VERSION 5.8 ;
BUSBITCHARS "[]" ;
DIVIDERCHAR "/" ;
UNITS
    DATABASE MICRONS 1000 ;
END UNITS

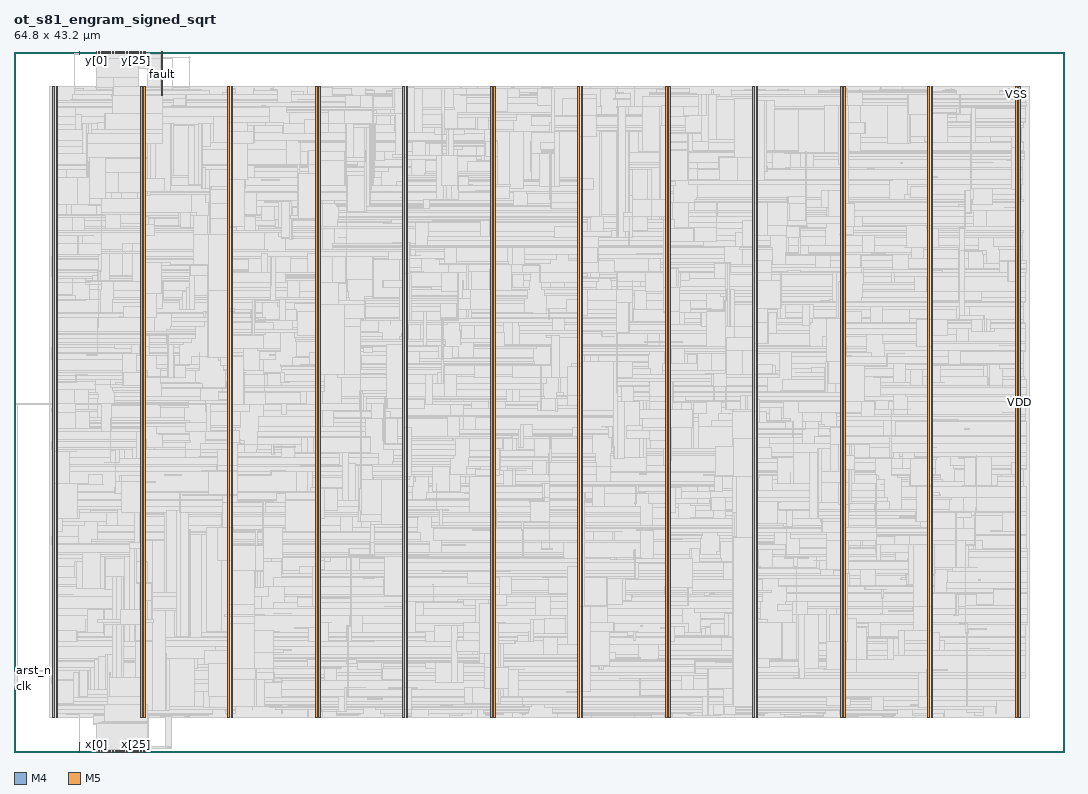
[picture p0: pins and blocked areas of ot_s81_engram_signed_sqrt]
MACRO ot_s81_engram_signed_sqrt
  FOREIGN ot_s81_engram_signed_sqrt 0 0 ;
  CLASS BLOCK ;
  SIZE 64.8 BY 43.2 ;
  PIN arst_n
    DIRECTION INPUT ;
    USE SIGNAL ;
    PORT
      LAYER M4 ;
        RECT  0 4.992 0.084 5.016 ;
    END
  END arst_n
  PIN clk
    DIRECTION INPUT ;
    USE SIGNAL ;
    PORT
      LAYER M4 ;
        RECT  0 4.032 0.084 4.056 ;
    END
  END clk
  PIN fault
    DIRECTION OUTPUT ;
    USE SIGNAL ;
    PORT
      LAYER M5 ;
        RECT  9.12 43.116 9.144 43.2 ;
    END
    PORT
      LAYER M5 ;
        RECT  9.12 40.499 9.144 43.152 ;
    END
  END fault
  PIN v
    DIRECTION INPUT ;
    USE SIGNAL ;
    PORT
      LAYER M5 ;
        RECT  4.032 0 4.056 0.084 ;
    END
    PORT
      LAYER M5 ;
        RECT  4.032 0.016 4.056 0.611 ;
    END
  END v
  PIN vo
    DIRECTION OUTPUT ;
    USE SIGNAL ;
    PORT
      LAYER M5 ;
        RECT  4.032 43.116 4.056 43.2 ;
    END
    PORT
      LAYER M5 ;
        RECT  4.032 43.045 4.056 43.152 ;
    END
  END vo
  PIN x[0]
    DIRECTION INPUT ;
    USE SIGNAL ;
    PORT
      LAYER M5 ;
        RECT  5.088 0 5.112 0.084 ;
    END
  END x[0]
  PIN x[10]
    DIRECTION INPUT ;
    USE SIGNAL ;
    PORT
      LAYER M5 ;
        RECT  6.048 0 6.072 0.084 ;
    END
  END x[10]
  PIN x[11]
    DIRECTION INPUT ;
    USE SIGNAL ;
    PORT
      LAYER M5 ;
        RECT  6.144 0 6.168 0.084 ;
    END
  END x[11]
  PIN x[12]
    DIRECTION INPUT ;
    USE SIGNAL ;
    PORT
      LAYER M5 ;
        RECT  6.24 0 6.264 0.084 ;
    END
  END x[12]
  PIN x[13]
    DIRECTION INPUT ;
    USE SIGNAL ;
    PORT
      LAYER M5 ;
        RECT  6.336 0 6.36 0.084 ;
    END
  END x[13]
  PIN x[14]
    DIRECTION INPUT ;
    USE SIGNAL ;
    PORT
      LAYER M5 ;
        RECT  6.432 0 6.456 0.084 ;
    END
  END x[14]
  PIN x[15]
    DIRECTION INPUT ;
    USE SIGNAL ;
    PORT
      LAYER M5 ;
        RECT  6.528 0 6.552 0.084 ;
    END
  END x[15]
  PIN x[16]
    DIRECTION INPUT ;
    USE SIGNAL ;
    PORT
      LAYER M5 ;
        RECT  6.624 0 6.648 0.084 ;
    END
  END x[16]
  PIN x[17]
    DIRECTION INPUT ;
    USE SIGNAL ;
    PORT
      LAYER M5 ;
        RECT  6.72 0 6.744 0.084 ;
    END
  END x[17]
  PIN x[18]
    DIRECTION INPUT ;
    USE SIGNAL ;
    PORT
      LAYER M5 ;
        RECT  6.816 0 6.84 0.084 ;
    END
  END x[18]
  PIN x[19]
    DIRECTION INPUT ;
    USE SIGNAL ;
    PORT
      LAYER M5 ;
        RECT  6.912 0 6.936 0.084 ;
    END
  END x[19]
  PIN x[1]
    DIRECTION INPUT ;
    USE SIGNAL ;
    PORT
      LAYER M5 ;
        RECT  5.184 0 5.208 0.084 ;
    END
  END x[1]
  PIN x[20]
    DIRECTION INPUT ;
    USE SIGNAL ;
    PORT
      LAYER M5 ;
        RECT  7.008 0 7.032 0.084 ;
    END
  END x[20]
  PIN x[21]
    DIRECTION INPUT ;
    USE SIGNAL ;
    PORT
      LAYER M5 ;
        RECT  7.104 0 7.128 0.084 ;
    END
  END x[21]
  PIN x[22]
    DIRECTION INPUT ;
    USE SIGNAL ;
    PORT
      LAYER M5 ;
        RECT  7.2 0 7.224 0.084 ;
    END
  END x[22]
  PIN x[23]
    DIRECTION INPUT ;
    USE SIGNAL ;
    PORT
      LAYER M5 ;
        RECT  7.296 0 7.32 0.084 ;
    END
  END x[23]
  PIN x[24]
    DIRECTION INPUT ;
    USE SIGNAL ;
    PORT
      LAYER M5 ;
        RECT  7.392 0 7.416 0.084 ;
    END
  END x[24]
  PIN x[25]
    DIRECTION INPUT ;
    USE SIGNAL ;
    PORT
      LAYER M5 ;
        RECT  7.488 0 7.512 0.084 ;
    END
  END x[25]
  PIN x[26]
    DIRECTION INPUT ;
    USE SIGNAL ;
    PORT
      LAYER M5 ;
        RECT  7.584 0 7.608 0.084 ;
    END
  END x[26]
  PIN x[27]
    DIRECTION INPUT ;
    USE SIGNAL ;
    PORT
      LAYER M5 ;
        RECT  7.68 0 7.704 0.084 ;
    END
  END x[27]
  PIN x[28]
    DIRECTION INPUT ;
    USE SIGNAL ;
    PORT
      LAYER M5 ;
        RECT  7.776 0 7.8 0.084 ;
    END
  END x[28]
  PIN x[29]
    DIRECTION INPUT ;
    USE SIGNAL ;
    PORT
      LAYER M5 ;
        RECT  7.872 0 7.896 0.084 ;
    END
  END x[29]
  PIN x[2]
    DIRECTION INPUT ;
    USE SIGNAL ;
    PORT
      LAYER M5 ;
        RECT  5.28 0 5.304 0.084 ;
    END
  END x[2]
  PIN x[30]
    DIRECTION INPUT ;
    USE SIGNAL ;
    PORT
      LAYER M5 ;
        RECT  7.968 0 7.992 0.084 ;
    END
  END x[30]
  PIN x[31]
    DIRECTION INPUT ;
    USE SIGNAL ;
    PORT
      LAYER M5 ;
        RECT  8.064 0 8.088 0.084 ;
    END
  END x[31]
  PIN x[3]
    DIRECTION INPUT ;
    USE SIGNAL ;
    PORT
      LAYER M5 ;
        RECT  5.376 0 5.4 0.084 ;
    END
  END x[3]
  PIN x[4]
    DIRECTION INPUT ;
    USE SIGNAL ;
    PORT
      LAYER M5 ;
        RECT  5.472 0 5.496 0.084 ;
    END
  END x[4]
  PIN x[5]
    DIRECTION INPUT ;
    USE SIGNAL ;
    PORT
      LAYER M5 ;
        RECT  5.568 0 5.592 0.084 ;
    END
  END x[5]
  PIN x[6]
    DIRECTION INPUT ;
    USE SIGNAL ;
    PORT
      LAYER M5 ;
        RECT  5.664 0 5.688 0.084 ;
    END
  END x[6]
  PIN x[7]
    DIRECTION INPUT ;
    USE SIGNAL ;
    PORT
      LAYER M5 ;
        RECT  5.76 0 5.784 0.084 ;
    END
  END x[7]
  PIN x[8]
    DIRECTION INPUT ;
    USE SIGNAL ;
    PORT
      LAYER M5 ;
        RECT  5.856 0 5.88 0.084 ;
    END
  END x[8]
  PIN x[9]
    DIRECTION INPUT ;
    USE SIGNAL ;
    PORT
      LAYER M5 ;
        RECT  5.952 0 5.976 0.084 ;
    END
  END x[9]
  PIN y[0]
    DIRECTION OUTPUT ;
    USE SIGNAL ;
    PORT
      LAYER M5 ;
        RECT  5.088 43.116 5.112 43.2 ;
    END
  END y[0]
  PIN y[10]
    DIRECTION OUTPUT ;
    USE SIGNAL ;
    PORT
      LAYER M5 ;
        RECT  6.048 43.116 6.072 43.2 ;
    END
  END y[10]
  PIN y[11]
    DIRECTION OUTPUT ;
    USE SIGNAL ;
    PORT
      LAYER M5 ;
        RECT  6.144 43.116 6.168 43.2 ;
    END
  END y[11]
  PIN y[12]
    DIRECTION OUTPUT ;
    USE SIGNAL ;
    PORT
      LAYER M5 ;
        RECT  6.24 43.116 6.264 43.2 ;
    END
  END y[12]
  PIN y[13]
    DIRECTION OUTPUT ;
    USE SIGNAL ;
    PORT
      LAYER M5 ;
        RECT  6.336 43.116 6.36 43.2 ;
    END
  END y[13]
  PIN y[14]
    DIRECTION OUTPUT ;
    USE SIGNAL ;
    PORT
      LAYER M5 ;
        RECT  6.432 43.116 6.456 43.2 ;
    END
  END y[14]
  PIN y[15]
    DIRECTION OUTPUT ;
    USE SIGNAL ;
    PORT
      LAYER M5 ;
        RECT  6.528 43.116 6.552 43.2 ;
    END
  END y[15]
  PIN y[16]
    DIRECTION OUTPUT ;
    USE SIGNAL ;
    PORT
      LAYER M5 ;
        RECT  6.624 43.116 6.648 43.2 ;
    END
  END y[16]
  PIN y[17]
    DIRECTION OUTPUT ;
    USE SIGNAL ;
    PORT
      LAYER M5 ;
        RECT  6.72 43.116 6.744 43.2 ;
    END
  END y[17]
  PIN y[18]
    DIRECTION OUTPUT ;
    USE SIGNAL ;
    PORT
      LAYER M5 ;
        RECT  6.816 43.116 6.84 43.2 ;
    END
  END y[18]
  PIN y[19]
    DIRECTION OUTPUT ;
    USE SIGNAL ;
    PORT
      LAYER M5 ;
        RECT  6.912 43.116 6.936 43.2 ;
    END
  END y[19]
  PIN y[1]
    DIRECTION OUTPUT ;
    USE SIGNAL ;
    PORT
      LAYER M5 ;
        RECT  5.184 43.116 5.208 43.2 ;
    END
  END y[1]
  PIN y[20]
    DIRECTION OUTPUT ;
    USE SIGNAL ;
    PORT
      LAYER M5 ;
        RECT  7.008 43.116 7.032 43.2 ;
    END
  END y[20]
  PIN y[21]
    DIRECTION OUTPUT ;
    USE SIGNAL ;
    PORT
      LAYER M5 ;
        RECT  7.104 43.116 7.128 43.2 ;
    END
  END y[21]
  PIN y[22]
    DIRECTION OUTPUT ;
    USE SIGNAL ;
    PORT
      LAYER M5 ;
        RECT  7.2 43.116 7.224 43.2 ;
    END
  END y[22]
  PIN y[23]
    DIRECTION OUTPUT ;
    USE SIGNAL ;
    PORT
      LAYER M5 ;
        RECT  7.296 43.116 7.32 43.2 ;
    END
  END y[23]
  PIN y[24]
    DIRECTION OUTPUT ;
    USE SIGNAL ;
    PORT
      LAYER M5 ;
        RECT  7.392 43.116 7.416 43.2 ;
    END
  END y[24]
  PIN y[25]
    DIRECTION OUTPUT ;
    USE SIGNAL ;
    PORT
      LAYER M5 ;
        RECT  7.488 43.116 7.512 43.2 ;
    END
  END y[25]
  PIN y[26]
    DIRECTION OUTPUT ;
    USE SIGNAL ;
    PORT
      LAYER M5 ;
        RECT  7.584 43.116 7.608 43.2 ;
    END
  END y[26]
  PIN y[27]
    DIRECTION OUTPUT ;
    USE SIGNAL ;
    PORT
      LAYER M5 ;
        RECT  7.68 43.116 7.704 43.2 ;
    END
  END y[27]
  PIN y[28]
    DIRECTION OUTPUT ;
    USE SIGNAL ;
    PORT
      LAYER M5 ;
        RECT  7.776 43.116 7.8 43.2 ;
    END
  END y[28]
  PIN y[29]
    DIRECTION OUTPUT ;
    USE SIGNAL ;
    PORT
      LAYER M5 ;
        RECT  7.872 43.116 7.896 43.2 ;
    END
  END y[29]
  PIN y[2]
    DIRECTION OUTPUT ;
    USE SIGNAL ;
    PORT
      LAYER M5 ;
        RECT  5.28 43.116 5.304 43.2 ;
    END
  END y[2]
  PIN y[30]
    DIRECTION OUTPUT ;
    USE SIGNAL ;
    PORT
      LAYER M5 ;
        RECT  7.968 43.116 7.992 43.2 ;
    END
  END y[30]
  PIN y[31]
    DIRECTION OUTPUT ;
    USE SIGNAL ;
    PORT
      LAYER M5 ;
        RECT  8.064 43.116 8.088 43.2 ;
    END
  END y[31]
  PIN y[3]
    DIRECTION OUTPUT ;
    USE SIGNAL ;
    PORT
      LAYER M5 ;
        RECT  5.376 43.116 5.4 43.2 ;
    END
  END y[3]
  PIN y[4]
    DIRECTION OUTPUT ;
    USE SIGNAL ;
    PORT
      LAYER M5 ;
        RECT  5.472 43.116 5.496 43.2 ;
    END
  END y[4]
  PIN y[5]
    DIRECTION OUTPUT ;
    USE SIGNAL ;
    PORT
      LAYER M5 ;
        RECT  5.568 43.116 5.592 43.2 ;
    END
  END y[5]
  PIN y[6]
    DIRECTION OUTPUT ;
    USE SIGNAL ;
    PORT
      LAYER M5 ;
        RECT  5.664 43.116 5.688 43.2 ;
    END
  END y[6]
  PIN y[7]
    DIRECTION OUTPUT ;
    USE SIGNAL ;
    PORT
      LAYER M5 ;
        RECT  5.76 43.116 5.784 43.2 ;
    END
  END y[7]
  PIN y[8]
    DIRECTION OUTPUT ;
    USE SIGNAL ;
    PORT
      LAYER M5 ;
        RECT  5.856 43.116 5.88 43.2 ;
    END
  END y[8]
  PIN y[9]
    DIRECTION OUTPUT ;
    USE SIGNAL ;
    PORT
      LAYER M5 ;
        RECT  5.952 43.116 5.976 43.2 ;
    END
  END y[9]
  PIN VDD
    DIRECTION INOUT ;
    USE POWER ;
    PORT
      LAYER M5 ;
        RECT  61.992 2.151 62.112 41.049 ;
        RECT  56.592 2.151 56.712 41.049 ;
        RECT  51.192 2.151 51.312 41.049 ;
        RECT  45.792 2.151 45.912 41.049 ;
        RECT  40.392 2.151 40.512 41.049 ;
        RECT  34.992 2.151 35.112 41.049 ;
        RECT  29.592 2.151 29.712 41.049 ;
        RECT  24.192 2.151 24.312 41.049 ;
        RECT  18.792 2.151 18.912 41.049 ;
        RECT  13.392 2.151 13.512 41.049 ;
        RECT  7.992 2.151 8.112 41.049 ;
        RECT  2.592 2.151 2.712 41.049 ;
    END
  END VDD
  PIN VSS
    DIRECTION INOUT ;
    USE GROUND ;
    PORT
      LAYER M5 ;
        RECT  61.8 2.137 61.92 41.063 ;
        RECT  56.4 2.137 56.52 41.063 ;
        RECT  51 2.137 51.12 41.063 ;
        RECT  45.6 2.137 45.72 41.063 ;
        RECT  40.2 2.137 40.32 41.063 ;
        RECT  34.8 2.137 34.92 41.063 ;
        RECT  29.4 2.137 29.52 41.063 ;
        RECT  24 2.137 24.12 41.063 ;
        RECT  18.6 2.137 18.72 41.063 ;
        RECT  13.2 2.137 13.32 41.063 ;
        RECT  7.8 2.137 7.92 41.063 ;
        RECT  2.4 2.137 2.52 41.063 ;
    END
  END VSS
  # OT_OBS_CLOSED layer=M5 d_um=1.536 added=132
  OBS
    LAYER RVTN ;
     RECT  2.16 2.16 62.64 2.295 ;
     RECT  2.16 2.565 62.64 2.835 ;
     RECT  2.16 3.105 62.64 3.375 ;
     RECT  2.16 3.645 62.64 3.915 ;
     RECT  2.16 4.185 62.64 4.455 ;
     RECT  2.16 4.725 62.64 4.995 ;
     RECT  2.16 5.265 62.64 5.535 ;
     RECT  2.16 5.805 62.64 6.075 ;
     RECT  2.16 6.345 62.64 6.615 ;
     RECT  2.16 6.885 62.64 7.155 ;
     RECT  2.16 7.425 62.64 7.695 ;
     RECT  2.16 7.965 62.64 8.235 ;
     RECT  2.16 8.505 62.64 8.775 ;
     RECT  2.16 9.045 62.64 9.315 ;
     RECT  2.16 9.585 62.64 9.855 ;
     RECT  2.16 10.125 62.64 10.395 ;
     RECT  2.16 10.665 62.64 10.935 ;
     RECT  2.16 11.205 62.64 11.475 ;
     RECT  2.16 11.745 62.64 12.015 ;
     RECT  2.16 12.285 62.64 12.555 ;
     RECT  2.16 12.825 62.64 13.095 ;
     RECT  2.16 13.365 62.64 13.635 ;
     RECT  2.16 13.905 62.64 14.175 ;
     RECT  2.16 14.445 62.64 14.715 ;
     RECT  2.16 14.985 62.64 15.255 ;
     RECT  2.16 15.525 62.64 15.795 ;
     RECT  2.16 16.065 62.64 16.335 ;
     RECT  2.16 16.605 62.64 16.875 ;
     RECT  2.16 17.145 62.64 17.415 ;
     RECT  2.16 17.685 62.64 17.955 ;
     RECT  2.16 18.225 62.64 18.495 ;
     RECT  2.16 18.765 62.64 19.035 ;
     RECT  2.16 19.305 62.64 19.575 ;
     RECT  2.16 19.845 62.64 20.115 ;
     RECT  2.16 20.385 62.64 20.655 ;
     RECT  2.16 20.925 62.64 21.195 ;
     RECT  2.16 21.465 62.64 21.735 ;
     RECT  2.16 22.005 62.64 22.275 ;
     RECT  2.16 22.545 62.64 22.815 ;
     RECT  2.16 23.085 62.64 23.355 ;
     RECT  2.16 23.625 62.64 23.895 ;
     RECT  2.16 24.165 62.64 24.435 ;
     RECT  2.16 24.705 62.64 24.975 ;
     RECT  2.16 25.245 62.64 25.515 ;
     RECT  2.16 25.785 62.64 26.055 ;
     RECT  2.16 26.325 62.64 26.595 ;
     RECT  2.16 26.865 62.64 27.135 ;
     RECT  2.16 27.405 62.64 27.675 ;
     RECT  2.16 27.945 62.64 28.215 ;
     RECT  2.16 28.485 62.64 28.755 ;
     RECT  2.16 29.025 62.64 29.295 ;
     RECT  2.16 29.565 62.64 29.835 ;
     RECT  2.16 30.105 62.64 30.375 ;
     RECT  2.16 30.645 62.64 30.915 ;
     RECT  2.16 31.185 62.64 31.455 ;
     RECT  2.16 31.725 62.64 31.995 ;
     RECT  2.16 32.265 62.64 32.535 ;
     RECT  2.16 32.805 62.64 33.075 ;
     RECT  2.16 33.345 62.64 33.615 ;
     RECT  2.16 33.885 62.64 34.155 ;
     RECT  2.16 34.425 62.64 34.695 ;
     RECT  2.16 34.965 62.64 35.235 ;
     RECT  2.16 35.505 62.64 35.775 ;
     RECT  2.16 36.045 62.64 36.315 ;
     RECT  2.16 36.585 62.64 36.855 ;
     RECT  2.16 37.125 62.64 37.395 ;
     RECT  2.16 37.665 62.64 37.935 ;
     RECT  2.16 38.205 62.64 38.475 ;
     RECT  2.16 38.745 62.64 39.015 ;
     RECT  2.16 39.285 62.64 39.555 ;
     RECT  2.16 39.825 62.64 40.095 ;
     RECT  2.16 40.365 62.64 40.635 ;
     RECT  2.16 40.905 62.64 41.04 ;
    LAYER RVTP ;
     RECT  2.16 2.295 62.64 2.565 ;
     RECT  2.16 2.835 62.64 3.105 ;
     RECT  2.16 3.375 62.64 3.645 ;
     RECT  2.16 3.915 62.64 4.185 ;
     RECT  2.16 4.455 62.64 4.725 ;
     RECT  2.16 4.995 62.64 5.265 ;
     RECT  2.16 5.535 62.64 5.805 ;
     RECT  2.16 6.075 62.64 6.345 ;
     RECT  2.16 6.615 62.64 6.885 ;
     RECT  2.16 7.155 62.64 7.425 ;
     RECT  2.16 7.695 62.64 7.965 ;
     RECT  2.16 8.235 62.64 8.505 ;
     RECT  2.16 8.775 62.64 9.045 ;
     RECT  2.16 9.315 62.64 9.585 ;
     RECT  2.16 9.855 62.64 10.125 ;
     RECT  2.16 10.395 62.64 10.665 ;
     RECT  2.16 10.935 62.64 11.205 ;
     RECT  2.16 11.475 62.64 11.745 ;
     RECT  2.16 12.015 62.64 12.285 ;
     RECT  2.16 12.555 62.64 12.825 ;
     RECT  2.16 13.095 62.64 13.365 ;
     RECT  2.16 13.635 62.64 13.905 ;
     RECT  2.16 14.175 62.64 14.445 ;
     RECT  2.16 14.715 62.64 14.985 ;
     RECT  2.16 15.255 62.64 15.525 ;
     RECT  2.16 15.795 62.64 16.065 ;
     RECT  2.16 16.335 62.64 16.605 ;
     RECT  2.16 16.875 62.64 17.145 ;
     RECT  2.16 17.415 62.64 17.685 ;
     RECT  2.16 17.955 62.64 18.225 ;
     RECT  2.16 18.495 62.64 18.765 ;
     RECT  2.16 19.035 62.64 19.305 ;
     RECT  2.16 19.575 62.64 19.845 ;
     RECT  2.16 20.115 62.64 20.385 ;
     RECT  2.16 20.655 62.64 20.925 ;
     RECT  2.16 21.195 62.64 21.465 ;
     RECT  2.16 21.735 62.64 22.005 ;
     RECT  2.16 22.275 62.64 22.545 ;
     RECT  2.16 22.815 62.64 23.085 ;
     RECT  2.16 23.355 62.64 23.625 ;
     RECT  2.16 23.895 62.64 24.165 ;
     RECT  2.16 24.435 62.64 24.705 ;
     RECT  2.16 24.975 62.64 25.245 ;
     RECT  2.16 25.515 62.64 25.785 ;
     RECT  2.16 26.055 62.64 26.325 ;
     RECT  2.16 26.595 62.64 26.865 ;
     RECT  2.16 27.135 62.64 27.405 ;
     RECT  2.16 27.675 62.64 27.945 ;
     RECT  2.16 28.215 62.64 28.485 ;
     RECT  2.16 28.755 62.64 29.025 ;
     RECT  2.16 29.295 62.64 29.565 ;
     RECT  2.16 29.835 62.64 30.105 ;
     RECT  2.16 30.375 62.64 30.645 ;
     RECT  2.16 30.915 62.64 31.185 ;
     RECT  2.16 31.455 62.64 31.725 ;
     RECT  2.16 31.995 62.64 32.265 ;
     RECT  2.16 32.535 62.64 32.805 ;
     RECT  2.16 33.075 62.64 33.345 ;
     RECT  2.16 33.615 62.64 33.885 ;
     RECT  2.16 34.155 62.64 34.425 ;
     RECT  2.16 34.695 62.64 34.965 ;
     RECT  2.16 35.235 62.64 35.505 ;
     RECT  2.16 35.775 62.64 36.045 ;
     RECT  2.16 36.315 62.64 36.585 ;
     RECT  2.16 36.855 62.64 37.125 ;
     RECT  2.16 37.395 62.64 37.665 ;
     RECT  2.16 37.935 62.64 38.205 ;
     RECT  2.16 38.475 62.64 38.745 ;
     RECT  2.16 39.015 62.64 39.285 ;
     RECT  2.16 39.555 62.64 39.825 ;
     RECT  2.16 40.095 62.64 40.365 ;
     RECT  2.16 40.635 62.64 40.905 ;
    LAYER M1 ;
     RECT  2.16 2.151 62.64 41.049 ;
    LAYER M2 ;
     RECT  2.16 2.151 18.139 41.049 ;
     RECT  18.139 2.106 19.067 41.049 ;
     RECT  19.067 2.151 28.579 41.049 ;
     RECT  28.579 2.151 30.767 41.094 ;
     RECT  30.767 2.151 35.599 41.049 ;
     RECT  35.599 2.106 38.291 41.049 ;
     RECT  38.291 2.151 62.64 41.049 ;
    LAYER M3 ;
     RECT  5.148 0.091 5.778 0.139 ;
     RECT  6.516 0.091 6.93 0.139 ;
     RECT  5.148 0.139 6.93 0.235 ;
     RECT  9.72 0.187 9.738 0.283 ;
     RECT  9.432 0.283 9.738 0.331 ;
     RECT  5.148 0.235 7.506 1.723 ;
     RECT  8.28 0.091 8.298 1.723 ;
     RECT  18.144 2.101 18.162 2.143 ;
     RECT  19.044 2.101 19.062 2.143 ;
     RECT  35.604 2.101 35.622 2.143 ;
     RECT  9.324 0.331 9.738 2.191 ;
     RECT  24.015 2.143 24.105 2.191 ;
     RECT  40.215 2.143 40.305 2.191 ;
     RECT  51.015 2.143 51.105 2.191 ;
     RECT  47.556 2.191 48.15 2.203 ;
     RECT  34.815 2.143 35.622 2.227 ;
     RECT  38.268 2.101 38.286 2.227 ;
     RECT  53.568 2.191 54.306 2.227 ;
     RECT  55.62 2.191 55.638 2.227 ;
     RECT  56.415 2.143 56.505 2.227 ;
     RECT  34.776 2.227 36.018 2.251 ;
     RECT  37.62 2.227 38.394 2.251 ;
     RECT  39.312 2.191 39.33 2.251 ;
     RECT  42.768 2.227 42.786 2.251 ;
     RECT  43.56 2.227 43.578 2.251 ;
     RECT  52.848 2.227 54.306 2.251 ;
     RECT  2.415 2.143 2.505 2.263 ;
     RECT  4.932 1.723 8.298 2.263 ;
     RECT  9.036 2.191 9.738 2.263 ;
     RECT  10.512 2.191 10.854 2.263 ;
     RECT  21.24 2.227 21.258 2.263 ;
     RECT  22.86 2.191 22.878 2.263 ;
     RECT  24.015 2.191 24.534 2.263 ;
     RECT  26.856 2.191 26.874 2.263 ;
     RECT  27.684 2.227 27.702 2.263 ;
     RECT  29.415 2.143 29.505 2.263 ;
     RECT  34.776 2.251 36.666 2.263 ;
     RECT  37.62 2.251 39.33 2.263 ;
     RECT  41.76 2.251 41.778 2.263 ;
     RECT  45.615 2.143 45.705 2.263 ;
     RECT  51.015 2.191 52.11 2.263 ;
     RECT  52.848 2.251 54.414 2.263 ;
     RECT  55.62 2.227 56.505 2.263 ;
     RECT  59.292 2.227 59.31 2.263 ;
     RECT  4.032 0.571 4.05 2.299 ;
     RECT  34.776 2.263 39.33 2.299 ;
     RECT  40.14 2.191 40.626 2.299 ;
     RECT  41.652 2.263 41.778 2.299 ;
     RECT  44.46 2.227 44.478 2.299 ;
     RECT  47.556 2.203 48.546 2.299 ;
     RECT  3.528 2.299 4.05 2.335 ;
     RECT  4.932 2.263 12.006 2.335 ;
     RECT  13.215 2.143 13.305 2.335 ;
     RECT  19.872 2.263 21.258 2.335 ;
     RECT  29.088 2.263 29.505 2.335 ;
     RECT  31.356 2.263 31.374 2.335 ;
     RECT  41.544 2.299 41.778 2.335 ;
     RECT  44.46 2.299 44.514 2.335 ;
     RECT  45.615 2.263 46.314 2.335 ;
     RECT  51.012 2.263 54.414 2.335 ;
     RECT  2.376 2.263 2.505 2.371 ;
     RECT  3.24 2.335 4.05 2.371 ;
     RECT  4.932 2.335 12.222 2.371 ;
     RECT  13.14 2.335 13.305 2.371 ;
     RECT  19.872 2.335 21.366 2.371 ;
     RECT  22.86 2.263 24.534 2.371 ;
     RECT  25.56 2.263 25.578 2.371 ;
     RECT  26.856 2.263 27.702 2.371 ;
     RECT  29.088 2.335 30.186 2.371 ;
     RECT  31.356 2.335 31.59 2.371 ;
     RECT  33.552 2.191 33.57 2.371 ;
     RECT  34.776 2.299 40.626 2.371 ;
     RECT  41.472 2.335 41.778 2.371 ;
     RECT  42.768 2.251 43.578 2.371 ;
     RECT  44.46 2.335 46.314 2.371 ;
     RECT  49.932 2.203 49.95 2.371 ;
     RECT  50.94 2.335 54.414 2.371 ;
     RECT  55.44 2.263 56.505 2.371 ;
     RECT  57.384 2.191 57.402 2.371 ;
     RECT  61.815 2.143 61.905 2.413 ;
     RECT  28.98 2.371 30.186 2.461 ;
     RECT  31.176 2.371 31.734 2.461 ;
     RECT  33.228 2.371 41.958 2.461 ;
     RECT  42.732 2.371 43.578 2.461 ;
     RECT  44.46 2.371 46.494 2.461 ;
     RECT  47.304 2.299 48.546 2.461 ;
     RECT  49.536 2.371 50.094 2.461 ;
     RECT  59.292 2.263 59.814 2.461 ;
     RECT  44.46 2.461 50.094 2.533 ;
     RECT  50.94 2.371 54.522 2.533 ;
     RECT  44.46 2.533 54.522 2.561 ;
     RECT  13.068 2.371 13.662 2.569 ;
     RECT  28.98 2.461 31.734 2.569 ;
     RECT  16.524 2.371 16.542 2.605 ;
     RECT  18.144 2.143 19.062 2.605 ;
     RECT  19.872 2.371 21.546 2.605 ;
     RECT  22.644 2.371 24.534 2.605 ;
     RECT  58.788 2.461 59.814 2.605 ;
     RECT  2.376 2.371 12.222 2.641 ;
     RECT  12.996 2.569 13.662 2.641 ;
     RECT  16.488 2.605 16.542 2.641 ;
     RECT  18.144 2.605 21.546 2.641 ;
     RECT  22.644 2.605 24.606 2.641 ;
     RECT  25.56 2.371 28.206 2.641 ;
     RECT  28.98 2.569 31.842 2.641 ;
     RECT  33.228 2.461 43.578 2.641 ;
     RECT  44.46 2.561 52.902 2.641 ;
     RECT  53.676 2.561 54.522 2.641 ;
     RECT  55.44 2.371 57.402 2.641 ;
     RECT  58.464 2.605 59.814 2.641 ;
     RECT  16.164 2.641 21.546 2.731 ;
     RECT  22.32 2.641 31.842 2.731 ;
     RECT  33.228 2.641 52.902 2.731 ;
     RECT  15.912 2.731 31.842 2.767 ;
     RECT  53.676 2.641 59.814 2.779 ;
     RECT  60.588 2.371 60.606 2.779 ;
     RECT  14.724 2.641 14.742 2.803 ;
     RECT  15.768 2.767 31.842 2.803 ;
     RECT  2.376 2.641 13.662 2.875 ;
     RECT  2.376 2.875 13.77 2.911 ;
     RECT  14.724 2.803 31.95 2.911 ;
     RECT  32.76 2.731 52.902 2.911 ;
     RECT  2.376 2.911 13.914 3.145 ;
     RECT  14.724 2.911 52.902 3.145 ;
     RECT  53.676 2.779 60.606 3.181 ;
     RECT  61.815 2.413 62.097 3.181 ;
     RECT  2.376 3.145 52.902 3.371 ;
     RECT  2.376 3.371 15.426 3.389 ;
     RECT  16.524 3.371 52.902 3.451 ;
     RECT  53.676 3.181 62.097 3.451 ;
     RECT  2.376 3.389 15.39 3.569 ;
     RECT  16.524 3.451 62.097 3.839 ;
     RECT  12.852 3.569 15.39 3.875 ;
     RECT  2.376 3.569 12.078 4.225 ;
     RECT  14.508 3.875 15.39 4.315 ;
     RECT  12.852 3.875 13.734 4.397 ;
     RECT  16.524 3.839 41.166 4.415 ;
     RECT  2.304 4.225 12.078 4.495 ;
     RECT  12.852 4.397 13.497 4.495 ;
     RECT  14.508 4.315 15.786 4.531 ;
     RECT  16.524 4.415 19.134 4.531 ;
     RECT  41.904 3.839 62.097 4.531 ;
     RECT  14.508 4.531 19.134 4.603 ;
     RECT  19.908 4.415 41.166 4.729 ;
     RECT  41.904 4.531 62.406 4.729 ;
     RECT  14.472 4.603 19.134 4.765 ;
     RECT  19.908 4.729 62.406 4.919 ;
     RECT  2.304 4.495 13.497 5.021 ;
     RECT  14.436 4.765 19.134 5.179 ;
     RECT  2.415 5.021 13.497 5.233 ;
     RECT  14.436 5.179 19.17 5.269 ;
     RECT  19.908 4.919 51.297 5.269 ;
     RECT  14.436 5.269 51.297 5.305 ;
     RECT  2.415 5.233 13.59 5.611 ;
     RECT  14.328 5.305 51.297 5.611 ;
     RECT  2.415 5.611 51.297 5.639 ;
     RECT  39.528 5.639 51.297 5.729 ;
     RECT  39.708 5.729 51.297 5.741 ;
     RECT  2.415 5.639 38.682 5.765 ;
     RECT  13.176 5.765 38.682 5.837 ;
     RECT  39.78 5.741 51.297 5.971 ;
     RECT  52.02 4.919 62.406 5.971 ;
     RECT  13.176 5.837 38.538 6.035 ;
     RECT  39.78 5.971 62.406 6.269 ;
     RECT  2.415 5.765 12.438 6.511 ;
     RECT  13.176 6.035 28.314 6.511 ;
     RECT  33.516 6.035 38.538 6.655 ;
     RECT  39.78 6.269 43.686 6.655 ;
     RECT  44.424 6.269 62.406 6.691 ;
     RECT  2.415 6.511 28.314 6.889 ;
     RECT  29.088 6.035 32.67 6.889 ;
     RECT  44.424 6.691 62.442 7.079 ;
     RECT  2.415 6.889 32.67 7.087 ;
     RECT  33.516 6.655 43.686 7.087 ;
     RECT  44.424 7.079 62.406 7.087 ;
     RECT  2.415 7.087 62.406 7.115 ;
     RECT  2.415 7.115 52.758 7.373 ;
     RECT  2.415 7.373 41.634 7.385 ;
     RECT  42.372 7.373 52.758 7.727 ;
     RECT  53.496 7.115 62.406 7.897 ;
     RECT  47.268 7.727 52.758 7.901 ;
     RECT  21.528 7.385 41.634 7.961 ;
     RECT  47.916 7.901 52.758 7.961 ;
     RECT  48.024 7.961 52.758 7.969 ;
     RECT  53.496 7.897 62.55 7.969 ;
     RECT  42.372 7.727 46.53 8.159 ;
     RECT  42.372 8.159 46.098 8.231 ;
     RECT  2.415 7.385 20.718 8.401 ;
     RECT  21.528 7.961 41.274 8.401 ;
     RECT  2.415 8.401 41.274 8.429 ;
     RECT  48.024 7.969 62.55 8.477 ;
     RECT  42.372 8.231 46.062 8.581 ;
     RECT  48.024 8.477 48.042 8.707 ;
     RECT  48.96 8.477 62.55 8.843 ;
     RECT  33.084 8.429 41.274 8.851 ;
     RECT  42.012 8.581 46.062 8.851 ;
     RECT  2.415 8.429 32.202 8.879 ;
     RECT  48.96 8.843 55.674 8.969 ;
     RECT  47.124 8.707 48.042 9.113 ;
     RECT  16.02 8.879 32.202 9.239 ;
     RECT  47.592 9.113 48.042 9.275 ;
     RECT  33.084 8.851 46.062 9.283 ;
     RECT  47.664 9.275 48.042 9.283 ;
     RECT  48.96 8.969 55.602 9.283 ;
     RECT  2.415 8.879 15.246 9.625 ;
     RECT  16.704 9.239 32.202 9.625 ;
     RECT  33.084 9.283 46.206 9.625 ;
     RECT  16.704 9.625 46.206 9.725 ;
     RECT  47.664 9.283 55.602 9.787 ;
     RECT  56.415 8.843 62.55 9.787 ;
     RECT  47.664 9.787 62.55 9.821 ;
     RECT  30.708 9.725 46.206 9.823 ;
     RECT  30.708 9.823 46.746 9.959 ;
     RECT  57.528 9.821 62.55 10.085 ;
     RECT  2.415 9.625 15.678 10.201 ;
     RECT  16.704 9.725 29.97 10.201 ;
     RECT  47.664 9.821 56.79 10.201 ;
     RECT  2.415 10.201 29.97 10.205 ;
     RECT  47.16 10.201 56.79 10.301 ;
     RECT  2.415 10.205 15.246 10.355 ;
     RECT  57.564 10.085 62.55 10.463 ;
     RECT  30.708 9.959 46.206 10.625 ;
     RECT  44.532 10.625 46.206 10.705 ;
     RECT  47.16 10.301 52.254 10.705 ;
     RECT  15.984 10.205 29.97 10.769 ;
     RECT  16.524 10.769 29.97 10.831 ;
     RECT  30.708 10.625 43.794 10.831 ;
     RECT  44.532 10.705 52.254 10.895 ;
     RECT  53.136 10.301 56.79 10.903 ;
     RECT  53.136 10.903 56.826 11.011 ;
     RECT  16.524 10.831 43.794 11.021 ;
     RECT  44.532 10.895 49.77 11.021 ;
     RECT  57.6 10.463 62.55 11.129 ;
     RECT  16.56 11.021 43.794 11.201 ;
     RECT  50.58 10.895 52.254 11.245 ;
     RECT  53.136 11.011 56.862 11.245 ;
     RECT  57.6 11.129 57.906 11.245 ;
     RECT  44.676 11.021 49.77 11.309 ;
     RECT  44.676 11.309 49.518 11.399 ;
     RECT  44.676 11.399 46.062 11.435 ;
     RECT  21.348 11.201 43.794 11.669 ;
     RECT  50.58 11.245 57.906 11.785 ;
     RECT  50.292 11.785 57.906 11.813 ;
     RECT  44.676 11.435 45.918 11.821 ;
     RECT  21.348 11.669 43.65 11.939 ;
     RECT  55.152 11.813 57.906 11.939 ;
     RECT  2.415 10.355 15.066 11.941 ;
     RECT  2.415 11.941 15.606 11.947 ;
     RECT  21.348 11.939 33.966 11.975 ;
     RECT  16.56 11.201 20.502 11.995 ;
     RECT  21.348 11.975 33.894 11.995 ;
     RECT  34.815 11.939 38.754 12.011 ;
     RECT  44.568 11.821 45.918 12.019 ;
     RECT  55.224 11.939 57.906 12.019 ;
     RECT  58.716 11.129 62.55 12.019 ;
     RECT  16.56 11.995 33.894 12.091 ;
     RECT  46.836 11.399 49.518 12.091 ;
     RECT  50.292 11.813 54.414 12.091 ;
     RECT  39.492 11.939 43.578 12.209 ;
     RECT  46.836 12.091 54.414 12.209 ;
     RECT  2.415 11.947 15.75 12.217 ;
     RECT  16.524 12.091 33.894 12.217 ;
     RECT  2.415 12.217 33.894 12.317 ;
     RECT  55.224 12.019 62.55 12.353 ;
     RECT  43.344 12.209 43.578 12.389 ;
     RECT  44.532 12.019 45.918 12.523 ;
     RECT  46.836 12.209 47.682 12.523 ;
     RECT  55.26 12.353 62.55 12.551 ;
     RECT  48.492 12.209 54.414 12.557 ;
     RECT  48.492 12.557 54.342 12.623 ;
     RECT  44.532 12.523 47.682 12.797 ;
     RECT  2.415 12.317 25.65 12.829 ;
     RECT  44.532 12.797 46.962 12.865 ;
     RECT  2.34 12.829 25.65 12.893 ;
     RECT  26.388 12.317 33.894 12.901 ;
     RECT  34.815 12.011 38.682 12.901 ;
     RECT  44.424 12.865 46.962 12.901 ;
     RECT  39.492 12.209 42.354 12.991 ;
     RECT  43.56 12.389 43.578 12.991 ;
     RECT  44.352 12.901 46.962 12.991 ;
     RECT  4.752 12.893 25.65 13.019 ;
     RECT  26.388 12.901 38.682 13.063 ;
     RECT  4.752 13.019 25.11 13.091 ;
     RECT  39.456 12.991 42.354 13.171 ;
     RECT  43.56 12.991 46.962 13.171 ;
     RECT  48.492 12.623 52.254 13.171 ;
     RECT  53.028 12.623 54.342 13.297 ;
     RECT  2.34 12.893 3.978 13.325 ;
     RECT  53.028 13.297 54.414 13.333 ;
     RECT  55.26 12.551 62.478 13.333 ;
     RECT  39.456 13.171 42.426 13.369 ;
     RECT  43.524 13.171 46.962 13.369 ;
     RECT  53.028 13.333 62.478 13.397 ;
     RECT  39.456 13.369 42.462 13.405 ;
     RECT  47.916 13.171 52.254 13.441 ;
     RECT  53.028 13.397 57.834 13.441 ;
     RECT  39.456 13.405 42.498 13.531 ;
     RECT  43.416 13.369 46.962 13.531 ;
     RECT  5.148 13.091 25.11 13.559 ;
     RECT  39.456 13.531 46.962 13.567 ;
     RECT  47.916 13.441 57.834 13.567 ;
     RECT  5.148 13.559 24.93 13.631 ;
     RECT  25.884 13.063 38.682 13.801 ;
     RECT  39.456 13.567 57.834 13.801 ;
     RECT  20.916 13.631 24.93 13.829 ;
     RECT  25.884 13.801 57.834 13.829 ;
     RECT  25.884 13.829 57.762 13.837 ;
     RECT  25.776 13.837 57.762 13.973 ;
     RECT  2.415 13.325 3.978 13.981 ;
     RECT  5.148 13.631 20.178 14.009 ;
     RECT  25.776 13.973 38.682 14.135 ;
     RECT  2.415 13.981 4.338 14.251 ;
     RECT  5.148 14.009 5.706 14.251 ;
     RECT  39.42 13.973 57.762 14.405 ;
     RECT  39.42 14.405 43.146 14.441 ;
     RECT  22.248 13.829 24.93 14.449 ;
     RECT  41.76 14.441 43.146 14.477 ;
     RECT  6.444 14.009 20.178 14.521 ;
     RECT  20.916 13.829 21.474 14.521 ;
     RECT  22.248 14.449 24.966 14.521 ;
     RECT  25.776 14.135 38.646 14.521 ;
     RECT  43.92 14.405 57.762 14.611 ;
     RECT  58.608 13.397 62.478 14.611 ;
     RECT  6.444 14.521 21.474 14.635 ;
     RECT  22.248 14.521 38.646 14.635 ;
     RECT  2.415 14.251 5.706 14.755 ;
     RECT  6.444 14.635 38.646 14.755 ;
     RECT  43.92 14.611 62.478 14.819 ;
     RECT  42.048 14.477 43.146 14.909 ;
     RECT  43.92 14.819 57.762 14.981 ;
     RECT  39.42 14.441 41.022 15.061 ;
     RECT  2.415 14.755 38.646 15.179 ;
     RECT  42.048 14.909 43.074 15.223 ;
     RECT  41.76 15.223 43.074 15.323 ;
     RECT  39.384 15.061 41.022 15.331 ;
     RECT  41.76 15.323 42.174 15.331 ;
     RECT  43.92 14.981 54.054 15.449 ;
     RECT  2.415 15.179 35.694 15.529 ;
     RECT  2.376 15.529 35.694 15.557 ;
     RECT  54.792 14.981 57.762 15.601 ;
     RECT  25.416 15.557 35.694 15.629 ;
     RECT  42.912 15.323 43.074 15.691 ;
     RECT  43.92 15.449 53.91 15.691 ;
     RECT  42.912 15.691 53.91 15.719 ;
     RECT  54.792 15.601 57.87 15.727 ;
     RECT  58.608 14.819 62.478 15.727 ;
     RECT  36.468 15.179 38.358 15.961 ;
     RECT  39.132 15.331 42.174 15.961 ;
     RECT  2.376 15.557 24.606 15.989 ;
     RECT  25.452 15.629 35.694 15.989 ;
     RECT  2.376 15.989 21.438 16.061 ;
     RECT  42.912 15.719 53.694 16.133 ;
     RECT  18.288 16.061 21.438 16.295 ;
     RECT  22.212 15.989 24.606 16.363 ;
     RECT  54.792 15.727 62.478 16.367 ;
     RECT  36.468 15.961 42.174 16.375 ;
     RECT  42.912 16.133 45.954 16.375 ;
     RECT  25.56 15.989 35.694 16.411 ;
     RECT  36.468 16.375 45.954 16.411 ;
     RECT  25.56 16.411 45.954 16.439 ;
     RECT  30.924 16.439 44.298 16.529 ;
     RECT  25.56 16.439 30.186 16.601 ;
     RECT  30.96 16.529 44.298 16.673 ;
     RECT  22.212 16.363 24.642 16.681 ;
     RECT  54.792 16.367 62.298 16.709 ;
     RECT  54.792 16.709 57.294 16.799 ;
     RECT  46.836 16.133 53.694 16.835 ;
     RECT  18.396 16.295 21.438 16.915 ;
     RECT  22.212 16.681 24.786 16.915 ;
     RECT  54.792 16.799 57.15 16.915 ;
     RECT  45.036 16.439 45.954 16.951 ;
     RECT  18.396 16.915 24.786 17.041 ;
     RECT  25.56 16.601 26.982 17.041 ;
     RECT  54.54 16.915 57.15 17.041 ;
     RECT  18.396 17.041 26.982 17.069 ;
     RECT  46.836 16.835 53.334 17.069 ;
     RECT  45.036 16.951 46.026 17.077 ;
     RECT  46.836 17.069 53.19 17.077 ;
     RECT  30.96 16.673 35.946 17.105 ;
     RECT  54.144 17.041 57.15 17.117 ;
     RECT  45.036 17.077 53.19 17.128 ;
     RECT  27.864 16.601 30.186 17.141 ;
     RECT  36.792 16.673 44.298 17.221 ;
     RECT  45.036 17.128 53.154 17.221 ;
     RECT  2.376 16.061 17.442 17.311 ;
     RECT  18.396 17.069 26.91 17.311 ;
     RECT  36.792 17.221 53.154 17.339 ;
     RECT  44.1 17.339 53.154 17.375 ;
     RECT  58.032 16.709 62.298 17.455 ;
     RECT  27.936 17.141 30.186 17.491 ;
     RECT  30.96 17.105 32.022 17.491 ;
     RECT  58.032 17.455 62.514 17.491 ;
     RECT  54.144 17.117 56.898 17.519 ;
     RECT  2.376 17.311 26.91 17.609 ;
     RECT  27.936 17.491 32.022 17.645 ;
     RECT  57.96 17.491 62.514 17.689 ;
     RECT  2.415 17.609 26.91 17.753 ;
     RECT  32.832 17.105 35.946 17.879 ;
     RECT  44.46 17.375 53.154 17.879 ;
     RECT  23.364 17.753 26.91 17.915 ;
     RECT  28.044 17.645 32.022 17.995 ;
     RECT  32.832 17.879 35.91 17.995 ;
     RECT  55.584 17.519 56.898 18.031 ;
     RECT  23.4 17.915 26.91 18.121 ;
     RECT  44.64 17.879 53.154 18.121 ;
     RECT  54.144 17.519 54.81 18.121 ;
     RECT  2.415 17.753 22.482 18.149 ;
     RECT  28.044 17.995 35.91 18.149 ;
     RECT  55.584 18.031 56.934 18.157 ;
     RECT  2.415 18.149 16.506 18.185 ;
     RECT  11.412 18.185 16.506 18.221 ;
     RECT  28.08 18.149 35.91 18.221 ;
     RECT  44.64 18.121 54.81 18.241 ;
     RECT  55.584 18.157 57.042 18.265 ;
     RECT  57.816 17.689 62.514 18.265 ;
     RECT  23.4 18.121 27.126 18.301 ;
     RECT  36.792 17.339 43.362 18.301 ;
     RECT  17.316 18.149 22.482 18.419 ;
     RECT  32.976 18.221 35.91 18.419 ;
     RECT  36.792 18.301 43.47 18.419 ;
     RECT  11.484 18.221 16.506 18.455 ;
     RECT  46.62 18.241 54.81 18.463 ;
     RECT  55.584 18.265 62.514 18.463 ;
     RECT  17.316 18.419 21.978 18.491 ;
     RECT  36.9 18.419 43.47 18.535 ;
     RECT  36.9 18.535 43.578 18.571 ;
     RECT  28.08 18.221 32.13 18.599 ;
     RECT  2.415 18.185 10.602 18.661 ;
     RECT  23.4 18.301 27.27 18.661 ;
     RECT  14.976 18.455 16.506 18.689 ;
     RECT  30.996 18.599 32.13 18.689 ;
     RECT  2.34 18.661 10.602 18.797 ;
     RECT  36.9 18.571 43.722 18.811 ;
     RECT  44.64 18.241 45.897 18.811 ;
     RECT  22.788 18.661 27.27 18.959 ;
     RECT  15.048 18.689 16.506 19.003 ;
     RECT  17.316 18.491 17.73 19.003 ;
     RECT  46.62 18.463 62.514 19.031 ;
     RECT  11.484 18.455 14.238 19.067 ;
     RECT  9.144 18.797 10.602 19.111 ;
     RECT  2.34 18.797 8.19 19.139 ;
     RECT  22.788 18.959 22.806 19.201 ;
     RECT  9.144 19.111 10.89 19.229 ;
     RECT  11.844 19.067 14.238 19.229 ;
     RECT  11.844 19.229 13.986 19.265 ;
     RECT  2.376 19.139 8.19 19.301 ;
     RECT  23.688 18.959 27.27 19.339 ;
     RECT  28.08 18.599 30.222 19.339 ;
     RECT  31.032 18.689 32.13 19.345 ;
     RECT  33.084 18.419 35.694 19.345 ;
     RECT  15.048 19.003 17.73 19.381 ;
     RECT  18.468 18.491 21.978 19.381 ;
     RECT  36.9 18.811 45.897 19.381 ;
     RECT  46.62 19.031 48.654 19.381 ;
     RECT  36.9 19.381 48.654 19.387 ;
     RECT  23.688 19.339 30.222 19.471 ;
     RECT  31.032 19.345 35.694 19.471 ;
     RECT  15.048 19.381 21.978 19.499 ;
     RECT  23.688 19.471 35.694 19.499 ;
     RECT  49.392 19.031 62.514 19.499 ;
     RECT  49.644 19.499 62.514 19.517 ;
     RECT  9.144 19.229 10.818 19.579 ;
     RECT  36.684 19.387 48.654 19.579 ;
     RECT  27.504 19.499 35.694 19.615 ;
     RECT  36.504 19.579 48.654 19.615 ;
     RECT  8.928 19.579 10.818 19.651 ;
     RECT  27.504 19.615 48.654 19.661 ;
     RECT  2.376 19.301 8.097 19.769 ;
     RECT  15.048 19.499 21.69 19.805 ;
     RECT  11.844 19.265 13.662 19.849 ;
     RECT  27.504 19.661 42.246 19.901 ;
     RECT  22.716 19.201 22.806 19.915 ;
     RECT  43.02 19.661 48.654 19.921 ;
     RECT  2.415 19.769 8.097 19.949 ;
     RECT  43.02 19.921 48.87 19.949 ;
     RECT  4.644 19.949 8.097 20.039 ;
     RECT  11.808 19.849 13.662 20.047 ;
     RECT  4.68 20.039 8.097 20.083 ;
     RECT  8.82 19.651 10.818 20.083 ;
     RECT  15.084 19.805 21.69 20.111 ;
     RECT  49.644 19.517 53.658 20.111 ;
     RECT  11.808 20.047 13.986 20.147 ;
     RECT  49.644 20.111 50.022 20.219 ;
     RECT  4.68 20.083 10.818 20.299 ;
     RECT  4.68 20.299 10.962 20.345 ;
     RECT  19.692 20.111 21.69 20.345 ;
     RECT  54.396 19.517 62.514 20.381 ;
     RECT  48.672 19.949 48.87 20.425 ;
     RECT  49.644 20.219 49.842 20.425 ;
     RECT  4.68 20.345 10.818 20.453 ;
     RECT  50.76 20.111 53.658 20.461 ;
     RECT  54.396 20.381 62.442 20.461 ;
     RECT  43.02 19.949 47.898 20.489 ;
     RECT  22.716 19.915 22.914 20.551 ;
     RECT  23.688 19.499 26.766 20.551 ;
     RECT  47.376 20.489 47.898 20.579 ;
     RECT  19.728 20.345 21.69 20.581 ;
     RECT  22.716 20.551 26.766 20.581 ;
     RECT  4.68 20.453 10.53 20.615 ;
     RECT  4.68 20.615 8.097 20.651 ;
     RECT  19.728 20.581 26.766 20.651 ;
     RECT  28.476 19.901 42.246 20.651 ;
     RECT  15.084 20.111 18.897 20.723 ;
     RECT  50.76 20.461 62.442 20.723 ;
     RECT  24.015 20.651 26.766 20.731 ;
     RECT  27.504 19.901 27.738 20.731 ;
     RECT  28.476 20.651 40.497 20.731 ;
     RECT  24.015 20.731 40.497 20.759 ;
     RECT  53.1 20.723 62.442 20.849 ;
     RECT  43.488 20.489 46.602 20.885 ;
     RECT  41.22 20.651 42.246 20.893 ;
     RECT  50.76 20.723 52.326 20.893 ;
     RECT  48.672 20.425 49.842 20.929 ;
     RECT  48.384 20.929 49.842 20.965 ;
     RECT  50.724 20.893 52.326 20.965 ;
     RECT  19.728 20.651 23.238 20.993 ;
     RECT  2.415 19.949 3.798 21.001 ;
     RECT  4.68 20.651 5.166 21.001 ;
     RECT  11.916 20.147 13.986 21.001 ;
     RECT  15.408 20.723 18.897 21.067 ;
     RECT  19.728 20.993 22.842 21.067 ;
     RECT  2.34 21.001 5.166 21.119 ;
     RECT  53.1 20.849 54.306 21.149 ;
     RECT  2.34 21.119 3.762 21.191 ;
     RECT  27.756 20.759 40.497 21.191 ;
     RECT  9.036 20.615 10.53 21.271 ;
     RECT  43.668 20.885 46.602 21.271 ;
     RECT  47.376 20.579 47.466 21.271 ;
     RECT  6.012 20.651 8.097 21.389 ;
     RECT  27.756 21.191 32.742 21.389 ;
     RECT  9.036 21.271 10.746 21.397 ;
     RECT  15.408 21.067 22.842 21.425 ;
     RECT  33.48 21.191 40.497 21.425 ;
     RECT  6.228 21.389 8.097 21.541 ;
     RECT  8.928 21.397 10.746 21.541 ;
     RECT  38.232 21.425 40.497 21.541 ;
     RECT  41.22 20.893 42.75 21.541 ;
     RECT  43.668 21.271 47.466 21.541 ;
     RECT  27.756 21.389 30.438 21.569 ;
     RECT  43.668 21.541 47.502 21.631 ;
     RECT  48.384 20.965 52.326 21.631 ;
     RECT  55.152 20.849 62.442 21.631 ;
     RECT  43.668 21.631 52.326 21.643 ;
     RECT  53.1 21.149 54.27 21.643 ;
     RECT  6.228 21.541 10.746 21.667 ;
     RECT  11.808 21.001 14.526 21.667 ;
     RECT  38.232 21.541 42.75 21.667 ;
     RECT  43.668 21.643 54.27 21.667 ;
     RECT  6.228 21.667 14.526 21.695 ;
     RECT  12.6 21.695 14.526 21.775 ;
     RECT  24.015 20.759 26.946 21.775 ;
     RECT  27.756 21.569 30.402 21.775 ;
     RECT  4.608 21.119 5.166 21.811 ;
     RECT  20.196 21.425 22.842 21.811 ;
     RECT  24.015 21.775 30.402 21.811 ;
     RECT  6.228 21.695 11.502 21.929 ;
     RECT  31.176 21.389 32.742 21.929 ;
     RECT  55.116 21.631 62.514 21.937 ;
     RECT  6.228 21.929 8.262 21.965 ;
     RECT  9.072 21.929 11.502 21.965 ;
     RECT  20.196 21.811 30.402 21.965 ;
     RECT  33.48 21.425 37.494 21.965 ;
     RECT  38.232 21.667 54.27 21.965 ;
     RECT  33.48 21.965 36.198 22.001 ;
     RECT  4.608 21.811 5.238 22.037 ;
     RECT  53.46 21.965 54.27 22.081 ;
     RECT  55.008 21.937 62.514 22.081 ;
     RECT  12.6 21.775 14.742 22.165 ;
     RECT  15.48 21.425 17.694 22.165 ;
     RECT  6.228 21.965 8.097 22.171 ;
     RECT  4.608 22.037 5.13 22.199 ;
     RECT  33.48 22.001 33.894 22.199 ;
     RECT  38.232 21.965 52.11 22.199 ;
     RECT  12.6 22.165 17.694 22.219 ;
     RECT  18.468 21.425 18.897 22.219 ;
     RECT  12.6 22.219 18.897 22.235 ;
     RECT  12.852 22.235 18.897 22.243 ;
     RECT  38.232 22.199 51.93 22.271 ;
     RECT  47.304 22.271 51.93 22.307 ;
     RECT  6.12 22.171 8.097 22.315 ;
     RECT  2.415 21.191 3.762 22.351 ;
     RECT  4.608 22.199 5.022 22.351 ;
     RECT  27.324 21.965 30.402 22.351 ;
     RECT  31.176 21.929 32.706 22.351 ;
     RECT  9.108 21.965 11.502 22.441 ;
     RECT  53.46 22.081 62.514 22.469 ;
     RECT  6.084 22.315 8.097 22.477 ;
     RECT  9.108 22.441 11.898 22.493 ;
     RECT  12.852 22.243 19.17 22.505 ;
     RECT  36.972 21.965 37.494 22.585 ;
     RECT  38.232 22.271 46.53 22.585 ;
     RECT  36.972 22.585 46.53 22.589 ;
     RECT  13.068 22.505 19.17 22.613 ;
     RECT  53.46 22.469 60.21 22.613 ;
     RECT  9.108 22.493 11.646 22.711 ;
     RECT  27.324 22.351 32.706 22.711 ;
     RECT  9.036 22.711 11.646 22.739 ;
     RECT  9.036 22.739 11.502 22.775 ;
     RECT  53.46 22.613 55.35 22.811 ;
     RECT  16.488 22.613 19.17 22.847 ;
     RECT  2.415 22.351 5.022 22.891 ;
     RECT  34.632 22.001 36.198 22.891 ;
     RECT  36.972 22.589 43.038 22.891 ;
     RECT  2.376 22.891 5.022 22.981 ;
     RECT  5.94 22.477 8.097 22.981 ;
     RECT  47.448 22.307 51.93 23.009 ;
     RECT  60.984 22.469 62.514 23.009 ;
     RECT  34.632 22.891 43.038 23.045 ;
     RECT  53.46 22.811 54.27 23.089 ;
     RECT  20.196 21.965 26.55 23.125 ;
     RECT  33.624 22.199 33.714 23.125 ;
     RECT  34.632 23.045 36.954 23.125 ;
     RECT  43.848 22.589 46.53 23.125 ;
     RECT  27.324 22.711 32.886 23.153 ;
     RECT  47.988 23.009 51.93 23.161 ;
     RECT  53.064 23.089 54.27 23.161 ;
     RECT  56.088 22.613 60.21 23.165 ;
     RECT  60.984 23.009 62.37 23.189 ;
     RECT  2.376 22.981 8.097 23.251 ;
     RECT  13.068 22.613 15.642 23.279 ;
     RECT  37.872 23.045 43.038 23.279 ;
     RECT  13.068 23.279 15.534 23.287 ;
     RECT  16.524 22.847 19.17 23.287 ;
     RECT  19.944 23.125 26.55 23.287 ;
     RECT  13.032 23.287 15.534 23.315 ;
     RECT  40.032 23.279 43.038 23.323 ;
     RECT  43.848 23.125 47.25 23.323 ;
     RECT  28.404 23.153 32.886 23.371 ;
     RECT  33.624 23.125 36.954 23.371 ;
     RECT  2.376 23.251 8.262 23.423 ;
     RECT  9.036 22.775 11.178 23.521 ;
     RECT  2.376 23.423 6.714 23.549 ;
     RECT  7.56 23.423 8.262 23.549 ;
     RECT  13.032 23.315 15.39 23.549 ;
     RECT  40.032 23.323 47.25 23.549 ;
     RECT  13.032 23.549 14.238 23.557 ;
     RECT  12.924 23.557 14.238 23.585 ;
     RECT  16.524 23.287 26.55 23.585 ;
     RECT  55.044 22.811 55.35 23.593 ;
     RECT  56.088 23.165 59.814 23.593 ;
     RECT  28.404 23.371 36.954 23.621 ;
     RECT  9.036 23.521 11.466 23.665 ;
     RECT  47.988 23.161 54.27 23.665 ;
     RECT  60.984 23.189 62.298 23.665 ;
     RECT  37.872 23.279 39.258 23.693 ;
     RECT  21.42 23.585 26.55 23.701 ;
     RECT  27.324 23.153 27.594 23.701 ;
     RECT  28.404 23.621 35.226 23.729 ;
     RECT  16.524 23.585 20.214 23.791 ;
     RECT  36.072 23.621 36.954 23.791 ;
     RECT  37.872 23.693 39.15 23.791 ;
     RECT  12.924 23.585 14.13 23.851 ;
     RECT  16.452 23.791 20.214 23.855 ;
     RECT  28.404 23.729 35.19 23.885 ;
     RECT  55.044 23.593 59.814 23.885 ;
     RECT  8.82 23.665 11.466 23.891 ;
     RECT  28.404 23.885 32.274 23.891 ;
     RECT  21.42 23.701 27.594 23.899 ;
     RECT  28.404 23.891 32.13 23.899 ;
     RECT  16.452 23.855 16.47 23.927 ;
     RECT  21.42 23.899 32.13 23.963 ;
     RECT  40.032 23.549 42.21 23.963 ;
     RECT  47.988 23.665 54.306 23.971 ;
     RECT  55.044 23.885 57.654 23.971 ;
     RECT  58.428 23.885 59.814 23.971 ;
     RECT  60.84 23.665 62.298 23.971 ;
     RECT  40.14 23.963 42.21 23.981 ;
     RECT  25.02 23.963 32.13 24.089 ;
     RECT  12.744 23.851 14.13 24.169 ;
     RECT  2.376 23.549 6.678 24.205 ;
     RECT  15.156 23.549 15.39 24.205 ;
     RECT  25.02 24.089 32.058 24.269 ;
     RECT  17.208 23.855 20.214 24.359 ;
     RECT  27.036 24.269 32.058 24.359 ;
     RECT  47.988 23.971 57.654 24.395 ;
     RECT  10.98 23.891 11.466 24.413 ;
     RECT  17.352 24.359 20.214 24.431 ;
     RECT  7.56 23.549 8.097 24.475 ;
     RECT  8.82 23.891 10.206 24.475 ;
     RECT  12.6 24.169 14.13 24.475 ;
     RECT  21.42 23.963 24.297 24.475 ;
     RECT  33.084 23.885 35.19 24.475 ;
     RECT  36.072 23.791 39.15 24.475 ;
     RECT  33.084 24.475 39.15 24.511 ;
     RECT  2.34 24.205 6.678 24.571 ;
     RECT  7.56 24.475 10.206 24.571 ;
     RECT  41.4 23.981 42.21 24.601 ;
     RECT  43.02 23.549 47.25 24.601 ;
     RECT  11.448 24.413 11.466 24.629 ;
     RECT  47.988 24.395 52.938 24.629 ;
     RECT  12.6 24.475 14.166 24.665 ;
     RECT  2.34 24.571 10.206 24.673 ;
     RECT  15.156 24.205 16.11 24.709 ;
     RECT  40.14 23.981 40.554 24.709 ;
     RECT  58.428 23.971 62.298 24.709 ;
     RECT  21.204 24.475 24.297 24.745 ;
     RECT  25.02 24.269 26.226 24.745 ;
     RECT  33.084 24.511 39.222 24.745 ;
     RECT  40.032 24.709 40.554 24.745 ;
     RECT  41.4 24.601 47.25 24.745 ;
     RECT  47.988 24.629 52.614 24.745 ;
     RECT  15.156 24.709 16.47 24.781 ;
     RECT  53.712 24.395 57.654 24.781 ;
     RECT  58.428 24.709 62.442 24.781 ;
     RECT  12.816 24.665 14.166 24.871 ;
     RECT  15.048 24.781 16.47 24.871 ;
     RECT  28.368 24.359 32.058 24.871 ;
     RECT  33.084 24.745 40.554 24.871 ;
     RECT  41.4 24.745 52.614 24.871 ;
     RECT  12.816 24.871 16.47 24.899 ;
     RECT  2.34 24.673 10.242 24.971 ;
     RECT  33.084 24.871 52.614 25.007 ;
     RECT  21.204 24.745 26.226 25.015 ;
     RECT  27.036 24.359 27.45 25.037 ;
     RECT  28.368 24.871 32.238 25.051 ;
     RECT  33.084 25.007 49.122 25.051 ;
     RECT  28.368 25.051 49.122 25.079 ;
     RECT  39.852 25.079 49.122 25.085 ;
     RECT  21.132 25.015 26.226 25.099 ;
     RECT  2.415 24.971 10.242 25.141 ;
     RECT  28.368 25.079 39.078 25.169 ;
     RECT  53.712 24.781 62.442 25.213 ;
     RECT  27.576 25.177 27.594 25.249 ;
     RECT  28.368 25.169 30.222 25.249 ;
     RECT  2.415 25.141 10.458 25.285 ;
     RECT  53.604 25.213 62.442 25.313 ;
     RECT  17.424 24.431 20.214 25.321 ;
     RECT  21.132 25.099 26.658 25.321 ;
     RECT  17.388 25.321 26.658 25.439 ;
     RECT  17.388 25.439 26.37 25.447 ;
     RECT  17.352 25.447 26.37 25.475 ;
     RECT  27.576 25.249 30.222 25.511 ;
     RECT  2.415 25.285 10.926 25.519 ;
     RECT  17.352 25.475 19.926 25.555 ;
     RECT  20.808 25.475 22.734 25.619 ;
     RECT  23.76 25.475 24.354 25.619 ;
     RECT  49.896 25.007 52.614 25.619 ;
     RECT  12.816 24.899 15.426 25.717 ;
     RECT  12.564 25.717 15.426 25.753 ;
     RECT  50.184 25.619 52.614 25.753 ;
     RECT  53.604 25.313 58.194 25.753 ;
     RECT  2.415 25.519 11.178 25.789 ;
     RECT  2.376 25.789 11.178 25.825 ;
     RECT  31.176 25.169 39.078 25.825 ;
     RECT  39.852 25.085 49.086 25.825 ;
     RECT  23.94 25.619 24.354 25.853 ;
     RECT  12.564 25.753 15.498 25.861 ;
     RECT  16.452 24.899 16.47 25.861 ;
     RECT  17.316 25.555 19.926 25.861 ;
     RECT  21.312 25.619 22.734 25.889 ;
     RECT  2.376 25.825 11.214 25.979 ;
     RECT  21.312 25.889 22.482 25.979 ;
     RECT  27.576 25.511 27.594 25.987 ;
     RECT  31.176 25.825 49.086 26.015 ;
     RECT  9.432 25.979 11.214 26.051 ;
     RECT  12.564 25.861 19.926 26.051 ;
     RECT  50.184 25.753 58.194 26.131 ;
     RECT  58.932 25.313 62.442 26.131 ;
     RECT  17.172 26.051 19.926 26.203 ;
     RECT  9.684 26.051 11.214 26.257 ;
     RECT  9.684 26.257 11.754 26.285 ;
     RECT  27.468 25.987 27.594 26.329 ;
     RECT  28.404 25.511 30.222 26.329 ;
     RECT  31.176 26.015 33.21 26.329 ;
     RECT  24.015 25.853 24.354 26.365 ;
     RECT  25.092 25.475 26.37 26.365 ;
     RECT  24.015 26.365 26.37 26.401 ;
     RECT  33.948 26.015 49.086 26.401 ;
     RECT  50.184 26.131 62.442 26.429 ;
     RECT  24.015 26.401 26.73 26.491 ;
     RECT  27.468 26.329 30.222 26.491 ;
     RECT  33.948 26.401 49.158 26.491 ;
     RECT  12.564 26.051 16.002 26.519 ;
     RECT  53.64 26.429 62.442 26.519 ;
     RECT  24.015 26.491 30.222 26.527 ;
     RECT  31.14 26.329 33.21 26.527 ;
     RECT  9.72 26.285 11.754 26.563 ;
     RECT  12.564 26.519 15.498 26.563 ;
     RECT  21.348 25.979 22.482 26.635 ;
     RECT  23.22 26.401 23.238 26.635 ;
     RECT  53.64 26.519 62.298 26.699 ;
     RECT  17.172 26.203 20.034 26.731 ;
     RECT  21.348 26.635 23.238 26.761 ;
     RECT  24.015 26.527 33.21 26.761 ;
     RECT  33.948 26.491 49.302 26.761 ;
     RECT  50.184 26.429 52.866 26.761 ;
     RECT  9.72 26.563 15.498 26.789 ;
     RECT  17.172 26.731 20.43 26.789 ;
     RECT  21.348 26.761 52.866 26.789 ;
     RECT  2.376 25.979 8.658 26.797 ;
     RECT  17.172 26.789 20.25 26.933 ;
     RECT  27.288 26.789 40.986 27.059 ;
     RECT  2.376 26.797 8.802 27.067 ;
     RECT  9.72 26.789 15.318 27.067 ;
     RECT  27.288 27.059 31.986 27.095 ;
     RECT  2.376 27.067 15.318 27.131 ;
     RECT  16.488 26.941 16.578 27.307 ;
     RECT  53.64 26.699 58.158 27.307 ;
     RECT  32.868 27.059 40.842 27.329 ;
     RECT  41.76 26.789 52.866 27.329 ;
     RECT  41.76 27.329 43.038 27.365 ;
     RECT  16.416 27.307 16.578 27.481 ;
     RECT  21.348 26.789 26.334 27.481 ;
     RECT  43.776 27.329 52.866 27.481 ;
     RECT  53.604 27.307 58.158 27.481 ;
     RECT  58.968 26.699 62.298 27.481 ;
     RECT  17.316 26.933 20.25 27.679 ;
     RECT  21.24 27.481 26.334 27.679 ;
     RECT  27.288 27.095 31.518 27.679 ;
     RECT  6.084 27.131 15.318 27.715 ;
     RECT  16.236 27.481 16.578 27.715 ;
     RECT  6.084 27.715 16.578 27.751 ;
     RECT  17.316 27.679 20.466 27.751 ;
     RECT  43.776 27.481 62.298 27.751 ;
     RECT  43.776 27.751 62.442 27.779 ;
     RECT  39.06 27.329 40.842 27.841 ;
     RECT  41.76 27.365 42.75 27.841 ;
     RECT  21.24 27.679 31.518 27.875 ;
     RECT  6.084 27.751 20.466 27.905 ;
     RECT  2.376 27.131 5.31 27.917 ;
     RECT  21.6 27.875 31.518 27.985 ;
     RECT  6.156 27.905 20.466 28.021 ;
     RECT  6.156 28.021 20.718 28.049 ;
     RECT  52.308 27.779 62.442 28.049 ;
     RECT  17.64 28.049 20.718 28.061 ;
     RECT  43.776 27.779 51.297 28.111 ;
     RECT  21.6 27.985 31.698 28.139 ;
     RECT  32.868 27.329 38.322 28.147 ;
     RECT  2.376 27.917 3.798 28.175 ;
     RECT  22.14 28.139 31.698 28.175 ;
     RECT  2.376 28.175 3.618 28.211 ;
     RECT  39.06 27.841 42.75 28.291 ;
     RECT  43.596 28.111 51.297 28.291 ;
     RECT  32.724 28.147 38.322 28.319 ;
     RECT  17.64 28.061 20.646 28.409 ;
     RECT  52.344 28.049 62.442 28.445 ;
     RECT  36.9 28.319 38.322 28.453 ;
     RECT  39.06 28.291 51.297 28.453 ;
     RECT  6.156 28.049 16.902 28.493 ;
     RECT  22.14 28.175 28.17 28.553 ;
     RECT  52.344 28.445 55.602 28.553 ;
     RECT  4.68 27.917 5.31 28.561 ;
     RECT  28.944 28.175 31.698 28.561 ;
     RECT  32.724 28.319 35.946 28.561 ;
     RECT  12.708 28.493 16.902 28.679 ;
     RECT  22.14 28.553 25.794 28.679 ;
     RECT  28.944 28.561 31.806 28.679 ;
     RECT  32.58 28.561 35.946 28.679 ;
     RECT  36.9 28.453 51.297 28.715 ;
     RECT  52.38 28.553 55.602 28.823 ;
     RECT  4.68 28.561 5.418 28.831 ;
     RECT  26.604 28.553 28.17 28.921 ;
     RECT  28.944 28.679 30.69 28.921 ;
     RECT  13.215 28.679 16.902 28.949 ;
     RECT  22.14 28.679 23.058 28.949 ;
     RECT  32.58 28.679 33.138 28.949 ;
     RECT  32.58 28.949 32.994 28.985 ;
     RECT  52.416 28.823 55.602 28.985 ;
     RECT  32.976 28.985 32.994 29.021 ;
     RECT  4.428 28.831 5.418 29.029 ;
     RECT  6.156 28.493 11.97 29.029 ;
     RECT  33.948 28.679 35.946 29.065 ;
     RECT  4.428 29.029 11.97 29.101 ;
     RECT  16.776 28.949 16.902 29.101 ;
     RECT  17.64 28.409 20.574 29.101 ;
     RECT  31.464 28.679 31.806 29.101 ;
     RECT  36.9 28.715 38.646 29.101 ;
     RECT  2.415 28.211 3.618 29.191 ;
     RECT  4.392 29.101 11.97 29.191 ;
     RECT  16.776 29.101 20.574 29.191 ;
     RECT  33.948 29.065 36.054 29.191 ;
     RECT  36.792 29.101 38.646 29.191 ;
     RECT  33.948 29.191 38.646 29.255 ;
     RECT  16.776 29.191 20.826 29.263 ;
     RECT  26.604 28.921 30.69 29.291 ;
     RECT  34.02 29.255 38.646 29.291 ;
     RECT  2.415 29.191 11.97 29.335 ;
     RECT  16.776 29.263 21.006 29.335 ;
     RECT  52.452 28.985 55.602 29.335 ;
     RECT  56.34 28.445 62.442 29.335 ;
     RECT  34.02 29.291 35.37 29.363 ;
     RECT  16.776 29.335 21.042 29.371 ;
     RECT  24.015 28.679 25.794 29.371 ;
     RECT  16.776 29.371 21.222 29.419 ;
     RECT  26.784 29.291 30.69 29.461 ;
     RECT  31.464 29.101 31.878 29.461 ;
     RECT  36.144 29.291 38.646 29.461 ;
     RECT  39.42 28.715 51.297 29.461 ;
     RECT  16.776 29.419 21.546 29.489 ;
     RECT  24.015 29.371 25.83 29.489 ;
     RECT  34.056 29.363 35.37 29.525 ;
     RECT  34.56 29.525 35.37 29.561 ;
     RECT  26.784 29.461 31.878 29.597 ;
     RECT  22.284 28.949 23.058 29.605 ;
     RECT  52.452 29.335 62.442 29.605 ;
     RECT  2.34 29.335 11.97 29.611 ;
     RECT  13.215 28.949 16.002 29.611 ;
     RECT  24.015 29.489 25.254 29.633 ;
     RECT  36.144 29.461 51.354 29.669 ;
     RECT  2.34 29.611 16.002 29.731 ;
     RECT  52.452 29.605 62.514 29.795 ;
     RECT  2.34 29.731 16.038 29.803 ;
     RECT  16.776 29.489 21.474 29.803 ;
     RECT  55.224 29.795 62.514 29.867 ;
     RECT  22.284 29.605 23.094 29.875 ;
     RECT  31.356 29.597 31.878 29.875 ;
     RECT  52.452 29.795 54.198 29.875 ;
     RECT  39.888 29.669 51.354 29.903 ;
     RECT  24.015 29.633 25.146 29.911 ;
     RECT  31.356 29.875 32.13 29.911 ;
     RECT  31.356 29.911 32.382 29.995 ;
     RECT  39.888 29.903 49.482 30.065 ;
     RECT  26.784 29.597 30.51 30.073 ;
     RECT  31.356 29.995 32.454 30.077 ;
     RECT  39.888 30.065 46.818 30.101 ;
     RECT  59.832 29.867 62.514 30.137 ;
     RECT  31.5 30.077 32.454 30.145 ;
     RECT  26.244 30.073 30.51 30.173 ;
     RECT  39.888 30.101 44.226 30.179 ;
     RECT  39.888 30.179 44.19 30.209 ;
     RECT  27.324 30.173 30.51 30.299 ;
     RECT  50.4 29.903 51.354 30.307 ;
     RECT  52.236 29.875 54.198 30.307 ;
     RECT  60.804 30.137 62.514 30.335 ;
     RECT  34.776 29.561 35.37 30.343 ;
     RECT  2.34 29.803 21.474 30.379 ;
     RECT  22.212 29.875 23.094 30.379 ;
     RECT  26.244 30.173 26.586 30.379 ;
     RECT  31.5 30.145 33.102 30.415 ;
     RECT  2.34 30.379 23.094 30.451 ;
     RECT  23.976 29.911 25.146 30.451 ;
     RECT  26.028 30.379 26.586 30.451 ;
     RECT  34.2 30.343 35.37 30.451 ;
     RECT  36.144 29.669 39.15 30.451 ;
     RECT  39.888 30.209 43.83 30.451 ;
     RECT  55.224 29.867 58.914 30.479 ;
     RECT  2.34 30.451 23.13 30.605 ;
     RECT  47.628 30.065 49.482 30.667 ;
     RECT  50.4 30.307 54.198 30.667 ;
     RECT  31.5 30.415 33.462 30.721 ;
     RECT  34.2 30.451 43.83 30.721 ;
     RECT  47.628 30.667 54.198 30.721 ;
     RECT  55.224 30.479 55.386 30.721 ;
     RECT  59.832 30.137 60.03 30.721 ;
     RECT  47.628 30.721 55.386 30.797 ;
     RECT  47.808 30.797 55.386 30.839 ;
     RECT  2.415 30.605 23.13 30.883 ;
     RECT  23.976 30.451 26.586 30.883 ;
     RECT  2.415 30.883 26.586 30.911 ;
     RECT  59.76 30.721 60.03 30.941 ;
     RECT  44.964 30.101 46.818 30.991 ;
     RECT  56.124 30.479 58.914 30.991 ;
     RECT  60.804 30.335 62.226 30.991 ;
     RECT  2.415 30.911 15.642 31.019 ;
     RECT  16.74 30.911 26.586 31.019 ;
     RECT  44.748 30.991 46.818 31.109 ;
     RECT  19.656 31.019 26.586 31.117 ;
     RECT  27.324 30.299 30.438 31.117 ;
     RECT  19.656 31.117 30.438 31.153 ;
     RECT  31.5 30.721 43.83 31.153 ;
     RECT  19.656 31.153 43.83 31.225 ;
     RECT  44.748 31.109 46.674 31.225 ;
     RECT  60.768 30.991 62.226 31.225 ;
     RECT  19.656 31.225 46.674 31.253 ;
     RECT  53.1 30.839 55.386 31.261 ;
     RECT  56.124 30.991 59.526 31.261 ;
     RECT  47.808 30.839 52.362 31.289 ;
     RECT  19.656 31.253 24.786 31.379 ;
     RECT  25.524 31.253 46.674 31.565 ;
     RECT  16.74 31.019 18.897 31.693 ;
     RECT  53.1 31.261 59.526 31.729 ;
     RECT  60.444 31.225 62.226 31.729 ;
     RECT  16.524 31.693 18.897 31.801 ;
     RECT  47.808 31.289 50.058 31.801 ;
     RECT  25.524 31.565 42.318 31.829 ;
     RECT  50.976 31.289 52.362 31.891 ;
     RECT  53.1 31.729 62.226 31.891 ;
     RECT  43.164 31.565 46.674 31.901 ;
     RECT  2.415 31.019 15.462 32.035 ;
     RECT  16.308 31.801 18.897 32.035 ;
     RECT  50.976 31.891 62.226 32.035 ;
     RECT  25.56 31.829 42.318 32.099 ;
     RECT  2.415 32.035 18.897 32.189 ;
     RECT  47.628 31.801 50.058 32.189 ;
     RECT  50.976 32.035 62.298 32.189 ;
     RECT  47.664 32.189 50.058 32.297 ;
     RECT  4.32 32.189 18.897 32.305 ;
     RECT  19.764 31.379 24.786 32.305 ;
     RECT  36.396 32.099 42.318 32.305 ;
     RECT  43.164 31.901 46.602 32.305 ;
     RECT  47.7 32.297 50.058 32.341 ;
     RECT  4.32 32.305 24.786 32.459 ;
     RECT  50.976 32.189 62.097 32.459 ;
     RECT  47.7 32.341 50.166 32.611 ;
     RECT  50.976 32.459 59.238 32.611 ;
     RECT  19.944 32.459 24.786 32.701 ;
     RECT  25.56 32.099 35.37 32.701 ;
     RECT  36.396 32.305 46.602 32.701 ;
     RECT  19.944 32.701 35.37 32.765 ;
     RECT  4.32 32.459 18.897 32.801 ;
     RECT  19.98 32.765 35.37 32.837 ;
     RECT  2.415 32.189 3.582 32.971 ;
     RECT  4.32 32.801 15.246 32.971 ;
     RECT  20.052 32.837 35.37 32.971 ;
     RECT  36.396 32.701 46.71 33.043 ;
     RECT  47.7 32.611 59.238 33.053 ;
     RECT  20.052 32.971 35.658 33.067 ;
     RECT  36.396 33.043 46.746 33.067 ;
     RECT  2.415 32.971 15.246 33.101 ;
     RECT  47.7 33.053 50.166 33.151 ;
     RECT  11.988 33.101 15.246 33.179 ;
     RECT  2.415 33.101 11.25 33.269 ;
     RECT  20.052 33.067 46.746 33.277 ;
     RECT  47.664 33.151 50.166 33.277 ;
     RECT  20.052 33.277 50.166 33.413 ;
     RECT  50.976 33.053 59.238 33.421 ;
     RECT  60.012 32.459 62.097 33.421 ;
     RECT  11.988 33.179 14.202 33.575 ;
     RECT  20.052 33.413 41.13 33.655 ;
     RECT  14.94 33.179 15.246 33.691 ;
     RECT  16.092 32.801 18.897 33.691 ;
     RECT  19.908 33.655 41.13 33.719 ;
     RECT  19.908 33.719 30.798 33.817 ;
     RECT  19.836 33.817 30.798 33.835 ;
     RECT  31.68 33.719 41.13 33.845 ;
     RECT  42.012 33.413 50.166 33.889 ;
     RECT  50.976 33.421 62.097 33.889 ;
     RECT  11.988 33.575 13.878 33.925 ;
     RECT  42.012 33.889 62.097 33.961 ;
     RECT  14.94 33.691 18.897 34.051 ;
     RECT  19.764 33.835 30.798 34.051 ;
     RECT  42.012 33.961 62.298 34.079 ;
     RECT  42.012 34.079 54.018 34.115 ;
     RECT  54.936 34.079 62.298 34.115 ;
     RECT  42.12 34.115 54.018 34.223 ;
     RECT  54.936 34.115 62.19 34.385 ;
     RECT  2.415 33.269 10.926 34.429 ;
     RECT  11.844 33.925 13.878 34.429 ;
     RECT  31.68 33.845 40.698 34.465 ;
     RECT  2.415 34.429 13.878 34.501 ;
     RECT  14.94 34.051 30.798 34.501 ;
     RECT  2.415 34.501 30.798 34.591 ;
     RECT  31.608 34.465 40.698 34.591 ;
     RECT  2.415 34.591 40.698 34.961 ;
     RECT  23.58 34.961 40.698 34.969 ;
     RECT  42.156 34.223 54.018 35.041 ;
     RECT  55.116 34.385 62.19 35.041 ;
     RECT  23.58 34.969 40.842 35.195 ;
     RECT  23.976 35.195 40.842 35.269 ;
     RECT  41.652 35.041 54.018 35.269 ;
     RECT  23.976 35.269 54.018 35.275 ;
     RECT  23.976 35.275 54.198 35.309 ;
     RECT  42.192 35.309 54.198 35.311 ;
     RECT  55.116 35.041 62.262 35.311 ;
     RECT  23.976 35.309 41.31 35.429 ;
     RECT  2.415 34.961 22.662 35.465 ;
     RECT  23.976 35.429 29.697 35.573 ;
     RECT  25.308 35.573 29.697 35.699 ;
     RECT  14.832 35.465 22.662 35.815 ;
     RECT  25.416 35.699 29.697 35.843 ;
     RECT  42.192 35.311 62.262 35.969 ;
     RECT  42.192 35.969 46.818 36.029 ;
     RECT  30.636 35.429 41.31 36.049 ;
     RECT  47.592 35.969 62.262 36.077 ;
     RECT  14.832 35.815 23.13 36.085 ;
     RECT  23.976 35.573 24.534 36.085 ;
     RECT  14.832 36.085 24.534 36.149 ;
     RECT  2.415 35.465 14.022 36.211 ;
     RECT  14.832 36.149 21.222 36.211 ;
     RECT  2.415 36.211 21.222 36.275 ;
     RECT  30.636 36.049 41.454 36.275 ;
     RECT  32.58 36.275 41.454 36.355 ;
     RECT  42.192 36.029 46.782 36.355 ;
     RECT  27.972 35.843 29.697 36.419 ;
     RECT  30.636 36.275 31.518 36.419 ;
     RECT  28.548 36.419 29.697 36.481 ;
     RECT  25.416 35.843 27.126 36.509 ;
     RECT  28.548 36.481 29.79 36.553 ;
     RECT  30.636 36.419 31.482 36.553 ;
     RECT  49.32 36.077 62.262 36.553 ;
     RECT  21.996 36.149 24.534 36.661 ;
     RECT  25.416 36.509 25.65 36.661 ;
     RECT  21.996 36.661 25.65 36.701 ;
     RECT  26.388 36.509 27.126 36.779 ;
     RECT  49.32 36.553 62.37 36.779 ;
     RECT  26.46 36.779 27.126 36.823 ;
     RECT  47.916 36.077 48.546 36.931 ;
     RECT  49.32 36.779 62.334 36.931 ;
     RECT  32.58 36.355 46.782 37.021 ;
     RECT  47.52 36.931 62.334 37.021 ;
     RECT  32.58 37.021 62.334 37.049 ;
     RECT  17.676 36.275 21.222 37.051 ;
     RECT  21.996 36.701 24.606 37.051 ;
     RECT  32.58 37.049 62.298 37.121 ;
     RECT  2.415 36.275 16.794 37.165 ;
     RECT  32.58 37.121 41.886 37.165 ;
     RECT  26.46 36.823 27.342 37.201 ;
     RECT  26.46 37.201 27.702 37.363 ;
     RECT  28.548 36.553 31.482 37.363 ;
     RECT  26.46 37.363 31.482 37.435 ;
     RECT  25.38 36.701 25.65 37.561 ;
     RECT  26.46 37.435 31.77 37.561 ;
     RECT  25.38 37.561 31.77 37.589 ;
     RECT  32.508 37.165 41.886 37.589 ;
     RECT  42.84 37.121 62.298 37.589 ;
     RECT  33.192 37.589 41.886 37.625 ;
     RECT  17.676 37.051 24.606 37.633 ;
     RECT  56.16 37.589 62.298 37.661 ;
     RECT  17.568 37.633 24.606 37.669 ;
     RECT  25.38 37.589 30.834 37.669 ;
     RECT  2.415 37.165 16.83 37.741 ;
     RECT  17.568 37.669 30.834 37.741 ;
     RECT  31.644 37.589 31.77 37.859 ;
     RECT  33.372 37.625 41.886 37.867 ;
     RECT  42.84 37.589 55.17 38.129 ;
     RECT  31.86 38.137 31.878 38.189 ;
     RECT  33.372 37.867 42.066 38.209 ;
     RECT  42.84 38.129 44.046 38.209 ;
     RECT  33.372 38.209 44.046 38.237 ;
     RECT  33.372 38.237 41.418 38.371 ;
     RECT  2.415 37.741 30.834 38.399 ;
     RECT  20.16 38.399 30.834 38.435 ;
     RECT  20.16 38.435 28.494 38.471 ;
     RECT  44.964 38.129 55.17 38.539 ;
     RECT  33.336 38.371 41.418 38.551 ;
     RECT  56.16 37.661 62.19 38.551 ;
     RECT  42.444 38.237 44.046 38.621 ;
     RECT  33.12 38.551 41.418 38.641 ;
     RECT  44.964 38.539 55.35 38.641 ;
     RECT  56.16 38.551 62.298 38.641 ;
     RECT  2.415 38.399 19.422 38.705 ;
     RECT  20.16 38.471 26.478 38.741 ;
     RECT  20.16 38.741 22.374 38.752 ;
     RECT  42.948 38.621 44.046 38.765 ;
     RECT  20.196 38.752 22.374 38.813 ;
     RECT  44.964 38.641 62.298 38.821 ;
     RECT  43.452 38.765 44.046 38.911 ;
     RECT  44.964 38.821 62.406 38.939 ;
     RECT  29.268 38.435 30.834 38.947 ;
     RECT  59.076 38.939 62.406 39.091 ;
     RECT  43.452 38.911 44.19 39.163 ;
     RECT  44.964 38.939 58.158 39.163 ;
     RECT  27.36 38.471 28.494 39.181 ;
     RECT  29.268 38.947 31.014 39.181 ;
     RECT  2.415 38.705 15.786 39.217 ;
     RECT  31.932 38.641 41.418 39.217 ;
     RECT  31.932 39.217 41.634 39.293 ;
     RECT  34.2 39.293 41.634 39.353 ;
     RECT  23.22 38.741 26.478 39.355 ;
     RECT  27.36 39.181 31.014 39.361 ;
     RECT  31.932 39.293 33.426 39.361 ;
     RECT  17.028 38.705 19.422 39.451 ;
     RECT  27.36 39.361 33.426 39.479 ;
     RECT  43.452 39.163 58.158 39.487 ;
     RECT  37.224 39.353 41.634 39.523 ;
     RECT  42.552 39.361 42.606 39.523 ;
     RECT  16.812 39.451 19.422 39.595 ;
     RECT  20.412 38.813 22.374 39.595 ;
     RECT  16.812 39.595 22.374 39.631 ;
     RECT  23.22 39.355 26.55 39.631 ;
     RECT  37.224 39.523 42.606 39.659 ;
     RECT  38.772 39.659 42.606 39.721 ;
     RECT  43.416 39.487 58.158 39.721 ;
     RECT  38.772 39.721 58.158 39.739 ;
     RECT  59.076 39.091 62.442 39.739 ;
     RECT  16.812 39.631 27.162 39.749 ;
     RECT  2.376 39.217 15.786 39.773 ;
     RECT  16.812 39.749 27.09 39.773 ;
     RECT  38.772 39.739 62.442 39.857 ;
     RECT  2.415 39.773 15.786 39.865 ;
     RECT  16.812 39.773 26.55 39.865 ;
     RECT  52.272 39.857 62.442 39.865 ;
     RECT  34.2 39.353 36.27 39.893 ;
     RECT  52.272 39.865 62.514 39.917 ;
     RECT  27.936 39.479 33.426 40.027 ;
     RECT  34.2 39.893 36.198 40.027 ;
     RECT  2.415 39.865 26.55 40.091 ;
     RECT  52.344 39.917 62.514 40.091 ;
     RECT  17.1 40.091 26.55 40.163 ;
     RECT  2.415 40.091 16.254 40.199 ;
     RECT  3.456 40.199 16.254 40.289 ;
     RECT  52.344 40.091 62.442 40.289 ;
     RECT  37.224 39.659 38.034 40.297 ;
     RECT  52.344 40.289 62.298 40.325 ;
     RECT  37.008 40.297 38.034 40.361 ;
     RECT  27.936 40.027 36.198 40.405 ;
     RECT  38.772 39.857 51.462 40.433 ;
     RECT  21.672 40.163 26.55 40.531 ;
     RECT  27.9 40.405 36.198 40.531 ;
     RECT  21.672 40.531 26.802 40.555 ;
     RECT  27.576 40.531 36.198 40.555 ;
     RECT  3.6 40.289 16.254 40.559 ;
     RECT  17.1 40.163 20.898 40.559 ;
     RECT  21.672 40.555 36.198 40.559 ;
     RECT  39.204 40.433 43.542 40.559 ;
     RECT  44.28 40.433 51.462 40.559 ;
     RECT  52.344 40.325 62.097 40.559 ;
     RECT  21.672 40.559 30.87 40.589 ;
     RECT  3.744 40.559 13.662 40.595 ;
     RECT  14.4 40.559 16.254 40.595 ;
     RECT  17.1 40.559 20.826 40.595 ;
     RECT  39.204 40.559 42.282 40.595 ;
     RECT  43.02 40.559 43.362 40.595 ;
     RECT  52.344 40.559 58.41 40.595 ;
     RECT  59.436 40.559 59.454 40.595 ;
     RECT  60.192 40.559 62.097 40.595 ;
     RECT  21.672 40.589 27.666 40.631 ;
     RECT  37.116 40.361 38.034 40.631 ;
     RECT  39.204 40.595 42.138 40.631 ;
     RECT  31.788 40.559 35.874 40.637 ;
     RECT  12.852 40.595 13.662 40.703 ;
     RECT  37.116 40.631 37.638 40.703 ;
     RECT  39.204 40.631 41.67 40.703 ;
     RECT  49.644 40.559 51.462 40.711 ;
     RECT  52.344 40.595 58.158 40.711 ;
     RECT  31.788 40.637 33.282 40.733 ;
     RECT  34.092 40.637 35.874 40.733 ;
     RECT  17.1 40.595 17.838 40.739 ;
     RECT  22.968 40.631 27.666 40.739 ;
     RECT  2.415 40.199 2.697 40.787 ;
     RECT  34.524 40.733 35.874 40.787 ;
     RECT  49.644 40.711 58.158 40.787 ;
     RECT  60.84 40.595 62.097 40.787 ;
     RECT  3.744 40.595 12.078 40.829 ;
     RECT  14.796 40.595 16.254 40.829 ;
     RECT  17.1 40.739 17.118 40.829 ;
     RECT  21.672 40.631 22.23 40.829 ;
     RECT  23.004 40.739 27.666 40.829 ;
     RECT  31.788 40.733 33.21 40.829 ;
     RECT  35.64 40.787 35.874 40.829 ;
     RECT  44.28 40.559 48.798 40.829 ;
     RECT  49.644 40.787 56.505 40.829 ;
     RECT  57.312 40.787 58.158 40.829 ;
     RECT  60.84 40.787 61.905 40.829 ;
     RECT  35.64 40.829 35.658 40.835 ;
     RECT  5.112 40.829 11.574 40.865 ;
     RECT  13.104 40.703 13.662 40.865 ;
     RECT  15.84 40.829 16.254 40.865 ;
     RECT  21.672 40.829 22.122 40.865 ;
     RECT  28.512 40.589 30.87 40.865 ;
     RECT  34.524 40.787 34.905 40.865 ;
     RECT  43.02 40.595 43.182 40.865 ;
     RECT  44.28 40.829 44.298 40.865 ;
     RECT  45.108 40.829 46.35 40.865 ;
     RECT  47.088 40.829 47.826 40.865 ;
     RECT  48.78 40.829 48.798 40.865 ;
     RECT  49.644 40.829 49.662 40.865 ;
     RECT  50.436 40.829 51.462 40.865 ;
     RECT  52.2 40.829 52.218 40.865 ;
     RECT  53.424 40.829 56.505 40.865 ;
     RECT  57.456 40.829 58.05 40.865 ;
     RECT  32.112 40.829 33.21 40.874 ;
     RECT  29.415 40.865 30.87 40.877 ;
     RECT  9.756 40.865 11.43 40.901 ;
     RECT  30.528 40.877 30.87 40.901 ;
     RECT  34.596 40.865 34.905 40.901 ;
     RECT  56.232 40.865 56.505 40.901 ;
     RECT  23.4 40.829 27.666 40.925 ;
     RECT  28.512 40.865 28.674 40.925 ;
     RECT  32.148 40.874 33.21 40.925 ;
     RECT  39.672 40.703 41.67 40.925 ;
     RECT  3.744 40.829 4.266 40.937 ;
     RECT  14.796 40.829 14.814 40.937 ;
     RECT  15.84 40.865 16.002 40.937 ;
     RECT  18.615 40.595 20.826 40.937 ;
     RECT  21.672 40.865 21.69 40.937 ;
     RECT  24.015 40.925 27.666 40.937 ;
     RECT  39.78 40.925 41.67 40.937 ;
     RECT  13.215 40.865 13.662 40.973 ;
     RECT  20.808 40.937 20.826 40.973 ;
     RECT  24.015 40.937 25.434 40.973 ;
     RECT  26.784 40.937 27.594 40.973 ;
     RECT  28.512 40.925 28.602 40.973 ;
     RECT  37.116 40.703 37.242 40.973 ;
     RECT  40.104 40.937 41.526 40.973 ;
     RECT  51.015 40.865 51.462 40.973 ;
     RECT  57.852 40.865 57.87 40.973 ;
     RECT  61.2 40.829 61.905 40.973 ;
     RECT  9.756 40.901 10.854 41.009 ;
     RECT  15.984 40.937 16.002 41.009 ;
     RECT  27.576 40.973 27.594 41.009 ;
     RECT  30.672 40.901 30.87 41.009 ;
     RECT  32.58 40.925 33.21 41.009 ;
     RECT  37.224 40.973 37.242 41.009 ;
     RECT  40.104 40.973 40.482 41.009 ;
     RECT  53.496 40.865 53.514 41.009 ;
     RECT  54.828 40.865 54.846 41.009 ;
     RECT  5.112 40.865 9.018 41.021 ;
     RECT  18.615 40.937 19.674 41.021 ;
     RECT  24.015 40.973 24.714 41.021 ;
     RECT  2.415 40.787 2.505 41.057 ;
     RECT  5.184 41.021 9.018 41.057 ;
     RECT  13.215 40.973 13.305 41.057 ;
     RECT  18.615 41.021 18.705 41.057 ;
     RECT  24.015 41.021 24.105 41.057 ;
     RECT  29.415 40.877 29.505 41.057 ;
     RECT  34.815 40.901 34.905 41.057 ;
     RECT  40.215 41.009 40.305 41.057 ;
     RECT  45.615 40.865 45.705 41.057 ;
     RECT  51.015 40.973 51.105 41.057 ;
     RECT  56.415 40.901 56.505 41.057 ;
     RECT  61.815 40.973 61.905 41.057 ;
     RECT  28.584 40.973 28.602 41.099 ;
     RECT  30.744 41.009 30.762 41.099 ;
     RECT  5.184 41.057 7.398 42.221 ;
     RECT  5.256 42.221 7.398 42.269 ;
     RECT  9.756 41.009 9.774 42.845 ;
     RECT  10.836 41.009 10.854 42.893 ;
     RECT  8.208 41.057 9.018 42.941 ;
     RECT  5.292 42.269 7.398 43.037 ;
     RECT  8.316 42.941 9.018 43.037 ;
     RECT  3.744 40.937 3.762 43.085 ;
     RECT  5.292 43.037 5.922 43.085 ;
     RECT  6.876 43.037 7.146 43.085 ;
     RECT  8.316 43.037 8.334 43.085 ;
    LAYER M4 ;
     RECT  0.06 4.032 0.227 5.016 ;
     RECT  2.365 3.024 2.408 3.048 ;
     RECT  0.227 4.992 2.408 5.016 ;
     RECT  0.181 21.456 2.408 21.48 ;
     RECT  2.365 27.888 2.408 27.912 ;
     RECT  2.365 39.744 2.408 39.768 ;
     RECT  2.408 2.148 2.512 41.052 ;
     RECT  2.512 2.418 2.704 40.782 ;
     RECT  2.704 13.632 3.017 14.424 ;
     RECT  2.704 33.168 3.233 35.928 ;
     RECT  2.704 15.696 3.443 18.552 ;
     RECT  3.443 18.192 3.449 18.552 ;
     RECT  3.233 33.168 3.521 34.248 ;
     RECT  2.704 3.024 3.665 4.44 ;
     RECT  3.665 3.36 3.697 4.44 ;
     RECT  2.704 9.696 3.701 9.72 ;
     RECT  2.704 10.8 3.733 11.448 ;
     RECT  3.443 15.696 3.737 16.584 ;
     RECT  2.704 38.4 3.769 38.424 ;
     RECT  2.704 39.744 3.769 39.768 ;
     RECT  2.704 20.928 3.773 21.48 ;
     RECT  2.704 22.8 3.805 22.824 ;
     RECT  3.769 38.4 3.809 39.768 ;
     RECT  2.704 7.392 3.829 7.464 ;
     RECT  3.017 14.4 3.836 14.424 ;
     RECT  3.449 18.528 3.845 18.552 ;
     RECT  3.805 22.8 3.845 23.304 ;
     RECT  3.733 10.752 3.877 11.736 ;
     RECT  2.704 31.344 3.905 31.896 ;
     RECT  3.829 6.816 3.917 7.464 ;
     RECT  3.836 14.4 3.923 15.384 ;
     RECT  3.697 3.36 3.989 4.92 ;
     RECT  3.905 30.72 3.989 31.896 ;
     RECT  3.989 3.408 4.057 4.92 ;
     RECT  3.923 14.4 4.061 14.952 ;
     RECT  3.733 43.056 4.067 43.08 ;
     RECT  4.021 0.576 4.105 0.6 ;
     RECT  3.809 38.4 4.169 39.336 ;
     RECT  2.704 36.912 4.201 37.368 ;
     RECT  4.169 38.4 4.201 38.808 ;
     RECT  3.989 31.344 4.205 31.896 ;
     RECT  3.877 10.08 4.237 11.784 ;
     RECT  2.704 27.888 4.385 27.912 ;
     RECT  3.917 7.392 4.417 7.464 ;
     RECT  3.233 35.424 4.489 35.928 ;
     RECT  4.201 36.912 4.489 38.808 ;
     RECT  4.057 3.408 4.529 5.016 ;
     RECT  4.417 7.392 4.561 8.184 ;
     RECT  3.845 23.28 4.565 23.304 ;
     RECT  3.737 16.512 4.597 16.584 ;
     RECT  4.489 35.424 4.597 38.808 ;
     RECT  4.529 3.84 4.601 5.016 ;
     RECT  4.601 3.888 4.705 5.016 ;
     RECT  4.061 14.784 4.709 14.952 ;
     RECT  2.704 28.944 4.709 28.968 ;
     RECT  4.597 34.992 4.787 38.808 ;
     RECT  4.205 31.872 4.925 31.896 ;
     RECT  4.705 3.888 4.993 5.208 ;
     RECT  3.521 33.168 5.101 33.816 ;
     RECT  4.787 34.992 5.101 35.784 ;
     RECT  5.125 26.208 5.132 26.232 ;
     RECT  4.787 36.912 5.137 38.808 ;
     RECT  5.057 40.992 5.141 41.016 ;
     RECT  4.489 24.48 5.171 24.504 ;
     RECT  4.849 29.088 5.173 29.4 ;
     RECT  5.132 26.208 5.212 26.76 ;
     RECT  5.132 42.192 5.218 42.216 ;
     RECT  5.212 26.736 5.219 26.76 ;
     RECT  5.218 42.192 5.237 42.264 ;
     RECT  4.921 1.728 5.245 1.752 ;
     RECT  4.993 3.888 5.245 5.736 ;
     RECT  4.237 10.08 5.357 12.312 ;
     RECT  5.173 29.088 5.365 29.688 ;
     RECT  5.317 30.96 5.365 30.984 ;
     RECT  5.101 33.168 5.411 35.784 ;
     RECT  2.704 19.776 5.425 19.8 ;
     RECT  3.773 21.456 5.425 21.48 ;
     RECT  4.597 16.512 5.465 17.112 ;
     RECT  5.465 16.512 5.501 16.536 ;
     RECT  4.561 7.392 5.509 8.808 ;
     RECT  5.509 7.296 5.569 8.808 ;
     RECT  5.137 36.912 5.597 38.856 ;
     RECT  5.357 10.08 5.605 12.072 ;
     RECT  5.245 3.888 5.641 5.88 ;
     RECT  5.411 33.168 5.641 33.192 ;
     RECT  5.605 10.032 5.645 12.072 ;
     RECT  5.597 36.912 5.681 39.384 ;
     RECT  5.525 2.88 5.749 2.904 ;
     RECT  5.641 3.888 5.749 6.024 ;
     RECT  5.237 42.192 5.821 43.08 ;
     RECT  5.365 29.088 5.897 30.984 ;
     RECT  5.137 0.096 5.9 0.12 ;
     RECT  5.245 1.728 5.905 1.848 ;
     RECT  5.605 17.856 5.941 17.88 ;
     RECT  5.9 0.096 5.987 0.552 ;
     RECT  5.425 19.776 5.987 21.48 ;
     RECT  5.411 34.176 6.037 35.784 ;
     RECT  5.681 36.912 6.037 39.336 ;
     RECT  5.749 2.88 6.073 6.024 ;
     RECT  5.569 7.104 6.073 8.808 ;
     RECT  5.645 10.032 6.073 10.824 ;
     RECT  5.821 41.616 6.133 43.08 ;
     RECT  6.181 25.104 6.217 25.128 ;
     RECT  4.993 22.656 6.253 22.68 ;
     RECT  6.133 41.568 6.275 43.08 ;
     RECT  6.217 15.936 6.301 16.296 ;
     RECT  6.073 2.88 6.325 10.824 ;
     RECT  6.001 40.464 6.325 40.488 ;
     RECT  4.709 14.928 6.361 14.952 ;
     RECT  5.941 17.856 6.509 18.648 ;
     RECT  6.301 16.272 6.541 16.296 ;
     RECT  5.641 32.304 6.581 33.192 ;
     RECT  6.325 2.544 6.653 10.824 ;
     RECT  6.541 16.272 6.659 17.064 ;
     RECT  6.325 40.464 6.659 41.016 ;
     RECT  6.037 34.176 6.661 39.336 ;
     RECT  6.253 22.656 6.685 22.824 ;
     RECT  5.897 29.376 6.685 30.984 ;
     RECT  6.685 22.656 6.755 23.4 ;
     RECT  6.505 26.832 6.757 26.856 ;
     RECT  6.653 3.936 6.761 10.824 ;
     RECT  6.755 22.752 6.769 23.4 ;
     RECT  6.761 6.816 6.793 10.824 ;
     RECT  5.645 11.952 6.793 12.072 ;
     RECT  6.509 18.144 6.793 18.648 ;
     RECT  6.653 2.544 6.901 2.904 ;
     RECT  6.793 6.816 7.1 12.072 ;
     RECT  7.1 6.816 7.141 12.6 ;
     RECT  5.987 0.096 7.189 0.216 ;
     RECT  6.217 24.912 7.261 25.128 ;
     RECT  6.685 29.376 7.297 31.368 ;
     RECT  6.793 18.144 7.333 18.696 ;
     RECT  7.189 0.096 7.381 0.264 ;
     RECT  7.141 6.816 7.441 12.888 ;
     RECT  6.361 13.968 7.441 14.952 ;
     RECT  7.333 18.144 7.549 18.792 ;
     RECT  5.987 19.776 7.549 19.8 ;
     RECT  6.661 34.176 7.621 39.576 ;
     RECT  6.659 40.896 7.621 41.016 ;
     RECT  7.381 0.096 7.669 0.312 ;
     RECT  6.901 1.728 7.669 2.904 ;
     RECT  6.761 3.936 7.669 5.496 ;
     RECT  7.441 6.816 7.729 14.952 ;
     RECT  7.261 24.576 7.729 25.128 ;
     RECT  7.669 1.728 7.808 5.496 ;
     RECT  7.729 6.576 7.808 14.952 ;
     RECT  6.659 16.656 7.808 17.064 ;
     RECT  7.549 18.144 7.808 19.8 ;
     RECT  5.987 21.456 7.808 21.48 ;
     RECT  6.769 22.752 7.808 22.776 ;
     RECT  7.729 24.48 7.808 25.128 ;
     RECT  6.757 26.832 7.808 27.48 ;
     RECT  7.297 29.04 7.808 31.368 ;
     RECT  6.581 32.592 7.808 33.192 ;
     RECT  7.621 34.176 7.808 41.016 ;
     RECT  7.669 0.096 7.811 0.456 ;
     RECT  7.808 1.728 7.907 41.052 ;
     RECT  7.907 2.148 7.912 41.052 ;
     RECT  7.912 2.418 8.104 40.782 ;
     RECT  8.104 18.672 8.201 19.272 ;
     RECT  8.104 34.368 8.243 40.488 ;
     RECT  8.104 31.872 8.273 33.048 ;
     RECT  7.811 0.096 8.309 0.36 ;
     RECT  6.275 42.192 8.309 43.08 ;
     RECT  8.104 24.48 8.345 25.704 ;
     RECT  8.309 42.816 8.345 43.08 ;
     RECT  8.345 25.056 8.387 25.704 ;
     RECT  8.243 34.368 8.417 39.576 ;
     RECT  8.104 2.544 8.524 13.08 ;
     RECT  8.201 18.672 8.669 18.792 ;
     RECT  8.273 31.872 8.675 32.904 ;
     RECT  8.104 16.656 8.705 16.68 ;
     RECT  8.417 34.608 8.705 39.576 ;
     RECT  8.104 26.832 8.813 29.064 ;
     RECT  8.345 42.816 9.029 43.032 ;
     RECT  8.813 27.36 9.173 29.064 ;
     RECT  9.173 27.888 9.209 29.064 ;
     RECT  8.524 9.84 9.313 13.08 ;
     RECT  8.104 14.736 9.313 14.76 ;
     RECT  8.309 0.192 9.353 0.36 ;
     RECT  8.524 2.544 9.353 8.76 ;
     RECT  9.313 9.84 9.421 14.76 ;
     RECT  8.387 25.68 9.421 25.704 ;
     RECT  9.353 2.544 9.425 6.072 ;
     RECT  8.104 23.136 9.457 23.16 ;
     RECT  9.421 25.152 9.457 25.704 ;
     RECT  9.353 0.192 9.461 0.312 ;
     RECT  9.457 23.136 9.533 25.704 ;
     RECT  9.425 2.544 9.569 5.784 ;
     RECT  9.209 29.04 9.605 29.064 ;
     RECT  8.705 34.608 9.641 38.76 ;
     RECT  8.104 30.048 9.677 30.216 ;
     RECT  9.461 0.192 9.749 0.216 ;
     RECT  9.641 34.944 9.749 38.76 ;
     RECT  9.029 42.816 9.785 42.888 ;
     RECT  9.745 39.888 9.817 39.912 ;
     RECT  9.749 35.568 9.821 38.76 ;
     RECT  9.533 23.136 9.857 25.176 ;
     RECT  9.353 7.056 9.893 8.76 ;
     RECT  9.857 23.136 9.893 24.456 ;
     RECT  9.893 7.152 10.033 8.76 ;
     RECT  9.421 9.84 10.033 14.904 ;
     RECT  9.677 30.048 10.177 30.072 ;
     RECT  8.675 32.496 10.177 32.904 ;
     RECT  9.209 27.888 10.213 27.912 ;
     RECT  10.177 32.496 10.249 33.288 ;
     RECT  10.033 7.152 10.259 14.904 ;
     RECT  9.745 15.984 10.259 16.008 ;
     RECT  9.277 17.088 10.361 17.112 ;
     RECT  10.213 27.312 10.393 27.912 ;
     RECT  10.249 20.304 10.573 20.328 ;
     RECT  9.893 23.136 10.577 23.88 ;
     RECT  9.817 39.888 10.609 40.344 ;
     RECT  10.393 27.312 10.645 28.44 ;
     RECT  10.609 39.888 10.649 40.584 ;
     RECT  9.821 35.568 10.753 38.664 ;
     RECT  10.259 7.152 10.793 14.808 ;
     RECT  10.577 23.856 10.829 23.88 ;
     RECT  10.645 27.312 10.837 28.68 ;
     RECT  10.177 30 10.837 30.072 ;
     RECT  10.793 7.152 10.861 13.704 ;
     RECT  10.861 7.056 10.865 13.704 ;
     RECT  10.793 14.784 10.865 14.808 ;
     RECT  10.249 32.352 10.865 33.288 ;
     RECT  9.785 42.864 10.865 42.888 ;
     RECT  10.865 32.352 11.077 33.096 ;
     RECT  9.569 2.832 11.117 5.784 ;
     RECT  10.837 27.312 11.117 30.072 ;
     RECT  11.117 28.176 11.123 30.072 ;
     RECT  10.753 35.04 11.149 38.664 ;
     RECT  11.117 5.136 11.333 5.784 ;
     RECT  11.149 35.04 11.365 38.712 ;
     RECT  11.365 35.04 11.581 38.76 ;
     RECT  10.865 7.056 11.585 13.416 ;
     RECT  11.581 34.752 11.621 38.76 ;
     RECT  11.117 2.832 11.725 3.72 ;
     RECT  11.333 5.424 11.761 5.784 ;
     RECT  11.689 26.832 11.801 27.192 ;
     RECT  11.621 34.752 11.837 36.072 ;
     RECT  11.585 7.392 11.869 13.416 ;
     RECT  11.869 7.392 11.873 13.848 ;
     RECT  10.573 19.776 11.905 20.328 ;
     RECT  8.104 21.456 11.905 21.48 ;
     RECT  11.077 31.92 11.941 33.096 ;
     RECT  11.941 31.2 11.948 33.096 ;
     RECT  11.123 28.176 11.987 30.024 ;
     RECT  11.725 2.736 12.035 3.72 ;
     RECT  11.948 31.008 12.035 33.096 ;
     RECT  11.987 29.568 12.053 30.024 ;
     RECT  12.035 32.208 12.085 33.096 ;
     RECT  11.837 34.752 12.085 35.928 ;
     RECT  11.905 19.776 12.125 21.48 ;
     RECT  11.621 37.344 12.125 38.76 ;
     RECT  11.987 28.176 12.161 28.488 ;
     RECT  12.125 37.584 12.337 38.76 ;
     RECT  11.581 17.328 12.517 17.352 ;
     RECT  12.517 17.328 12.589 17.688 ;
     RECT  8.669 18.672 12.589 18.696 ;
     RECT  10.969 24.384 12.733 24.408 ;
     RECT  11.873 7.44 12.833 13.848 ;
     RECT  12.035 31.2 13.057 31.224 ;
     RECT  11.869 22.464 13.093 22.488 ;
     RECT  12.035 2.736 13.208 3.432 ;
     RECT  11.761 5.424 13.208 6.264 ;
     RECT  12.833 7.44 13.208 14.808 ;
     RECT  10.393 15.84 13.208 15.864 ;
     RECT  12.589 17.328 13.208 18.696 ;
     RECT  12.125 19.776 13.208 19.8 ;
     RECT  12.125 21.456 13.208 21.48 ;
     RECT  13.093 22.464 13.208 22.872 ;
     RECT  12.733 23.856 13.208 24.408 ;
     RECT  12.553 25.728 13.208 25.752 ;
     RECT  11.801 27.168 13.208 27.192 ;
     RECT  12.161 28.176 13.208 28.2 ;
     RECT  12.053 29.568 13.208 29.64 ;
     RECT  13.057 30.864 13.208 31.224 ;
     RECT  12.085 32.208 13.208 35.928 ;
     RECT  12.337 37.584 13.208 39.24 ;
     RECT  10.649 40.56 13.208 40.584 ;
     RECT  13.208 2.148 13.312 41.052 ;
     RECT  13.312 2.418 13.504 40.782 ;
     RECT  13.504 13.68 13.529 13.848 ;
     RECT  13.504 27.168 13.619 27.336 ;
     RECT  13.504 40.56 13.673 40.584 ;
     RECT  13.504 32.208 13.709 35.352 ;
     RECT  13.504 16.752 13.811 17.112 ;
     RECT  13.504 18.24 13.811 19.8 ;
     RECT  13.504 30.864 13.817 30.888 ;
     RECT  13.811 18.96 13.907 19.8 ;
     RECT  13.907 18.96 13.948 19.128 ;
     RECT  13.504 7.968 14.051 9.096 ;
     RECT  14.051 8.448 14.092 9.096 ;
     RECT  13.504 21.456 14.141 24.408 ;
     RECT  14.141 21.456 14.213 23.448 ;
     RECT  13.709 32.208 14.243 33.528 ;
     RECT  13.709 34.608 14.243 35.352 ;
     RECT  14.243 34.752 14.285 35.352 ;
     RECT  14.092 8.448 14.321 9.048 ;
     RECT  14.213 23.424 14.321 23.448 ;
     RECT  14.285 35.328 14.473 35.352 ;
     RECT  13.504 29.568 14.497 29.64 ;
     RECT  13.619 27.312 14.605 27.336 ;
     RECT  13.504 25.728 14.677 25.752 ;
     RECT  14.605 26.736 14.677 27.336 ;
     RECT  14.677 25.728 14.713 27.336 ;
     RECT  13.504 37.584 14.819 38.808 ;
     RECT  14.713 25.728 14.861 27.912 ;
     RECT  13.504 2.832 14.867 5.88 ;
     RECT  14.243 32.208 14.897 33.048 ;
     RECT  13.504 10.128 14.917 11.784 ;
     RECT  13.529 13.68 14.917 13.704 ;
     RECT  14.861 26.64 14.933 27.912 ;
     RECT  14.867 2.832 14.963 5.16 ;
     RECT  14.917 10.128 15.004 13.704 ;
     RECT  14.897 32.208 15.077 32.472 ;
     RECT  14.933 26.64 15.113 26.76 ;
     RECT  15.004 10.128 15.221 12.552 ;
     RECT  14.497 29.568 15.289 30.456 ;
     RECT  13.504 15.408 15.349 15.432 ;
     RECT  15.221 10.176 15.395 12.552 ;
     RECT  15.395 10.176 15.401 10.2 ;
     RECT  14.963 2.832 15.437 4.536 ;
     RECT  14.321 8.448 15.437 8.472 ;
     RECT  14.213 21.456 15.491 22.2 ;
     RECT  15.004 13.68 15.509 13.704 ;
     RECT  15.253 39.888 15.509 39.912 ;
     RECT  15.349 14.784 15.545 15.432 ;
     RECT  15.289 29.568 15.617 30.744 ;
     RECT  15.325 6.144 15.649 6.168 ;
     RECT  13.811 17.088 15.829 17.112 ;
     RECT  14.933 27.888 15.829 27.912 ;
     RECT  15.617 29.568 15.829 30.552 ;
     RECT  13.948 18.96 15.865 18.984 ;
     RECT  15.395 11.76 15.869 12.552 ;
     RECT  15.829 17.088 15.869 17.4 ;
     RECT  15.649 6.144 15.973 6.744 ;
     RECT  15.437 4.32 15.98 4.536 ;
     RECT  15.865 18.384 16.013 18.984 ;
     RECT  15.973 6.144 16.019 7.464 ;
     RECT  15.545 15.408 16.045 15.432 ;
     RECT  16.013 18.384 16.049 18.84 ;
     RECT  15.98 4.32 16.067 4.92 ;
     RECT  15.077 32.448 16.117 32.472 ;
     RECT  15.793 24.48 16.121 24.504 ;
     RECT  16.117 32.448 16.153 32.856 ;
     RECT  15.829 27.888 16.157 30.552 ;
     RECT  16.045 15.408 16.189 15.528 ;
     RECT  16.153 32.4 16.297 32.856 ;
     RECT  15.433 33.936 16.297 33.96 ;
     RECT  15.253 35.28 16.373 35.304 ;
     RECT  15.113 26.64 16.405 26.664 ;
     RECT  16.157 27.888 16.405 27.912 ;
     RECT  16.019 7.44 16.409 7.464 ;
     RECT  15.445 23.376 16.477 23.4 ;
     RECT  15.869 11.76 16.513 12.36 ;
     RECT  15.491 21.456 16.513 21.48 ;
     RECT  16.297 32.4 16.513 33.96 ;
     RECT  15.437 2.832 16.517 2.856 ;
     RECT  16.067 4.32 16.553 4.344 ;
     RECT  14.819 38.256 16.556 38.808 ;
     RECT  16.513 10.992 16.595 12.36 ;
     RECT  16.019 6.144 16.625 6.312 ;
     RECT  16.477 22.8 16.697 23.4 ;
     RECT  15.869 17.376 16.733 17.4 ;
     RECT  15.649 13.824 16.765 13.848 ;
     RECT  16.189 15.408 16.765 15.96 ;
     RECT  16.765 13.632 16.769 15.96 ;
     RECT  16.405 26.64 16.769 27.912 ;
     RECT  16.513 20.832 16.805 21.48 ;
     RECT  16.513 31.728 16.981 33.96 ;
     RECT  16.697 22.8 17.021 22.824 ;
     RECT  16.157 29.568 17.057 30.552 ;
     RECT  16.625 6.288 17.129 6.312 ;
     RECT  16.009 8.544 17.129 8.568 ;
     RECT  16.981 31.632 17.129 33.96 ;
     RECT  17.129 31.632 17.165 33.624 ;
     RECT  17.165 31.728 17.201 33.624 ;
     RECT  17.201 31.728 17.273 31.752 ;
     RECT  16.049 18.816 17.345 18.84 ;
     RECT  16.769 26.64 17.453 27.336 ;
     RECT  17.305 36.24 17.509 36.264 ;
     RECT  17.453 26.64 17.521 27.192 ;
     RECT  17.509 34.752 17.596 36.264 ;
     RECT  16.595 10.992 17.629 11.016 ;
     RECT  16.556 38.16 17.953 38.808 ;
     RECT  16.805 21.456 18.025 21.48 ;
     RECT  18.061 5.664 18.097 5.688 ;
     RECT  17.057 29.568 18.133 30.456 ;
     RECT  17.596 36.24 18.14 36.264 ;
     RECT  17.305 7.632 18.169 7.656 ;
     RECT  17.701 23.904 18.241 23.928 ;
     RECT  17.521 8.976 18.421 9.528 ;
     RECT  17.629 10.992 18.421 11.448 ;
     RECT  16.945 2.88 18.608 2.904 ;
     RECT  18.097 5.28 18.608 5.688 ;
     RECT  18.169 6.816 18.608 7.656 ;
     RECT  18.421 8.976 18.608 11.448 ;
     RECT  16.769 13.632 18.608 15.528 ;
     RECT  17.701 17.664 18.608 17.688 ;
     RECT  18.025 21.456 18.608 22.248 ;
     RECT  18.241 23.904 18.608 24.648 ;
     RECT  17.521 25.728 18.608 27.192 ;
     RECT  18.133 29.568 18.608 30.792 ;
     RECT  17.201 32.832 18.608 33.624 ;
     RECT  18.14 36.24 18.608 37.08 ;
     RECT  17.953 38.16 18.608 39.048 ;
     RECT  17.485 40.272 18.608 40.296 ;
     RECT  18.608 2.148 18.712 41.052 ;
     RECT  18.712 2.418 18.904 41.016 ;
     RECT  18.904 2.496 18.965 2.904 ;
     RECT  18.904 14.4 19.145 16.248 ;
     RECT  18.904 11.28 19.187 12.024 ;
     RECT  18.904 6.816 19.397 7.992 ;
     RECT  18.904 38.256 19.433 38.808 ;
     RECT  19.187 11.76 19.505 12.024 ;
     RECT  19.397 7.968 19.613 7.992 ;
     RECT  18.904 25.056 19.685 30.6 ;
     RECT  18.904 40.464 19.685 41.016 ;
     RECT  19.145 14.928 19.973 16.248 ;
     RECT  18.904 23.28 19.973 23.304 ;
     RECT  18.965 2.496 20.005 2.52 ;
     RECT  18.904 17.664 20.113 17.688 ;
     RECT  19.685 25.056 20.117 25.08 ;
     RECT  18.904 5.184 20.189 5.208 ;
     RECT  19.973 15.504 20.257 16.248 ;
     RECT  20.113 17.664 20.257 18.504 ;
     RECT  20.005 2.496 20.401 3.432 ;
     RECT  18.904 34.944 20.401 36.504 ;
     RECT  19.685 26.208 20.435 30.6 ;
     RECT  19.685 40.464 20.437 40.488 ;
     RECT  20.401 34.944 20.473 37.08 ;
     RECT  19.433 38.256 20.473 38.76 ;
     RECT  20.435 26.208 20.476 26.76 ;
     RECT  20.435 27.84 20.531 30.6 ;
     RECT  19.397 6.816 20.543 6.84 ;
     RECT  18.904 33.84 20.545 33.864 ;
     RECT  20.473 34.944 20.545 38.76 ;
     RECT  20.401 2.496 20.549 4.008 ;
     RECT  20.005 31.728 20.549 31.752 ;
     RECT  20.545 33.84 20.549 38.76 ;
     RECT  20.549 33.84 20.581 35.592 ;
     RECT  20.257 15.504 20.621 18.504 ;
     RECT  20.549 3.408 20.627 4.008 ;
     RECT  19.505 12 20.653 12.024 ;
     RECT  20.653 12 20.693 12.552 ;
     RECT  20.531 27.84 20.729 28.056 ;
     RECT  20.543 6.816 20.819 7.8 ;
     RECT  18.904 9.504 20.819 9.528 ;
     RECT  20.549 36.672 20.945 38.76 ;
     RECT  20.621 15.504 21.089 17.832 ;
     RECT  20.509 5.472 21.161 5.688 ;
     RECT  21.161 5.472 21.193 5.496 ;
     RECT  21.193 14.208 21.26 14.232 ;
     RECT  21.089 15.504 21.26 17.688 ;
     RECT  18.904 21.072 21.349 21.48 ;
     RECT  20.476 26.208 21.395 26.664 ;
     RECT  20.437 39.84 21.409 40.488 ;
     RECT  21.26 14.208 21.443 17.688 ;
     RECT  21.349 21.072 21.539 22.296 ;
     RECT  21.265 24.912 21.553 24.936 ;
     RECT  21.395 26.64 21.553 26.664 ;
     RECT  20.729 27.84 21.553 27.864 ;
     RECT  20.581 33.36 21.637 35.592 ;
     RECT  20.945 36.672 21.637 38.568 ;
     RECT  20.627 3.984 21.665 4.008 ;
     RECT  21.553 26.64 21.665 27.864 ;
     RECT  21.665 27.84 21.683 27.864 ;
     RECT  21.539 21.072 21.737 21.96 ;
     RECT  21.637 33.36 21.773 38.568 ;
     RECT  20.693 12.144 21.932 12.552 ;
     RECT  21.773 33.648 21.949 38.568 ;
     RECT  21.949 33.648 21.989 38.712 ;
     RECT  21.932 12.144 22.019 12.936 ;
     RECT  21.989 34.704 22.061 38.712 ;
     RECT  21.737 21.072 22.093 21.48 ;
     RECT  21.553 24.624 22.097 24.936 ;
     RECT  22.061 34.944 22.124 38.712 ;
     RECT  21.409 39.744 22.124 40.488 ;
     RECT  20.531 29.184 22.129 30.6 ;
     RECT  21.443 16.224 22.133 17.688 ;
     RECT  22.129 28.032 22.205 30.6 ;
     RECT  22.124 34.944 22.205 40.488 ;
     RECT  22.205 35.52 22.211 40.488 ;
     RECT  21.443 14.208 22.213 14.664 ;
     RECT  20.819 6.816 22.241 6.84 ;
     RECT  21.553 10.704 22.241 10.728 ;
     RECT  22.019 12.144 22.259 12.168 ;
     RECT  22.211 35.52 22.277 38.712 ;
     RECT  22.277 36.48 22.313 38.712 ;
     RECT  22.213 14.064 22.691 14.664 ;
     RECT  21.193 5.088 22.693 5.496 ;
     RECT  21.805 3.264 22.745 3.288 ;
     RECT  22.093 20.592 22.777 21.48 ;
     RECT  22.693 4.512 22.78 5.496 ;
     RECT  21.733 9.696 22.813 9.72 ;
     RECT  22.133 16.224 22.813 16.824 ;
     RECT  22.313 36.48 22.853 37.08 ;
     RECT  22.813 9.696 22.883 10.632 ;
     RECT  22.777 19.008 22.885 21.48 ;
     RECT  21.989 33.648 22.889 33.672 ;
     RECT  22.883 10.176 22.897 10.632 ;
     RECT  22.885 19.008 22.925 21.864 ;
     RECT  22.777 32.64 22.957 32.664 ;
     RECT  22.691 14.64 22.961 14.664 ;
     RECT  22.925 21.216 22.981 21.864 ;
     RECT  20.365 23.328 23.027 23.352 ;
     RECT  22.981 21.216 23.029 22.2 ;
     RECT  22.957 32.592 23.281 32.664 ;
     RECT  22.211 39.744 23.389 40.44 ;
     RECT  22.313 38.256 23.497 38.712 ;
     RECT  23.389 39.744 23.497 40.92 ;
     RECT  21.665 26.64 23.785 26.76 ;
     RECT  22.205 28.032 23.785 30.408 ;
     RECT  23.101 3.936 24.008 3.96 ;
     RECT  22.78 5.472 24.008 5.496 ;
     RECT  22.885 8.976 24.008 9 ;
     RECT  22.897 10.176 24.008 10.2 ;
     RECT  22.417 12 24.008 12.024 ;
     RECT  23.857 13.92 24.008 13.944 ;
     RECT  23.785 14.928 24.008 14.952 ;
     RECT  22.813 15.936 24.008 16.824 ;
     RECT  22.925 19.008 24.008 19.032 ;
     RECT  23.029 21.216 24.008 23.16 ;
     RECT  22.981 25.104 24.008 25.128 ;
     RECT  23.785 26.64 24.008 30.408 ;
     RECT  23.389 31.392 24.008 31.416 ;
     RECT  23.281 32.592 24.008 32.856 ;
     RECT  23.857 34.224 24.008 34.248 ;
     RECT  22.853 36.576 24.008 37.08 ;
     RECT  23.497 38.256 24.008 40.92 ;
     RECT  24.008 2.148 24.112 41.052 ;
     RECT  24.112 2.418 24.304 41.016 ;
     RECT  24.304 26.64 24.419 31.416 ;
     RECT  24.419 30.624 24.473 31.416 ;
     RECT  24.304 19.2 24.517 19.992 ;
     RECT  24.419 26.64 24.545 29.592 ;
     RECT  24.304 2.64 24.617 2.664 ;
     RECT  24.304 16.368 24.653 17.112 ;
     RECT  24.304 38.256 24.725 41.016 ;
     RECT  24.473 30.624 24.761 31.032 ;
     RECT  24.304 7.392 24.803 9.288 ;
     RECT  24.304 3.936 24.905 3.96 ;
     RECT  24.761 30.624 25.085 30.648 ;
     RECT  24.725 38.256 25.193 40.968 ;
     RECT  24.803 8.448 25.265 9.288 ;
     RECT  24.304 25.056 25.297 25.08 ;
     RECT  24.545 26.64 25.297 27.192 ;
     RECT  24.304 33.552 25.297 33.576 ;
     RECT  24.304 21.216 25.337 21.768 ;
     RECT  24.803 7.392 25.369 7.416 ;
     RECT  25.337 21.456 25.369 21.768 ;
     RECT  24.304 22.752 25.369 23.304 ;
     RECT  24.304 5.472 25.405 5.496 ;
     RECT  25.297 25.056 25.481 27.192 ;
     RECT  24.304 12.096 25.589 12.12 ;
     RECT  25.297 33.552 25.661 34.104 ;
     RECT  24.653 16.992 25.801 17.112 ;
     RECT  25.369 21.456 25.805 23.304 ;
     RECT  25.801 16.08 25.837 17.112 ;
     RECT  25.82 10.32 25.907 10.344 ;
     RECT  25.369 6.816 25.981 7.416 ;
     RECT  25.193 38.256 25.981 38.568 ;
     RECT  25.405 5.136 26.017 5.496 ;
     RECT  25.661 34.08 26.053 34.104 ;
     RECT  26.053 34.08 26.089 35.016 ;
     RECT  24.304 36.576 26.089 36.84 ;
     RECT  25.805 22.752 26.125 23.304 ;
     RECT  24.304 14.928 26.269 14.952 ;
     RECT  25.481 26.64 26.345 27.192 ;
     RECT  24.545 28.752 26.377 29.592 ;
     RECT  26.125 22.752 26.389 23.4 ;
     RECT  25.481 25.056 26.389 25.08 ;
     RECT  25.981 38.112 26.389 38.568 ;
     RECT  25.193 39.744 26.389 40.968 ;
     RECT  26.269 13.968 26.417 14.952 ;
     RECT  26.389 22.752 26.476 25.08 ;
     RECT  26.476 25.008 26.485 25.08 ;
     RECT  26.089 34.08 26.485 36.84 ;
     RECT  26.476 22.752 26.561 23.88 ;
     RECT  26.389 38.112 26.561 40.968 ;
     RECT  26.485 25.008 26.569 25.128 ;
     RECT  26.485 34.08 26.665 36.936 ;
     RECT  26.561 38.112 26.665 38.424 ;
     RECT  26.665 34.08 26.705 38.424 ;
     RECT  26.417 14.928 26.813 14.952 ;
     RECT  26.705 36.576 26.813 38.424 ;
     RECT  25.837 16.08 26.849 17.64 ;
     RECT  26.705 34.08 26.993 35.544 ;
     RECT  26.017 4.272 27.025 5.496 ;
     RECT  25.981 6.816 27.025 7.8 ;
     RECT  24.517 19.2 27.061 19.224 ;
     RECT  26.341 2.832 27.065 2.856 ;
     RECT  26.569 25.008 27.065 25.032 ;
     RECT  27.061 19.2 27.101 19.368 ;
     RECT  26.561 39.744 27.101 40.968 ;
     RECT  26.813 36.768 27.137 38.424 ;
     RECT  26.345 26.64 27.313 26.76 ;
     RECT  27.025 4.272 27.347 7.8 ;
     RECT  25.265 9.264 27.349 9.288 ;
     RECT  27.313 26.64 27.385 27.336 ;
     RECT  26.377 28.416 27.385 29.592 ;
     RECT  27.347 6.816 27.389 7.8 ;
     RECT  26.993 34.08 27.425 35.496 ;
     RECT  27.425 34.752 27.433 35.496 ;
     RECT  27.385 26.64 27.443 29.592 ;
     RECT  27.101 19.344 27.533 19.368 ;
     RECT  26.849 16.08 27.569 17.112 ;
     RECT  27.389 7.392 27.733 7.8 ;
     RECT  27.349 9.264 27.745 9.384 ;
     RECT  27.347 4.272 27.749 5.496 ;
     RECT  27.733 7.392 27.779 7.992 ;
     RECT  27.137 38.112 27.785 38.424 ;
     RECT  26.413 12.768 27.857 12.792 ;
     RECT  27.443 26.736 27.925 29.592 ;
     RECT  27.101 40.56 27.929 40.968 ;
     RECT  26.449 11.136 27.961 11.16 ;
     RECT  27.433 34.992 28.037 35.496 ;
     RECT  27.925 26.736 28.073 30.072 ;
     RECT  27.637 14.784 28.115 14.808 ;
     RECT  25.805 21.456 28.249 21.624 ;
     RECT  28.073 26.736 28.253 29.64 ;
     RECT  28.037 34.992 28.289 35.016 ;
     RECT  27.781 3.024 28.325 4.008 ;
     RECT  26.561 23.28 28.429 23.88 ;
     RECT  27.569 16.992 28.453 17.112 ;
     RECT  27.779 7.968 28.465 7.992 ;
     RECT  27.745 9.024 28.465 9.384 ;
     RECT  27.749 5.472 28.741 5.496 ;
     RECT  28.453 16.992 28.789 17.4 ;
     RECT  25.801 32.784 28.789 32.808 ;
     RECT  27.137 36.768 28.825 36.84 ;
     RECT  28.825 36.528 29.041 36.84 ;
     RECT  27.785 38.16 29.041 38.424 ;
     RECT  28.741 5.472 29.149 6.12 ;
     RECT  28.465 7.968 29.257 9.384 ;
     RECT  28.249 21.216 29.269 21.624 ;
     RECT  28.253 27.744 29.365 29.64 ;
     RECT  28.789 31.824 29.365 32.808 ;
     RECT  28.325 3.024 29.408 3.96 ;
     RECT  29.149 5.472 29.408 6.696 ;
     RECT  29.257 7.92 29.408 9.384 ;
     RECT  27.961 10.416 29.408 11.16 ;
     RECT  28.285 13.68 29.408 13.704 ;
     RECT  27.781 15.936 29.408 15.96 ;
     RECT  28.789 16.992 29.408 17.592 ;
     RECT  28.177 19.872 29.408 19.896 ;
     RECT  29.269 21.216 29.408 21.72 ;
     RECT  28.429 23.088 29.408 23.88 ;
     RECT  28.253 26.736 29.408 26.76 ;
     RECT  29.365 27.744 29.408 29.784 ;
     RECT  29.365 31.824 29.408 33.048 ;
     RECT  28.501 34.656 29.408 34.68 ;
     RECT  29.041 36.528 29.408 38.424 ;
     RECT  27.929 40.608 29.408 40.968 ;
     RECT  29.408 2.148 29.512 41.052 ;
     RECT  29.512 2.418 29.704 40.968 ;
     RECT  29.704 13.872 29.801 14.952 ;
     RECT  29.704 3.024 29.909 7.992 ;
     RECT  29.704 17.088 29.987 19.512 ;
     RECT  29.909 3.024 30.017 6.696 ;
     RECT  29.987 17.376 30.028 19.512 ;
     RECT  30.028 18.768 30.133 19.512 ;
     RECT  30.017 3.408 30.197 6.696 ;
     RECT  29.704 25.056 30.275 25.848 ;
     RECT  29.909 7.968 30.305 7.992 ;
     RECT  29.704 21.216 30.305 21.624 ;
     RECT  29.704 9.072 30.377 9.72 ;
     RECT  30.028 17.376 30.449 17.64 ;
     RECT  29.704 39.552 30.449 40.968 ;
     RECT  30.275 25.056 30.485 25.08 ;
     RECT  30.197 3.408 30.515 5.208 ;
     RECT  29.704 34.176 30.563 38.28 ;
     RECT  29.704 11.136 30.629 11.16 ;
     RECT  29.704 28.464 30.701 30.072 ;
     RECT  29.704 23.28 30.769 23.88 ;
     RECT  30.197 6.672 30.913 6.696 ;
     RECT  30.913 6.672 30.953 6.84 ;
     RECT  30.953 6.816 31.057 6.84 ;
     RECT  30.133 19.344 31.129 19.512 ;
     RECT  30.515 3.408 31.133 5.112 ;
     RECT  30.449 40.368 31.205 40.968 ;
     RECT  31.129 18.768 31.273 19.896 ;
     RECT  29.801 14.208 31.345 14.232 ;
     RECT  31.133 3.408 31.381 3.432 ;
     RECT  31.381 2.832 31.385 3.432 ;
     RECT  30.701 29.568 31.385 30.072 ;
     RECT  31.273 18.768 31.421 20.232 ;
     RECT  30.563 34.8 31.421 38.28 ;
     RECT  31.345 13.68 31.429 14.232 ;
     RECT  31.381 11.952 31.465 11.976 ;
     RECT  31.385 2.832 31.493 2.856 ;
     RECT  31.133 5.088 31.529 5.112 ;
     RECT  30.449 17.376 31.601 17.4 ;
     RECT  30.701 28.464 31.601 28.488 ;
     RECT  31.057 6.816 31.777 7.176 ;
     RECT  31.777 6.816 31.861 7.416 ;
     RECT  31.421 35.328 31.907 38.28 ;
     RECT  31.841 15.408 31.925 15.432 ;
     RECT  31.421 19.488 31.997 20.232 ;
     RECT  30.949 26.736 31.997 26.76 ;
     RECT  31.861 6.816 32.033 8.184 ;
     RECT  31.429 14.208 32.033 14.232 ;
     RECT  30.377 9.696 32.105 9.72 ;
     RECT  30.305 21.456 32.317 21.624 ;
     RECT  31.205 40.704 32.317 40.968 ;
     RECT  31.385 29.568 32.437 30.024 ;
     RECT  31.907 35.328 32.461 36.936 ;
     RECT  32.437 28.992 32.483 30.024 ;
     RECT  32.317 21.072 32.485 21.624 ;
     RECT  30.769 23.136 32.485 23.88 ;
     RECT  31.669 13.056 32.533 13.08 ;
     RECT  32.533 12.528 32.573 13.08 ;
     RECT  32.485 21.072 32.573 23.88 ;
     RECT  29.704 33.024 32.573 33.048 ;
     RECT  32.533 16.56 32.641 16.584 ;
     RECT  32.033 7.344 32.713 8.184 ;
     RECT  32.641 15.696 32.812 16.584 ;
     RECT  32.821 25.68 32.893 25.704 ;
     RECT  32.641 10.752 33.001 10.776 ;
     RECT  32.812 15.696 33.013 15.72 ;
     RECT  32.972 17.04 33.013 17.064 ;
     RECT  32.821 18.192 33.013 18.216 ;
     RECT  32.993 26.688 33.013 26.712 ;
     RECT  33.013 14.928 33.059 15.72 ;
     RECT  33.013 17.04 33.059 18.216 ;
     RECT  33.059 17.856 33.061 18.216 ;
     RECT  31.997 19.488 33.061 19.512 ;
     RECT  32.461 34.896 33.061 36.936 ;
     RECT  31.907 38.256 33.073 38.28 ;
     RECT  33.013 26.688 33.077 27.384 ;
     RECT  33.061 34.128 33.109 36.936 ;
     RECT  32.573 23.136 33.145 23.88 ;
     RECT  32.893 25.584 33.145 25.704 ;
     RECT  33.061 17.856 33.148 19.512 ;
     RECT  32.425 3.408 33.149 3.432 ;
     RECT  33.148 17.856 33.149 17.88 ;
     RECT  33.109 33.552 33.149 36.936 ;
     RECT  33.073 38.256 33.181 38.856 ;
     RECT  32.317 39.888 33.181 40.968 ;
     RECT  32.573 12.528 33.257 12.552 ;
     RECT  33.325 31.728 33.361 31.752 ;
     RECT  33.149 34.896 33.361 36.936 ;
     RECT  33.181 38.256 33.361 40.968 ;
     RECT  33.361 34.896 33.365 40.968 ;
     RECT  32.573 21.072 33.433 21.816 ;
     RECT  33.433 21.024 33.545 21.816 ;
     RECT  33.145 23.136 33.653 25.704 ;
     RECT  33.365 34.896 33.653 38.28 ;
     RECT  32.713 7.344 34.045 8.232 ;
     RECT  33.077 27.12 34.117 27.384 ;
     RECT  33.001 9.792 34.153 10.776 ;
     RECT  33.545 21.408 34.165 21.816 ;
     RECT  34.045 7.344 34.189 8.424 ;
     RECT  34.153 9.792 34.189 11.448 ;
     RECT  33.148 19.488 34.453 19.512 ;
     RECT  34.453 19.488 34.729 20.04 ;
     RECT  34.081 3.696 34.765 3.72 ;
     RECT  34.189 6.624 34.765 11.448 ;
     RECT  34.765 3.696 34.808 4.68 ;
     RECT  34.765 6.288 34.808 11.448 ;
     RECT  34.549 13.056 34.808 13.08 ;
     RECT  33.059 14.928 34.808 14.952 ;
     RECT  34.729 19.344 34.808 20.04 ;
     RECT  34.165 21.408 34.808 22.056 ;
     RECT  33.653 23.136 34.808 25.608 ;
     RECT  34.117 27.12 34.808 27.912 ;
     RECT  32.483 28.992 34.808 29.592 ;
     RECT  33.361 31.728 34.808 32.424 ;
     RECT  33.149 33.552 34.808 33.912 ;
     RECT  33.653 35.424 34.808 38.28 ;
     RECT  33.365 39.264 34.808 40.968 ;
     RECT  34.808 2.148 34.912 41.052 ;
     RECT  34.912 2.418 35.104 40.968 ;
     RECT  35.104 14.928 35.165 16.008 ;
     RECT  35.104 8.208 35.201 10.728 ;
     RECT  35.165 15.408 35.245 16.008 ;
     RECT  35.104 26.928 35.381 28.536 ;
     RECT  35.104 3.744 35.489 4.68 ;
     RECT  35.489 3.744 35.603 3.864 ;
     RECT  35.245 15.408 35.705 15.432 ;
     RECT  35.104 13.056 35.741 13.608 ;
     RECT  35.104 29.568 36.076 31.8 ;
     RECT  35.104 5.712 36.097 6.312 ;
     RECT  36.097 5.088 36.133 6.312 ;
     RECT  35.104 33.072 36.137 38.328 ;
     RECT  35.104 39.84 36.209 40.968 ;
     RECT  36.133 5.088 36.245 6.888 ;
     RECT  36.137 33.072 36.245 38.28 ;
     RECT  35.104 25.92 36.277 25.944 ;
     RECT  36.209 39.84 36.281 39.864 ;
     RECT  36.277 25.632 36.317 25.944 ;
     RECT  36.245 5.088 36.389 6.312 ;
     RECT  36.277 20.064 36.493 20.088 ;
     RECT  36.389 5.376 36.569 6.312 ;
     RECT  35.201 8.448 36.601 10.728 ;
     RECT  36.601 7.968 36.641 10.728 ;
     RECT  36.493 20.016 36.673 20.088 ;
     RECT  36.641 7.968 36.709 7.992 ;
     RECT  36.569 5.376 36.755 6.12 ;
     RECT  35.104 11.952 36.817 11.976 ;
     RECT  36.076 31.776 36.853 31.8 ;
     RECT  35.741 13.584 36.925 13.608 ;
     RECT  35.104 17.616 36.929 17.64 ;
     RECT  36.673 19.392 36.956 20.088 ;
     RECT  36.956 18.816 36.997 20.088 ;
     RECT  35.104 21.072 36.997 24.12 ;
     RECT  36.817 11.904 37.033 11.976 ;
     RECT  36.925 13.056 37.037 13.608 ;
     RECT  36.709 7.392 37.043 7.992 ;
     RECT  36.317 25.632 37.073 25.656 ;
     RECT  36.076 29.568 37.073 30.312 ;
     RECT  36.755 5.712 37.109 6.12 ;
     RECT  35.603 3.84 37.145 3.864 ;
     RECT  37.033 11.904 37.181 12.024 ;
     RECT  35.381 27.84 37.189 28.536 ;
     RECT  37.189 27.312 37.213 28.536 ;
     RECT  37.073 29.568 37.213 29.592 ;
     RECT  36.853 31.776 37.213 32.184 ;
     RECT  36.245 33.168 37.213 38.28 ;
     RECT  36.997 18.096 37.235 24.12 ;
     RECT  37.213 27.312 37.235 29.592 ;
     RECT  37.213 31.776 37.249 38.28 ;
     RECT  37.213 39.792 37.249 39.816 ;
     RECT  37.235 18.096 37.261 24.072 ;
     RECT  37.249 31.776 37.285 39.816 ;
     RECT  37.235 27.312 37.397 27.864 ;
     RECT  36.641 9.12 37.577 10.728 ;
     RECT  37.037 13.584 37.577 13.608 ;
     RECT  37.261 18.096 37.685 21.624 ;
     RECT  37.397 27.312 37.753 27.768 ;
     RECT  37.577 9.36 37.757 10.728 ;
     RECT  37.285 31.776 37.757 39.864 ;
     RECT  37.043 7.392 37.861 7.416 ;
     RECT  37.753 26.688 37.861 27.768 ;
     RECT  37.757 31.776 37.916 38.28 ;
     RECT  37.757 39.36 37.937 39.864 ;
     RECT  37.916 31.248 37.973 38.28 ;
     RECT  37.861 25.872 37.996 27.768 ;
     RECT  37.973 31.248 38.003 35.928 ;
     RECT  37.757 9.36 38.081 9.72 ;
     RECT  37.261 23.136 38.153 24.072 ;
     RECT  38.081 9.552 38.189 9.72 ;
     RECT  38.003 31.776 38.189 35.928 ;
     RECT  37.996 26.544 38.195 27.768 ;
     RECT  37.861 7.2 38.221 7.416 ;
     RECT  38.195 26.544 38.225 27.384 ;
     RECT  37.181 11.904 38.252 11.976 ;
     RECT  37.757 10.704 38.293 10.728 ;
     RECT  38.252 11.904 38.293 12.456 ;
     RECT  38.293 10.704 38.339 12.456 ;
     RECT  38.3 15.36 38.341 15.384 ;
     RECT  37.033 16.416 38.341 16.44 ;
     RECT  38.221 6.864 38.369 7.416 ;
     RECT  38.341 15.36 38.387 16.44 ;
     RECT  38.369 7.392 38.513 7.416 ;
     RECT  38.339 10.704 38.513 11.688 ;
     RECT  38.387 15.984 38.549 16.44 ;
     RECT  37.973 37.008 38.549 38.28 ;
     RECT  37.393 4.512 38.581 4.536 ;
     RECT  37.685 18.192 38.581 21.624 ;
     RECT  38.581 3.456 38.665 4.536 ;
     RECT  38.653 7.776 38.765 7.8 ;
     RECT  38.549 37.056 38.797 38.28 ;
     RECT  37.937 39.36 38.797 39.816 ;
     RECT  35.989 2.256 38.873 2.28 ;
     RECT  38.581 18.192 38.873 21.72 ;
     RECT  38.549 15.984 38.945 16.104 ;
     RECT  37.235 29.04 38.977 29.592 ;
     RECT  38.617 17.136 39.013 17.16 ;
     RECT  38.873 18.192 39.013 21.672 ;
     RECT  39.013 17.136 39.053 21.672 ;
     RECT  38.153 24.048 39.089 24.072 ;
     RECT  38.189 32.16 39.125 35.928 ;
     RECT  39.125 32.832 39.373 35.928 ;
     RECT  38.401 13.68 39.445 13.704 ;
     RECT  36.209 40.944 39.661 40.968 ;
     RECT  38.665 3.456 39.769 3.48 ;
     RECT  39.185 22.8 39.841 22.824 ;
     RECT  39.373 32.832 39.841 36.072 ;
     RECT  38.797 37.056 39.841 39.816 ;
     RECT  39.053 18.72 39.877 21.672 ;
     RECT  39.841 22.752 39.877 22.824 ;
     RECT  39.841 32.832 39.941 39.816 ;
     RECT  39.053 17.664 40.069 17.688 ;
     RECT  39.877 18.72 40.069 22.824 ;
     RECT  38.977 28.416 40.069 29.592 ;
     RECT  38.437 30.72 40.069 30.744 ;
     RECT  38.189 9.696 40.165 9.72 ;
     RECT  38.225 26.544 40.201 27.336 ;
     RECT  39.769 3.408 40.208 3.48 ;
     RECT  38.665 4.512 40.208 4.536 ;
     RECT  37.109 5.712 40.208 5.736 ;
     RECT  39.877 7.632 40.208 7.656 ;
     RECT  40.165 9.696 40.208 10.2 ;
     RECT  38.513 11.664 40.208 11.688 ;
     RECT  39.445 13.104 40.208 13.704 ;
     RECT  38.945 16.08 40.208 16.104 ;
     RECT  40.069 17.664 40.208 22.824 ;
     RECT  38.905 25.296 40.208 25.32 ;
     RECT  40.201 26.352 40.208 27.336 ;
     RECT  40.069 28.416 40.208 30.744 ;
     RECT  39.941 32.832 40.208 39.912 ;
     RECT  39.661 40.896 40.208 40.968 ;
     RECT  40.208 2.148 40.312 41.052 ;
     RECT  40.312 2.418 40.504 40.968 ;
     RECT  40.504 18 40.601 20.616 ;
     RECT  40.504 32.016 40.637 33.912 ;
     RECT  40.504 21.6 40.681 22.824 ;
     RECT  40.504 6.816 40.781 7.752 ;
     RECT  40.504 14.784 40.853 16.344 ;
     RECT  40.504 28.272 40.889 29.832 ;
     RECT  40.889 28.656 41.033 29.832 ;
     RECT  40.504 26.352 41.075 27.24 ;
     RECT  41.033 28.656 41.116 29.592 ;
     RECT  40.504 3.408 41.177 3.432 ;
     RECT  40.853 15.648 41.177 16.344 ;
     RECT  40.504 13.104 41.249 13.128 ;
     RECT  40.504 25.296 41.249 25.32 ;
     RECT  40.504 39.216 41.321 39.816 ;
     RECT  40.781 7.2 41.357 7.752 ;
     RECT  41.357 7.2 41.393 7.656 ;
     RECT  41.075 26.352 41.393 27.144 ;
     RECT  40.504 40.944 41.393 40.968 ;
     RECT  40.681 21.6 41.429 21.96 ;
     RECT  40.504 36 41.497 36.552 ;
     RECT  41.497 35.28 41.557 36.552 ;
     RECT  40.504 37.68 41.557 38.184 ;
     RECT  40.504 9.024 41.569 9.048 ;
     RECT  40.504 10.176 41.569 10.2 ;
     RECT  40.504 23.952 41.569 23.976 ;
     RECT  41.557 35.28 41.603 38.184 ;
     RECT  41.569 9.024 41.609 10.2 ;
     RECT  40.637 32.304 41.645 33.912 ;
     RECT  41.116 29.088 41.681 29.592 ;
     RECT  40.504 11.232 41.713 11.688 ;
     RECT  41.713 11.232 41.717 12.552 ;
     RECT  41.717 11.664 41.789 12.552 ;
     RECT  40.601 18.72 41.821 20.616 ;
     RECT  41.429 21.6 41.821 21.624 ;
     RECT  41.609 9.696 41.891 10.2 ;
     RECT  41.603 37.056 41.897 38.184 ;
     RECT  41.821 18.72 41.905 21.624 ;
     RECT  41.645 32.304 41.941 32.328 ;
     RECT  40.504 5.424 42.001 5.688 ;
     RECT  41.941 31.536 42.033 32.328 ;
     RECT  42.001 4.848 42.041 5.688 ;
     RECT  41.569 23.952 42.149 24.504 ;
     RECT  41.321 39.264 42.253 39.816 ;
     RECT  41.905 18.72 42.257 20.424 ;
     RECT  41.789 11.712 42.293 12.552 ;
     RECT  41.393 26.736 42.361 27.144 ;
     RECT  41.897 37.68 42.421 38.184 ;
     RECT  42.253 39.264 42.421 40.584 ;
     RECT  41.393 7.2 42.433 7.368 ;
     RECT  42.361 26.304 42.433 27.144 ;
     RECT  41.749 2.256 42.469 2.28 ;
     RECT  42.033 31.536 42.577 31.56 ;
     RECT  41.891 9.696 42.613 9.864 ;
     RECT  42.433 7.2 42.685 7.608 ;
     RECT  42.685 25.056 42.769 25.08 ;
     RECT  42.433 26.256 42.793 27.144 ;
     RECT  42.469 2.256 42.812 3.432 ;
     RECT  42.041 4.848 42.812 5.16 ;
     RECT  42.812 2.256 42.869 5.16 ;
     RECT  42.421 37.68 42.869 40.584 ;
     RECT  42.869 3.936 42.899 5.16 ;
     RECT  42.613 9.648 42.905 9.864 ;
     RECT  42.685 7.2 42.973 7.704 ;
     RECT  41.177 15.648 42.973 16.104 ;
     RECT  42.973 14.88 43.013 16.104 ;
     RECT  42.899 4.848 43.085 5.16 ;
     RECT  41.905 21.6 43.141 21.624 ;
     RECT  42.685 23.328 43.141 23.352 ;
     RECT  42.869 2.256 43.19 2.904 ;
     RECT  43.085 5.136 43.193 5.16 ;
     RECT  41.681 29.232 43.225 29.592 ;
     RECT  43.141 21.6 43.228 23.352 ;
     RECT  42.905 9.792 43.229 9.864 ;
     RECT  43.013 16.08 43.261 16.104 ;
     RECT  42.541 17.088 43.261 17.112 ;
     RECT  42.793 26.256 43.333 27.24 ;
     RECT  41.645 33.888 43.333 33.912 ;
     RECT  42.869 37.776 43.373 40.584 ;
     RECT  43.333 33.072 43.417 33.912 ;
     RECT  41.603 36 43.484 36.024 ;
     RECT  43.484 36 43.525 36.744 ;
     RECT  43.261 16.08 43.697 17.112 ;
     RECT  42.973 7.2 43.837 7.944 ;
     RECT  43.19 2.304 43.849 2.904 ;
     RECT  43.333 25.824 43.873 27.24 ;
     RECT  43.228 21.6 43.909 21.624 ;
     RECT  43.873 25.824 43.909 27.864 ;
     RECT  43.225 29.232 43.909 30.168 ;
     RECT  43.909 25.824 44.017 30.168 ;
     RECT  43.837 7.2 44.125 8.568 ;
     RECT  44.017 25.2 44.129 30.168 ;
     RECT  44.129 25.2 44.233 28.536 ;
     RECT  44.129 29.568 44.237 30.168 ;
     RECT  43.013 14.88 44.341 14.904 ;
     RECT  42.293 11.712 44.387 11.736 ;
     RECT  44.341 14.784 44.396 14.904 ;
     RECT  44.341 13.248 44.437 13.272 ;
     RECT  44.396 14.784 44.437 15.192 ;
     RECT  44.125 7.104 44.449 8.568 ;
     RECT  44.437 13.248 44.449 15.192 ;
     RECT  44.233 24.72 44.453 28.536 ;
     RECT  44.449 13.056 44.483 15.192 ;
     RECT  43.373 37.776 44.483 40.296 ;
     RECT  43.297 5.52 44.489 5.592 ;
     RECT  43.849 2.304 44.525 2.856 ;
     RECT  42.577 31.2 44.557 31.56 ;
     RECT  43.525 35.28 44.665 36.744 ;
     RECT  44.483 37.776 44.665 37.992 ;
     RECT  43.909 21.12 44.809 21.624 ;
     RECT  42.257 18.72 44.845 20.088 ;
     RECT  44.809 21.12 44.845 22.008 ;
     RECT  44.449 6.96 44.917 8.568 ;
     RECT  44.557 31.2 44.953 32.04 ;
     RECT  44.525 2.832 45.025 2.856 ;
     RECT  43.697 16.272 45.025 17.112 ;
     RECT  44.845 18.72 45.169 22.008 ;
     RECT  45.169 18.192 45.241 22.008 ;
     RECT  45.025 2.832 45.608 3.672 ;
     RECT  44.489 5.52 45.608 5.544 ;
     RECT  44.917 6.96 45.608 8.856 ;
     RECT  43.229 9.84 45.608 9.864 ;
     RECT  44.521 10.992 45.608 11.016 ;
     RECT  44.483 13.056 45.608 14.424 ;
     RECT  45.025 16.032 45.608 17.112 ;
     RECT  45.241 18.144 45.608 22.008 ;
     RECT  43.228 23.328 45.608 23.352 ;
     RECT  44.453 24.72 45.608 27.624 ;
     RECT  44.237 29.568 45.608 29.976 ;
     RECT  44.953 31.2 45.608 32.808 ;
     RECT  43.417 33.888 45.608 33.912 ;
     RECT  44.665 35.28 45.608 37.992 ;
     RECT  44.483 39.312 45.608 39.768 ;
     RECT  45.608 2.148 45.712 41.052 ;
     RECT  45.712 2.418 45.904 40.782 ;
     RECT  45.904 20.352 46.037 21.768 ;
     RECT  45.904 35.28 46.289 40.2 ;
     RECT  46.037 20.352 46.433 21 ;
     RECT  46.289 35.808 46.469 40.2 ;
     RECT  45.904 33.6 46.499 33.912 ;
     RECT  46.469 35.808 46.505 36.12 ;
     RECT  45.904 25.2 46.533 27.144 ;
     RECT  45.904 5.232 46.613 7.128 ;
     RECT  45.904 18.144 46.721 18.792 ;
     RECT  45.904 29.568 46.739 30.312 ;
     RECT  45.904 23.328 46.793 23.928 ;
     RECT  46.469 37.104 46.937 40.2 ;
     RECT  46.793 23.328 47.009 23.88 ;
     RECT  46.533 25.824 47.045 27.144 ;
     RECT  47.005 16.56 47.113 16.584 ;
     RECT  46.721 18.144 47.113 18.168 ;
     RECT  47.045 26.736 47.113 27.144 ;
     RECT  47.009 23.328 47.117 23.352 ;
     RECT  46.613 5.712 47.257 7.128 ;
     RECT  46.739 29.568 47.285 29.64 ;
     RECT  45.904 15.408 47.297 15.432 ;
     RECT  47.113 26.736 47.317 27.384 ;
     RECT  47.257 5.712 47.365 7.896 ;
     RECT  47.285 29.088 47.369 29.64 ;
     RECT  45.904 14.112 47.509 14.424 ;
     RECT  47.545 11.952 47.612 11.976 ;
     RECT  46.433 20.352 47.617 20.376 ;
     RECT  47.317 26.736 47.621 27.624 ;
     RECT  47.509 13.92 47.653 14.424 ;
     RECT  45.904 31.872 47.653 31.896 ;
     RECT  47.653 31.872 47.689 32.472 ;
     RECT  46.499 33.6 47.689 33.624 ;
     RECT  47.612 11.952 47.699 12.792 ;
     RECT  47.369 29.568 47.725 29.64 ;
     RECT  47.689 33.6 47.795 34.248 ;
     RECT  47.689 31.872 47.797 32.568 ;
     RECT  47.795 33.6 47.797 34.104 ;
     RECT  46.505 36 47.945 36.024 ;
     RECT  47.617 19.968 48.037 20.376 ;
     RECT  48.037 19.92 48.049 20.376 ;
     RECT  47.653 13.92 48.053 14.904 ;
     RECT  48.049 19.392 48.083 20.376 ;
     RECT  47.699 11.952 48.085 11.976 ;
     RECT  47.113 16.56 48.085 18.168 ;
     RECT  48.083 19.392 48.085 19.992 ;
     RECT  48.085 16.56 48.133 19.992 ;
     RECT  47.617 30.768 48.229 30.792 ;
     RECT  47.365 5.712 48.277 7.992 ;
     RECT  48.085 11.424 48.323 11.976 ;
     RECT  48.085 4.56 48.409 4.584 ;
     RECT  48.277 5.712 48.409 8.472 ;
     RECT  48.229 30.72 48.409 30.792 ;
     RECT  47.797 31.872 48.409 34.104 ;
     RECT  46.937 37.104 48.409 39.624 ;
     RECT  48.409 30.72 48.515 34.104 ;
     RECT  47.725 29.568 48.557 29.688 ;
     RECT  47.621 27.12 48.661 27.624 ;
     RECT  48.409 4.56 48.773 8.472 ;
     RECT  48.812 35.28 48.899 35.304 ;
     RECT  48.515 32.448 48.989 32.472 ;
     RECT  48.323 11.952 49.025 11.976 ;
     RECT  48.515 30.72 49.025 31.272 ;
     RECT  48.053 14.4 49.093 14.904 ;
     RECT  48.133 16.56 49.093 18.456 ;
     RECT  48.661 26.304 49.097 27.624 ;
     RECT  48.013 25.056 49.133 25.08 ;
     RECT  48.229 23.424 49.201 23.448 ;
     RECT  49.097 26.736 49.313 27.624 ;
     RECT  49.093 14.4 49.561 18.456 ;
     RECT  48.773 5.136 49.637 8.472 ;
     RECT  49.561 14.4 49.673 18.744 ;
     RECT  49.345 11.808 49.741 11.832 ;
     RECT  49.673 14.4 49.777 14.424 ;
     RECT  49.777 14.208 49.813 14.424 ;
     RECT  48.515 33.6 49.849 34.104 ;
     RECT  49.673 15.408 49.859 18.744 ;
     RECT  49.813 13.536 49.925 14.424 ;
     RECT  49.637 5.136 49.957 5.16 ;
     RECT  48.517 2.208 49.961 2.232 ;
     RECT  49.201 23.424 49.993 23.736 ;
     RECT  48.409 37.008 49.993 39.624 ;
     RECT  49.025 30.72 50.029 30.744 ;
     RECT  49.993 22.176 50.101 23.736 ;
     RECT  49.637 6.768 50.137 8.472 ;
     RECT  48.373 3.408 50.173 3.432 ;
     RECT  50.101 22.176 50.209 24.12 ;
     RECT  49.849 33.6 50.245 34.68 ;
     RECT  48.133 19.968 50.348 19.992 ;
     RECT  49.777 27.792 50.353 27.864 ;
     RECT  49.859 15.744 50.389 18.744 ;
     RECT  50.348 19.776 50.389 19.992 ;
     RECT  48.557 29.568 50.497 29.592 ;
     RECT  50.353 27.792 50.533 27.912 ;
     RECT  50.497 28.992 50.533 29.592 ;
     RECT  49.741 11.28 50.641 11.832 ;
     RECT  49.957 5.088 50.677 5.16 ;
     RECT  50.209 22.176 50.713 24.456 ;
     RECT  49.313 26.736 50.725 26.76 ;
     RECT  50.137 6.768 50.749 8.856 ;
     RECT  50.725 26.592 50.749 26.76 ;
     RECT  50.533 27.792 50.749 29.592 ;
     RECT  49.993 37.008 50.857 39.912 ;
     RECT  50.389 15.744 50.869 19.992 ;
     RECT  50.173 2.88 51.008 3.432 ;
     RECT  50.677 5.088 51.008 5.688 ;
     RECT  50.749 6.672 51.008 8.856 ;
     RECT  50.641 11.232 51.008 11.832 ;
     RECT  49.925 13.536 51.008 14.232 ;
     RECT  50.869 15.312 51.008 19.992 ;
     RECT  50.713 22.176 51.008 25.272 ;
     RECT  50.749 26.592 51.008 29.592 ;
     RECT  50.029 30.672 51.008 30.744 ;
     RECT  50.965 31.92 51.008 31.944 ;
     RECT  50.245 33.024 51.008 34.68 ;
     RECT  50.857 36.24 51.008 39.912 ;
     RECT  51.008 2.148 51.112 41.052 ;
     RECT  51.112 2.418 51.304 40.782 ;
     RECT  51.304 10.272 51.365 11.256 ;
     RECT  51.304 5.712 51.401 8.808 ;
     RECT  51.304 24.432 51.401 25.224 ;
     RECT  51.304 36.24 51.473 39.912 ;
     RECT  51.365 10.272 51.539 11.064 ;
     RECT  51.304 14.784 51.553 18.984 ;
     RECT  51.304 2.88 51.653 3.288 ;
     RECT  51.553 15.312 51.689 18.984 ;
     RECT  51.401 24.432 51.689 24.456 ;
     RECT  51.304 31.92 51.833 33.864 ;
     RECT  51.689 16.56 51.875 18.984 ;
     RECT  51.833 32.448 51.875 33.864 ;
     RECT  51.401 5.712 52.013 8.232 ;
     RECT  51.473 37.056 52.229 39.912 ;
     RECT  51.304 12.768 52.268 13.08 ;
     RECT  51.304 29.568 52.3 30.696 ;
     RECT  51.304 26.496 52.301 27.192 ;
     RECT  52.268 12.768 52.355 13.848 ;
     RECT  51.875 32.448 52.373 33.048 ;
     RECT  51.304 23.328 52.453 23.352 ;
     RECT  52.453 23.328 52.499 23.832 ;
     RECT  51.539 10.272 52.513 10.296 ;
     RECT  52.513 10.032 52.553 10.296 ;
     RECT  52.013 5.712 52.625 7.656 ;
     RECT  52.625 5.712 52.661 6.984 ;
     RECT  51.875 18.192 52.769 18.984 ;
     RECT  52.3 30.672 52.769 30.696 ;
     RECT  51.653 3.264 52.805 3.288 ;
     RECT  52.373 32.448 52.913 32.52 ;
     RECT  52.657 36 53.129 36.024 ;
     RECT  51.689 15.312 53.132 15.336 ;
     RECT  51.304 21.648 53.161 21.672 ;
     RECT  52.355 12.768 53.173 13.08 ;
     RECT  53.173 12.336 53.201 13.08 ;
     RECT  51.875 16.56 53.201 17.112 ;
     RECT  53.132 14.88 53.219 15.336 ;
     RECT  53.201 16.56 53.219 16.584 ;
     RECT  53.201 12.336 53.233 12.792 ;
     RECT  53.219 15.312 53.273 15.336 ;
     RECT  53.233 11.808 53.453 12.792 ;
     RECT  52.553 10.032 53.557 10.056 ;
     RECT  52.301 26.496 53.593 26.52 ;
     RECT  53.485 8.496 53.603 8.52 ;
     RECT  53.557 9.504 53.644 10.056 ;
     RECT  53.485 16.512 53.705 16.536 ;
     RECT  52.945 30.72 53.813 30.744 ;
     RECT  52.499 23.808 53.845 23.832 ;
     RECT  53.644 10.032 53.849 10.056 ;
     RECT  53.845 23.808 53.885 24.6 ;
     RECT  52.661 5.712 53.917 5.736 ;
     RECT  52.661 6.816 53.917 6.984 ;
     RECT  52.229 37.92 53.917 39.912 ;
     RECT  53.161 21.12 53.957 21.672 ;
     RECT  52.769 18.192 54.025 18.792 ;
     RECT  52.3 29.568 54.133 29.592 ;
     RECT  54.025 18.192 54.179 19.512 ;
     RECT  54.179 18.192 54.277 18.456 ;
     RECT  53.917 5.712 54.281 6.984 ;
     RECT  54.133 28.992 54.353 29.592 ;
     RECT  52.837 2.256 54.425 2.28 ;
     RECT  53.377 33.936 54.497 33.96 ;
     RECT  54.281 5.952 54.565 6.984 ;
     RECT  54.277 18.096 54.677 18.456 ;
     RECT  54.709 10.656 54.745 10.68 ;
     RECT  54.709 36.336 54.821 36.36 ;
     RECT  54.565 5.952 54.929 7.512 ;
     RECT  53.885 24.576 54.929 24.6 ;
     RECT  54.745 10.656 54.997 10.776 ;
     RECT  54.997 10.656 55.069 10.968 ;
     RECT  54.961 31.104 55.069 31.128 ;
     RECT  52.913 32.448 55.069 32.472 ;
     RECT  53.917 37.536 55.148 39.912 ;
     RECT  55.069 10.368 55.213 10.968 ;
     RECT  53.453 12.336 55.213 12.792 ;
     RECT  55.148 37.536 55.235 40.536 ;
     RECT  54.745 17.088 55.244 17.112 ;
     RECT  53.593 26.496 55.253 27.336 ;
     RECT  53.957 21.12 55.325 21.144 ;
     RECT  55.235 37.536 55.325 39.576 ;
     RECT  54.677 18.096 55.331 18.12 ;
     RECT  55.285 34.224 55.357 34.248 ;
     RECT  53.953 8.688 55.477 8.712 ;
     RECT  55.477 8.688 55.501 8.952 ;
     RECT  55.213 10.368 55.501 12.792 ;
     RECT  54.673 14.496 55.637 14.52 ;
     RECT  55.637 14.208 55.645 14.52 ;
     RECT  55.321 2.88 55.813 2.904 ;
     RECT  55.813 2.784 55.825 3.432 ;
     RECT  54.601 4.896 55.825 4.92 ;
     RECT  55.645 14.208 55.969 14.76 ;
     RECT  55.825 2.784 56.293 4.92 ;
     RECT  56.293 2.784 56.408 5.064 ;
     RECT  54.929 6.864 56.408 7.512 ;
     RECT  55.501 8.688 56.408 12.792 ;
     RECT  55.969 13.872 56.408 14.76 ;
     RECT  55.244 16.416 56.408 17.112 ;
     RECT  55.637 25.056 56.408 25.08 ;
     RECT  55.253 26.496 56.408 26.76 ;
     RECT  54.353 29.568 56.408 29.592 ;
     RECT  55.069 31.104 56.408 32.472 ;
     RECT  55.357 34.224 56.408 34.92 ;
     RECT  55.325 37.968 56.408 39.576 ;
     RECT  56.408 2.148 56.512 41.052 ;
     RECT  56.512 2.418 56.704 40.782 ;
     RECT  56.704 10.944 56.837 12.792 ;
     RECT  56.704 18.768 56.909 18.792 ;
     RECT  56.704 35.472 56.981 35.496 ;
     RECT  56.704 31.104 57.053 32.328 ;
     RECT  56.704 6.24 57.089 7.368 ;
     RECT  56.704 15.84 57.089 16.008 ;
     RECT  57.089 15.84 57.161 15.864 ;
     RECT  56.704 17.088 57.161 17.112 ;
     RECT  56.704 22.8 57.197 23.88 ;
     RECT  56.704 29.568 57.305 29.688 ;
     RECT  57.089 6.24 57.413 6.888 ;
     RECT  57.197 22.8 57.413 22.824 ;
     RECT  56.704 5.04 57.593 5.064 ;
     RECT  56.704 25.728 57.593 26.664 ;
     RECT  56.704 37.584 57.593 39.384 ;
     RECT  56.837 11.376 58.117 12.792 ;
     RECT  56.704 13.776 58.117 14.76 ;
     RECT  57.985 8.448 58.129 8.472 ;
     RECT  56.704 9.792 58.129 9.816 ;
     RECT  58.117 11.376 58.163 14.76 ;
     RECT  57.413 6.24 58.169 6.264 ;
     RECT  58.129 8.448 58.169 9.816 ;
     RECT  57.305 29.568 58.268 29.592 ;
     RECT  57.053 31.104 58.268 31.128 ;
     RECT  56.704 27.84 58.273 28.44 ;
     RECT  58.268 29.568 58.273 31.128 ;
     RECT  56.704 33.648 58.273 33.672 ;
     RECT  58.169 8.448 58.277 9.72 ;
     RECT  56.704 20.496 58.277 20.52 ;
     RECT  57.593 26.64 58.309 26.664 ;
     RECT  57.593 39.36 58.381 39.384 ;
     RECT  56.704 40.56 58.381 40.584 ;
     RECT  58.381 39.36 58.421 40.584 ;
     RECT  58.273 27.84 58.601 31.128 ;
     RECT  58.273 33.648 58.633 33.816 ;
     RECT  58.601 27.84 58.643 30.936 ;
     RECT  57.053 32.304 58.645 32.328 ;
     RECT  58.633 33.648 58.645 34.68 ;
     RECT  58.561 16.416 58.669 16.44 ;
     RECT  58.309 18.144 58.669 18.168 ;
     RECT  58.645 32.304 58.691 34.68 ;
     RECT  58.345 7.92 58.693 7.944 ;
     RECT  58.277 8.976 58.739 9.72 ;
     RECT  56.704 2.784 58.777 2.808 ;
     RECT  58.693 7.344 58.817 7.944 ;
     RECT  58.777 2.784 58.861 2.856 ;
     RECT  58.163 11.376 58.889 13.08 ;
     RECT  58.817 7.344 58.925 7.608 ;
     RECT  58.633 19.92 58.997 19.944 ;
     RECT  57.593 37.584 59.065 37.992 ;
     RECT  58.421 39.36 59.065 39.768 ;
     RECT  58.691 33.264 59.075 34.68 ;
     RECT  58.309 26.64 59.101 26.76 ;
     RECT  58.163 14.496 59.105 14.76 ;
     RECT  59.075 33.792 59.173 34.68 ;
     RECT  58.889 12.528 59.209 13.08 ;
     RECT  59.269 14.784 59.309 14.808 ;
     RECT  59.209 12.528 59.315 13.608 ;
     RECT  59.065 37.584 59.321 39.768 ;
     RECT  59.309 14.784 59.324 14.904 ;
     RECT  58.669 16.416 59.365 18.168 ;
     RECT  57.197 23.856 59.389 23.88 ;
     RECT  59.324 14.784 59.411 15.096 ;
     RECT  58.739 9.072 59.429 9.72 ;
     RECT  58.889 11.376 59.465 11.4 ;
     RECT  59.497 10.608 59.645 10.632 ;
     RECT  58.643 27.84 59.681 28.44 ;
     RECT  59.681 27.84 59.717 27.864 ;
     RECT  59.101 25.968 59.749 26.76 ;
     RECT  59.315 12.528 59.789 13.08 ;
     RECT  58.643 30.912 59.789 30.936 ;
     RECT  59.749 25.968 59.891 26.904 ;
     RECT  58.925 7.584 60.041 7.608 ;
     RECT  59.891 25.968 60.041 26.76 ;
     RECT  60.037 22.608 60.14 22.632 ;
     RECT  59.389 23.856 60.14 23.928 ;
     RECT  58.993 6.384 60.185 6.408 ;
     RECT  60.14 22.608 60.227 23.928 ;
     RECT  60.041 25.968 60.257 26.712 ;
     RECT  59.321 37.584 60.293 37.992 ;
     RECT  59.365 16.416 60.329 18.264 ;
     RECT  59.173 33.792 60.401 34.776 ;
     RECT  59.429 9.072 60.433 9.096 ;
     RECT  58.861 2.784 60.437 2.808 ;
     RECT  59.029 36.384 60.437 36.408 ;
     RECT  60.257 25.968 60.509 26.136 ;
     RECT  60.329 16.416 60.689 17.112 ;
     RECT  60.329 18.24 60.689 18.264 ;
     RECT  58.643 29.568 60.793 29.592 ;
     RECT  60.289 13.584 61.009 13.656 ;
     RECT  59.411 14.784 61.009 14.808 ;
     RECT  60.793 29.568 61.333 30.264 ;
     RECT  60.689 16.992 61.532 17.112 ;
     RECT  60.401 34.752 61.573 34.776 ;
     RECT  61.261 36.48 61.573 36.504 ;
     RECT  60.293 37.968 61.573 37.992 ;
     RECT  60.397 7.968 61.808 7.992 ;
     RECT  60.433 9.072 61.808 10.056 ;
     RECT  59.789 12.528 61.808 12.552 ;
     RECT  61.009 13.584 61.808 14.808 ;
     RECT  61.532 16.992 61.808 17.832 ;
     RECT  61.009 20.928 61.808 20.952 ;
     RECT  60.227 22.608 61.808 22.632 ;
     RECT  60.227 23.904 61.808 23.928 ;
     RECT  60.829 25.056 61.808 25.08 ;
     RECT  60.509 26.112 61.808 26.136 ;
     RECT  61.333 29.04 61.808 30.264 ;
     RECT  61.117 33.6 61.808 33.624 ;
     RECT  61.573 34.752 61.808 37.992 ;
     RECT  59.321 39.744 61.808 39.768 ;
     RECT  61.808 2.148 61.912 41.052 ;
     RECT  61.912 2.418 62.104 40.782 ;
    LAYER M5 ;
     RECT  5.088 0.016 8.088 0.133 ;
     RECT  5.088 0.133 8.232 1.763 ;
     RECT  5.376 1.763 8.232 1.811 ;
     RECT  5.472 1.811 8.232 1.859 ;
     RECT  2.4 2.137 2.52 2.151 ;
     RECT  13.2 2.137 13.32 2.151 ;
     RECT  18.6 2.137 18.72 2.151 ;
     RECT  24 2.137 24.12 2.151 ;
     RECT  29.4 2.137 29.52 2.151 ;
     RECT  34.8 2.137 34.92 2.151 ;
     RECT  40.2 2.137 40.32 2.151 ;
     RECT  45.6 2.137 45.72 2.151 ;
     RECT  51 2.137 51.12 2.151 ;
     RECT  56.4 2.137 56.52 2.151 ;
     RECT  61.8 2.137 61.92 2.151 ;
     RECT  24 2.151 24.312 2.629 ;
     RECT  56.4 2.151 56.712 2.773 ;
     RECT  43.776 2.293 43.8 2.821 ;
     RECT  5.568 1.859 8.232 2.915 ;
     RECT  43.776 2.821 44.376 2.915 ;
     RECT  5.76 2.915 8.112 3.443 ;
     RECT  55.824 2.773 56.712 3.443 ;
     RECT  34.8 2.151 35.112 3.733 ;
     RECT  29.4 2.151 29.712 3.925 ;
     RECT  24 2.629 24.552 3.971 ;
     RECT  38.592 3.925 38.616 4.547 ;
     RECT  5.904 3.443 8.112 4.595 ;
     RECT  5.904 4.595 5.928 4.931 ;
     RECT  16.032 4.309 16.056 4.931 ;
     RECT  51 2.151 51.312 5.077 ;
     RECT  22.704 4.501 22.728 5.123 ;
     RECT  14.928 4.501 14.952 5.125 ;
     RECT  14.832 5.125 14.952 5.171 ;
     RECT  42.864 3.925 42.888 5.171 ;
     RECT  48.432 4.549 48.456 5.171 ;
     RECT  29.04 3.925 30.504 5.219 ;
     RECT  12 3.397 12.024 5.459 ;
     RECT  29.04 5.219 29.712 6.085 ;
     RECT  50.112 5.077 51.312 6.803 ;
     RECT  7.488 4.595 8.112 6.805 ;
     RECT  50.352 6.803 51.312 6.805 ;
     RECT  27.312 6.229 27.336 6.851 ;
     RECT  7.488 6.805 8.52 6.899 ;
     RECT  58.8 2.821 58.824 7.333 ;
     RECT  58.704 7.333 58.824 7.379 ;
     RECT  24 3.971 24.312 7.381 ;
     RECT  36.72 5.365 36.744 7.381 ;
     RECT  5.52 7.285 5.544 7.427 ;
     RECT  36.72 7.381 37.032 7.427 ;
     RECT  3.84 6.805 3.864 7.475 ;
     RECT  15.984 6.133 16.008 7.475 ;
     RECT  56.4 3.443 56.712 7.477 ;
     RECT  20.592 3.397 20.616 7.765 ;
     RECT  20.592 7.765 20.808 7.811 ;
     RECT  13.2 2.151 13.512 7.957 ;
     RECT  14.832 5.171 14.856 7.957 ;
     RECT  27.744 7.381 27.768 8.003 ;
     RECT  37.008 7.427 37.032 8.003 ;
     RECT  47.376 5.797 47.4 8.003 ;
     RECT  7.8 6.899 8.52 8.005 ;
     RECT  5.136 8.005 5.16 8.195 ;
     RECT  7.8 8.005 8.616 8.195 ;
     RECT  31.872 7.381 31.896 8.195 ;
     RECT  13.2 7.957 14.856 8.341 ;
     RECT  13.008 8.341 14.856 8.483 ;
     RECT  50.352 6.805 51.432 8.483 ;
     RECT  6.576 7.861 6.6 8.819 ;
     RECT  34.8 3.733 35.592 8.963 ;
     RECT  55.488 7.477 56.712 8.963 ;
     RECT  13.2 8.483 14.856 9.107 ;
     RECT  28.752 6.085 29.712 9.155 ;
     RECT  24 7.381 24.792 9.299 ;
     RECT  7.8 8.195 8.232 9.349 ;
     RECT  53.568 8.485 53.592 9.539 ;
     RECT  25.872 9.253 25.896 10.355 ;
     RECT  7.8 9.349 8.472 10.405 ;
     RECT  7.584 10.405 8.472 10.451 ;
     RECT  36.576 9.061 36.6 10.739 ;
     RECT  51 8.483 51.432 11.029 ;
     RECT  14.832 9.107 14.856 11.125 ;
     RECT  14.832 11.125 15.384 11.171 ;
     RECT  18.6 2.151 18.912 11.269 ;
     RECT  51 11.029 51.528 11.269 ;
     RECT  48.288 8.437 48.312 11.459 ;
     RECT  7.584 10.451 8.232 11.747 ;
     RECT  18.6 11.269 19.176 11.795 ;
     RECT  13.2 9.107 13.512 11.845 ;
     RECT  41.856 10.165 41.88 11.939 ;
     RECT  22.848 9.685 22.872 12.035 ;
     RECT  20.784 7.811 20.808 12.179 ;
     RECT  38.304 11.653 38.328 12.467 ;
     RECT  7.584 11.747 8.112 12.565 ;
     RECT  14.928 11.171 15.384 12.755 ;
     RECT  58.704 7.379 58.728 12.757 ;
     RECT  58.704 12.757 59.352 12.803 ;
     RECT  7.152 12.565 8.112 12.899 ;
     RECT  22.224 12.133 22.248 12.901 ;
     RECT  50.112 11.269 51.528 13.045 ;
     RECT  53.184 12.325 53.208 13.045 ;
     RECT  44.352 2.915 44.376 13.237 ;
     RECT  44.352 13.237 44.568 13.283 ;
     RECT  50.112 13.045 53.208 13.571 ;
     RECT  31.392 11.941 31.416 13.715 ;
     RECT  58.128 13.045 58.152 13.811 ;
     RECT  12.576 11.845 13.512 13.859 ;
     RECT  16.56 11.941 16.584 13.859 ;
     RECT  51 13.571 53.208 13.859 ;
     RECT  21.984 12.901 22.248 14.053 ;
     RECT  47.664 12.757 47.688 14.101 ;
     RECT  21.984 14.053 22.68 14.197 ;
     RECT  56.4 8.963 56.712 14.197 ;
     RECT  21.408 14.197 22.68 14.675 ;
     RECT  44.448 13.283 44.568 14.773 ;
     RECT  59.28 12.803 59.352 14.819 ;
     RECT  47.136 14.101 47.688 14.915 ;
     RECT  59.328 14.819 59.352 14.915 ;
     RECT  21.408 14.675 21.432 14.917 ;
     RECT  51 13.859 51.528 15.301 ;
     RECT  12.864 13.859 13.512 15.397 ;
     RECT  15.36 12.755 15.384 15.443 ;
     RECT  31.872 14.197 31.896 15.443 ;
     RECT  47.136 14.915 47.16 15.443 ;
     RECT  33.024 12.517 33.048 15.685 ;
     RECT  32.736 15.685 33.048 15.731 ;
     RECT  12.864 15.397 13.8 15.829 ;
     RECT  12 15.829 13.8 15.875 ;
     RECT  6.624 14.773 6.648 15.925 ;
     RECT  10.224 14.773 10.248 16.019 ;
     RECT  34.8 8.963 35.208 16.019 ;
     RECT  38.352 15.349 38.376 16.019 ;
     RECT  21.312 14.917 21.432 16.259 ;
     RECT  55.68 14.197 56.712 16.405 ;
     RECT  55.296 16.405 56.712 16.451 ;
     RECT  3.888 14.389 3.912 16.547 ;
     RECT  2.4 2.151 2.712 16.549 ;
     RECT  26.064 14.917 26.088 16.595 ;
     RECT  32.736 15.731 32.76 16.595 ;
     RECT  53.184 13.859 53.208 16.595 ;
     RECT  50.88 15.301 51.528 16.643 ;
     RECT  6.24 15.925 6.648 16.691 ;
     RECT  24 9.299 24.312 16.789 ;
     RECT  22.656 14.675 22.68 16.835 ;
     RECT  24 16.789 24.408 16.981 ;
     RECT  28.08 14.773 28.104 16.981 ;
     RECT  29.4 9.155 29.712 16.981 ;
     RECT  61.8 2.151 62.112 16.981 ;
     RECT  28.08 16.981 29.712 17.027 ;
     RECT  44.352 14.773 44.568 17.027 ;
     RECT  28.464 17.027 29.712 17.077 ;
     RECT  43.296 16.981 43.32 17.077 ;
     RECT  44.352 17.027 44.376 17.077 ;
     RECT  60.96 16.981 62.112 17.123 ;
     RECT  47.904 16.597 47.928 17.219 ;
     RECT  49.824 15.397 49.848 17.315 ;
     RECT  12 15.875 12.024 17.317 ;
     RECT  13.2 15.875 13.8 17.317 ;
     RECT  12 17.317 13.8 17.363 ;
     RECT  28.464 17.077 29.976 17.411 ;
     RECT  51 16.643 51.528 17.461 ;
     RECT  40.2 2.151 40.512 17.653 ;
     RECT  12.528 17.363 13.8 17.699 ;
     RECT  61.584 17.123 62.112 17.843 ;
     RECT  33.024 17.029 33.048 17.891 ;
     RECT  55.296 16.451 55.32 18.131 ;
     RECT  51 17.461 51.864 18.275 ;
     RECT  59.376 15.061 59.4 18.275 ;
     RECT  2.4 16.549 3.432 18.563 ;
     RECT  6.24 16.691 6.264 18.613 ;
     RECT  5.952 18.613 6.264 18.659 ;
     RECT  40.08 17.653 40.512 18.709 ;
     RECT  29.4 17.411 29.976 18.757 ;
     RECT  37.008 18.085 37.032 18.851 ;
     RECT  43.296 17.077 44.376 18.851 ;
     RECT  51 18.275 51.312 18.949 ;
     RECT  13.2 17.699 13.8 19.093 ;
     RECT  39.264 18.709 40.512 19.237 ;
     RECT  29.4 18.757 30.12 19.333 ;
     RECT  44.352 18.851 44.376 19.333 ;
     RECT  45.6 2.151 45.912 19.333 ;
     RECT  29.4 19.333 30.744 19.379 ;
     RECT  48.096 18.421 48.12 19.427 ;
     RECT  34.8 16.019 35.112 19.477 ;
     RECT  30.72 19.379 30.744 19.523 ;
     RECT  33.072 18.757 33.096 19.523 ;
     RECT  13.2 19.093 13.896 19.811 ;
     RECT  39.216 19.237 40.512 19.861 ;
     RECT  24 16.981 24.504 20.003 ;
     RECT  50.4 18.949 51.312 20.003 ;
     RECT  34.464 19.477 35.112 20.051 ;
     RECT  38.784 19.861 40.512 20.051 ;
     RECT  37.776 19.333 37.8 20.147 ;
     RECT  48.048 19.909 48.072 20.387 ;
     RECT  5.952 18.659 5.976 20.579 ;
     RECT  38.784 20.051 38.808 20.579 ;
     RECT  44.352 19.333 45.912 21.011 ;
     RECT  44.352 21.011 44.376 21.109 ;
     RECT  38.592 20.581 38.616 21.155 ;
     RECT  41.856 20.053 41.88 21.155 ;
     RECT  43.92 21.109 44.376 21.155 ;
     RECT  54.144 18.421 54.168 21.155 ;
     RECT  0.192 4.021 0.216 21.491 ;
     RECT  29.4 19.379 29.712 21.589 ;
     RECT  40.2 20.051 40.512 21.637 ;
     RECT  29.28 21.589 29.712 21.731 ;
     RECT  39.216 21.637 40.512 21.925 ;
     RECT  34.8 20.051 35.112 22.021 ;
     RECT  21.408 16.259 21.432 22.117 ;
     RECT  32.496 21.061 32.52 22.211 ;
     RECT  21.408 22.117 21.528 22.261 ;
     RECT  21.36 22.261 21.528 22.307 ;
     RECT  43.92 21.155 43.944 22.549 ;
     RECT  51 20.003 51.312 22.741 ;
     RECT  39.216 21.925 40.632 22.835 ;
     RECT  60.048 22.597 60.072 23.125 ;
     RECT  21.36 22.307 21.384 23.317 ;
     RECT  45.6 21.011 45.912 23.317 ;
     RECT  43.152 22.549 43.944 23.363 ;
     RECT  6.72 22.645 6.744 23.411 ;
     RECT  15.456 22.165 15.48 23.411 ;
     RECT  34.176 22.021 35.112 23.795 ;
     RECT  52.464 21.637 52.488 23.843 ;
     RECT  60.048 23.125 60.216 23.891 ;
     RECT  60.192 23.891 60.216 23.939 ;
     RECT  34.416 23.795 35.112 23.987 ;
     RECT  50.256 22.741 51.312 24.085 ;
     RECT  44.976 23.317 45.912 24.755 ;
     RECT  26.4 24.229 26.424 24.997 ;
     RECT  7.8 12.899 8.112 25.045 ;
     RECT  29.4 21.731 29.712 25.045 ;
     RECT  56.4 16.451 56.712 25.045 ;
     RECT  22.992 21.829 23.016 25.139 ;
     RECT  26.4 24.997 26.52 25.139 ;
     RECT  45.6 24.755 45.912 25.189 ;
     RECT  43.92 23.363 43.944 25.573 ;
     RECT  7.8 25.045 8.376 25.715 ;
     RECT  29.4 25.045 30.264 25.859 ;
     RECT  37.2 22.165 37.224 25.861 ;
     RECT  5.136 24.469 5.16 26.243 ;
     RECT  20.4 23.317 21.384 26.243 ;
     RECT  43.92 25.573 44.472 26.243 ;
     RECT  45.6 25.189 46.488 26.531 ;
     RECT  26.4 25.139 26.424 26.675 ;
     RECT  55.68 25.045 56.712 26.675 ;
     RECT  50.112 24.085 51.312 26.771 ;
     RECT  59.856 26.677 59.88 26.915 ;
     RECT  40.2 22.835 40.512 27.109 ;
     RECT  42.72 25.045 42.744 27.155 ;
     RECT  13.2 19.811 13.512 27.157 ;
     RECT  40.08 27.109 40.512 27.205 ;
     RECT  27.408 26.629 27.432 27.301 ;
     RECT  13.2 27.157 13.608 27.347 ;
     RECT  33.024 26.677 33.048 27.395 ;
     RECT  20.4 26.243 20.424 27.589 ;
     RECT  20.016 27.589 20.424 27.635 ;
     RECT  37.2 25.861 37.944 27.733 ;
     RECT  21.648 26.725 21.672 27.875 ;
     RECT  43.92 26.243 44.04 27.875 ;
     RECT  27.408 27.301 28.2 27.971 ;
     RECT  7.8 25.715 8.112 28.309 ;
     RECT  58.32 26.629 58.344 28.405 ;
     RECT  11.952 24.373 11.976 28.453 ;
     RECT  27.696 27.971 28.2 28.547 ;
     RECT  37.2 27.733 38.184 28.547 ;
     RECT  43.92 27.875 43.944 28.547 ;
     RECT  40.08 27.205 41.064 28.691 ;
     RECT  20.016 27.635 20.04 28.933 ;
     RECT  20.016 28.933 20.52 28.979 ;
     RECT  50.88 26.771 51.312 29.027 ;
     RECT  61.8 17.843 62.112 29.029 ;
     RECT  38.16 28.547 38.184 29.075 ;
     RECT  22.752 28.645 22.776 29.123 ;
     RECT  27.696 28.547 27.72 29.123 ;
     RECT  47.328 27.349 47.352 29.123 ;
     RECT  24 20.003 24.312 29.509 ;
     RECT  45.6 26.531 45.912 29.605 ;
     RECT  5.184 26.725 5.208 29.653 ;
     RECT  5.184 29.653 5.4 29.699 ;
     RECT  51 29.027 51.312 29.893 ;
     RECT  32.448 28.981 32.472 30.035 ;
     RECT  10.848 29.413 10.872 30.037 ;
     RECT  11.952 28.453 12.024 30.037 ;
     RECT  10.848 30.037 12.024 30.083 ;
     RECT  34.8 23.987 35.112 30.181 ;
     RECT  7.8 28.309 9.096 30.227 ;
     RECT  61.344 29.029 62.112 30.275 ;
     RECT  45.6 29.605 46.728 30.323 ;
     RECT  24 29.509 24.408 30.419 ;
     RECT  15.84 28.789 15.864 30.563 ;
     RECT  51 29.893 52.248 30.707 ;
     RECT  7.8 30.227 8.112 30.757 ;
     RECT  6.864 30.757 8.112 30.899 ;
     RECT  58.32 28.405 58.632 30.947 ;
     RECT  34.8 30.181 36.024 31.139 ;
     RECT  3.936 30.709 3.96 31.379 ;
     RECT  47.664 30.757 47.688 31.765 ;
     RECT  7.8 30.899 8.112 31.861 ;
     RECT  45.6 30.323 45.912 31.861 ;
     RECT  11.088 30.083 12.024 31.955 ;
     RECT  37.968 31.237 37.992 32.149 ;
     RECT  40.08 28.691 40.512 32.293 ;
     RECT  56.4 26.675 56.712 32.293 ;
     RECT  58.32 30.947 58.344 32.293 ;
     RECT  41.952 31.525 41.976 32.339 ;
     RECT  58.32 32.293 58.68 32.339 ;
     RECT  13.2 27.347 13.512 32.341 ;
     RECT  13.2 32.341 13.656 32.437 ;
     RECT  47.664 31.765 48.504 32.437 ;
     RECT  51 30.707 51.312 32.437 ;
     RECT  47.664 32.437 48.888 32.483 ;
     RECT  56.304 32.293 56.712 32.483 ;
     RECT  7.8 31.861 8.664 32.531 ;
     RECT  47.712 32.483 48.888 32.819 ;
     RECT  40.08 32.293 40.776 32.867 ;
     RECT  37.632 32.149 37.992 33.061 ;
     RECT  40.08 32.867 40.512 33.061 ;
     RECT  17.088 32.917 17.544 33.107 ;
     RECT  43.344 31.525 43.368 33.107 ;
     RECT  58.656 32.339 58.68 33.253 ;
     RECT  37.632 33.061 38.184 33.299 ;
     RECT  58.656 33.253 59.064 33.299 ;
     RECT  5.376 29.699 5.4 33.733 ;
     RECT  4.608 33.733 5.4 33.779 ;
     RECT  4.608 33.779 4.632 33.781 ;
     RECT  47.712 32.819 47.88 33.827 ;
     RECT  12.096 32.917 12.12 33.875 ;
     RECT  51 32.437 51.864 33.875 ;
     RECT  45.6 31.861 46.488 33.923 ;
     RECT  47.712 33.827 47.784 33.923 ;
     RECT  39.36 33.061 40.512 34.115 ;
     RECT  59.04 33.299 59.064 34.117 ;
     RECT  29.4 25.859 29.712 34.165 ;
     RECT  47.76 33.923 47.784 34.259 ;
     RECT  37.968 33.299 38.184 34.355 ;
     RECT  5.616 34.165 5.64 34.501 ;
     RECT  37.968 34.355 37.992 34.691 ;
     RECT  34.8 31.139 35.112 34.741 ;
     RECT  61.8 30.275 62.112 34.741 ;
     RECT  59.04 34.117 59.208 34.787 ;
     RECT  12.144 34.741 12.168 34.883 ;
     RECT  29.4 34.165 30.552 34.885 ;
     RECT  27.36 34.741 27.384 34.933 ;
     RECT  29.4 34.885 30.648 35.027 ;
     RECT  33.072 34.117 33.096 35.027 ;
     RECT  13.2 32.437 14.232 35.317 ;
     RECT  9.264 34.597 9.288 35.363 ;
     RECT  34.8 34.741 35.736 35.363 ;
     RECT  3.936 33.781 4.632 35.459 ;
     RECT  17.52 33.107 17.544 35.699 ;
     RECT  5.616 34.501 6.456 35.749 ;
     RECT  7.8 32.531 8.112 35.749 ;
     RECT  18.6 11.795 18.912 36.229 ;
     RECT  4.608 35.459 4.632 36.421 ;
     RECT  5.616 35.749 8.112 36.613 ;
     RECT  4.56 36.421 4.632 36.661 ;
     RECT  5.616 36.613 8.232 36.661 ;
     RECT  24 30.419 24.312 36.661 ;
     RECT  20.496 28.979 20.52 36.707 ;
     RECT  43.536 35.269 43.56 36.709 ;
     RECT  43.536 36.709 44.472 36.755 ;
     RECT  29.4 35.027 29.832 36.757 ;
     RECT  26.4 34.933 27.384 36.803 ;
     RECT  23.376 36.661 24.312 36.899 ;
     RECT  48.864 32.819 48.888 37.043 ;
     RECT  18.192 36.229 18.912 37.091 ;
     RECT  21.648 36.469 21.672 37.091 ;
     RECT  41.568 35.269 41.592 37.091 ;
     RECT  61.584 34.741 62.112 37.283 ;
     RECT  4.56 36.661 8.232 37.573 ;
     RECT  13.2 35.317 14.424 37.573 ;
     RECT  29.088 36.757 29.832 37.667 ;
     RECT  31.872 35.845 31.896 37.667 ;
     RECT  29.4 37.667 29.832 37.763 ;
     RECT  34.8 35.363 35.112 38.005 ;
     RECT  4.56 37.573 9.144 38.147 ;
     RECT  13.2 37.573 14.808 38.291 ;
     RECT  4.752 38.147 9.144 38.387 ;
     RECT  39.888 34.115 40.512 38.675 ;
     RECT  13.2 38.291 14.424 38.819 ;
     RECT  15.504 38.677 15.528 38.819 ;
     RECT  16.608 38.149 16.632 38.819 ;
     RECT  52.512 38.149 52.536 38.819 ;
     RECT  34.8 38.005 35.928 39.253 ;
     RECT  42.432 38.581 42.456 39.253 ;
     RECT  42.432 39.253 42.744 39.299 ;
     RECT  5.616 38.387 9.144 39.395 ;
     RECT  23.52 36.899 24.312 39.395 ;
     RECT  26.4 36.803 26.424 39.395 ;
     RECT  59.04 34.787 59.064 39.395 ;
     RECT  39.984 38.675 40.512 39.923 ;
     RECT  51 33.875 51.48 39.923 ;
     RECT  44.448 36.755 44.472 40.307 ;
     RECT  33.84 39.253 35.928 40.355 ;
     RECT  6.048 39.395 9.144 40.499 ;
     RECT  22.176 39.253 22.2 40.499 ;
     RECT  34.8 40.355 35.928 40.547 ;
     RECT  55.2 39.349 55.224 40.547 ;
     RECT  26.544 39.781 26.568 40.595 ;
     RECT  42.72 39.299 42.744 40.595 ;
     RECT  2.4 18.563 2.712 41.049 ;
     RECT  6.144 40.499 8.112 41.049 ;
     RECT  13.2 38.819 13.512 41.049 ;
     RECT  18.6 37.091 18.912 41.049 ;
     RECT  24 39.395 24.312 41.049 ;
     RECT  29.4 37.763 29.712 41.049 ;
     RECT  34.8 40.547 35.112 41.049 ;
     RECT  40.2 39.923 40.512 41.049 ;
     RECT  45.6 33.923 45.912 41.049 ;
     RECT  51 39.923 51.312 41.049 ;
     RECT  56.4 32.483 56.712 41.049 ;
     RECT  61.8 37.283 62.112 41.049 ;
     RECT  2.4 41.049 2.52 41.063 ;
     RECT  6.144 41.049 7.92 41.063 ;
     RECT  13.2 41.049 13.32 41.063 ;
     RECT  18.6 41.049 18.72 41.063 ;
     RECT  24 41.049 24.12 41.063 ;
     RECT  29.4 41.049 29.52 41.063 ;
     RECT  34.8 41.049 34.92 41.063 ;
     RECT  40.2 41.049 40.32 41.063 ;
     RECT  45.6 41.049 45.72 41.063 ;
     RECT  51 41.049 51.12 41.063 ;
     RECT  56.4 41.049 56.52 41.063 ;
     RECT  61.8 41.049 61.92 41.063 ;
     RECT  5.088 40.981 5.112 41.605 ;
     RECT  6.144 41.063 7.704 41.605 ;
     RECT  5.088 41.605 7.704 42.805 ;
     RECT  5.088 42.805 8.088 43.152 ;
     RECT  44.376 2.821 45.6 13.237 ;
     RECT  43.776 2.915 44.352 3.925 ;
     RECT  12.024 3.397 13.2 5.459 ;
     RECT  42.888 3.925 44.352 5.171 ;
     RECT  13.512 4.501 14.928 5.125 ;
     RECT  14.952 4.501 16.032 4.931 ;
     RECT  22.728 4.501 24 5.123 ;
     RECT  14.952 4.931 16.008 5.171 ;
     RECT  13.512 5.125 14.832 7.957 ;
     RECT  14.856 5.171 16.008 6.133 ;
     RECT  35.592 5.365 36.72 7.427 ;
     RECT  45.912 5.797 47.376 8.003 ;
     RECT  14.856 6.133 15.984 7.475 ;
     RECT  27.336 6.229 28.752 6.851 ;
     RECT  2.712 6.805 3.84 7.475 ;
     RECT  27.744 6.851 28.752 7.381 ;
     RECT  7.488 6.899 7.8 7.861 ;
     RECT  27.768 7.381 28.752 8.003 ;
     RECT  5.52 7.427 5.544 7.861 ;
     RECT  35.592 7.427 37.008 8.003 ;
     RECT  5.52 7.861 6.576 8.005 ;
     RECT  6.6 7.861 7.8 8.819 ;
     RECT  35.592 8.003 36.6 8.963 ;
     RECT  5.16 8.005 6.576 8.195 ;
     RECT  8.232 8.195 8.472 9.349 ;
     RECT  35.208 8.963 36.6 9.061 ;
     RECT  35.208 9.061 36.576 10.739 ;
     RECT  13.512 9.107 14.832 11.171 ;
     RECT  24.792 9.253 25.872 9.299 ;
     RECT  22.872 9.685 24 12.035 ;
     RECT  40.512 10.165 41.856 11.939 ;
     RECT  13.512 11.171 14.928 12.755 ;
     RECT  15.384 11.941 16.56 13.859 ;
     RECT  20.808 12.133 22.224 12.179 ;
     RECT  21.984 12.179 22.224 12.901 ;
     RECT  58.704 12.803 59.28 13.045 ;
     RECT  56.712 13.045 58.128 13.811 ;
     RECT  58.152 13.045 59.28 13.811 ;
     RECT  44.568 13.237 45.6 17.027 ;
     RECT  44.352 13.283 44.448 14.773 ;
     RECT  22.68 14.053 24 16.835 ;
     RECT  45.912 14.101 47.136 15.443 ;
     RECT  31.896 14.197 33.024 15.443 ;
     RECT  2.712 14.389 3.888 16.547 ;
     RECT  21.432 14.675 22.656 16.835 ;
     RECT  6.648 14.773 7.8 16.691 ;
     RECT  28.104 14.773 29.4 16.981 ;
     RECT  49.848 15.397 50.88 16.643 ;
     RECT  32.736 15.443 33.024 15.685 ;
     RECT  32.76 15.731 33.048 16.595 ;
     RECT  12.024 15.875 13.2 17.317 ;
     RECT  55.32 16.451 56.4 18.131 ;
     RECT  2.712 16.547 3.432 16.549 ;
     RECT  33.024 16.595 33.048 17.029 ;
     RECT  49.848 16.643 51 17.315 ;
     RECT  43.32 16.981 44.352 17.077 ;
     RECT  44.376 17.027 45.6 19.333 ;
     RECT  37.8 19.333 39.216 19.861 ;
     RECT  29.712 19.379 30.72 19.523 ;
     RECT  33.096 19.477 34.464 19.523 ;
     RECT  37.8 19.861 38.784 20.147 ;
     RECT  38.808 20.051 40.2 20.579 ;
     RECT  40.512 20.053 41.856 21.155 ;
     RECT  38.592 20.147 38.784 20.579 ;
     RECT  38.592 20.579 40.2 20.581 ;
     RECT  38.616 20.581 40.2 21.155 ;
     RECT  44.376 21.011 45.6 21.155 ;
     RECT  39.216 21.155 40.2 21.637 ;
     RECT  40.512 21.155 40.632 21.925 ;
     RECT  51.312 21.637 52.464 23.843 ;
     RECT  23.016 21.829 24 25.139 ;
     RECT  21.528 22.117 22.992 22.307 ;
     RECT  6.744 22.645 7.8 23.411 ;
     RECT  18.912 23.317 20.4 27.589 ;
     RECT  43.944 23.317 44.976 24.755 ;
     RECT  11.976 24.373 13.2 28.453 ;
     RECT  43.944 24.755 45.6 25.573 ;
     RECT  42.744 25.045 43.92 27.155 ;
     RECT  26.424 25.139 26.52 26.629 ;
     RECT  44.472 25.573 45.6 26.243 ;
     RECT  20.424 26.243 21.384 26.725 ;
     RECT  45.912 26.531 46.488 27.349 ;
     RECT  26.424 26.629 27.408 26.675 ;
     RECT  58.344 26.677 59.856 26.915 ;
     RECT  20.424 26.725 21.648 27.635 ;
     RECT  58.344 26.915 58.632 28.405 ;
     RECT  28.2 27.301 29.4 28.547 ;
     RECT  45.912 27.349 47.328 29.123 ;
     RECT  18.912 27.589 20.016 28.979 ;
     RECT  20.04 27.635 21.648 27.875 ;
     RECT  20.04 27.875 20.52 28.933 ;
     RECT  12.024 28.453 13.2 31.955 ;
     RECT  22.776 28.645 24 29.123 ;
     RECT  45.912 29.123 46.728 29.605 ;
     RECT  10.872 29.413 11.952 30.037 ;
     RECT  5.184 29.699 5.376 30.709 ;
     RECT  2.712 30.709 3.936 31.379 ;
     RECT  3.96 30.709 5.376 31.379 ;
     RECT  5.4 30.757 6.864 30.899 ;
     RECT  58.344 30.947 58.632 32.293 ;
     RECT  40.512 31.525 41.952 32.293 ;
     RECT  41.976 31.525 43.344 32.339 ;
     RECT  46.488 31.861 47.664 32.483 ;
     RECT  12.096 31.955 13.2 32.917 ;
     RECT  40.776 32.293 41.952 32.339 ;
     RECT  46.488 32.483 47.712 33.923 ;
     RECT  47.88 32.819 48.864 33.827 ;
     RECT  12.12 32.917 13.2 33.875 ;
     RECT  17.544 32.917 18.6 35.699 ;
     RECT  38.184 33.061 39.36 34.115 ;
     RECT  4.632 33.779 5.4 34.165 ;
     RECT  2.712 33.781 3.936 35.459 ;
     RECT  47.784 33.827 48.864 34.259 ;
     RECT  12.144 33.875 13.2 34.741 ;
     RECT  4.632 34.165 5.616 36.661 ;
     RECT  6.456 34.501 7.8 35.749 ;
     RECT  8.112 34.597 9.264 35.363 ;
     RECT  12.168 34.741 13.2 34.883 ;
     RECT  40.512 35.269 41.568 37.091 ;
     RECT  8.112 35.363 8.232 36.613 ;
     RECT  4.56 35.459 4.608 36.421 ;
     RECT  18.192 35.699 18.6 36.229 ;
     RECT  20.52 36.469 21.648 36.707 ;
     RECT  44.472 36.709 45.6 40.307 ;
     RECT  51.48 38.149 52.512 38.819 ;
     RECT  14.424 38.291 14.808 38.677 ;
     RECT  14.424 38.677 15.504 38.819 ;
     RECT  15.528 38.677 16.608 38.819 ;
     RECT  22.2 39.253 23.52 39.395 ;
     RECT  55.224 39.349 56.4 40.547 ;
     RECT  6.048 40.499 6.144 40.981 ;
     RECT  5.112 40.981 6.144 41.605 ;
  END
END ot_s81_engram_signed_sqrt
END LIBRARY
